###############################################################
#  Generated by:      Cadence Innovus 20.13-s083_1
#  OS:                Linux x86_64(Host ID rice-503-20-north)
#  Generated on:      Fri Jun 17 02:15:51 2022
#  Design:            user_proj_example
#  Command:           write_lef_abstract -specifyTopLayer 5 -PGPinLayers {5 6} -extractBlockObs -stripePin results/user_proj_example.lef
###############################################################

VERSION 5.8 ;

BUSBITCHARS "[]" ;
DIVIDERCHAR "/" ;

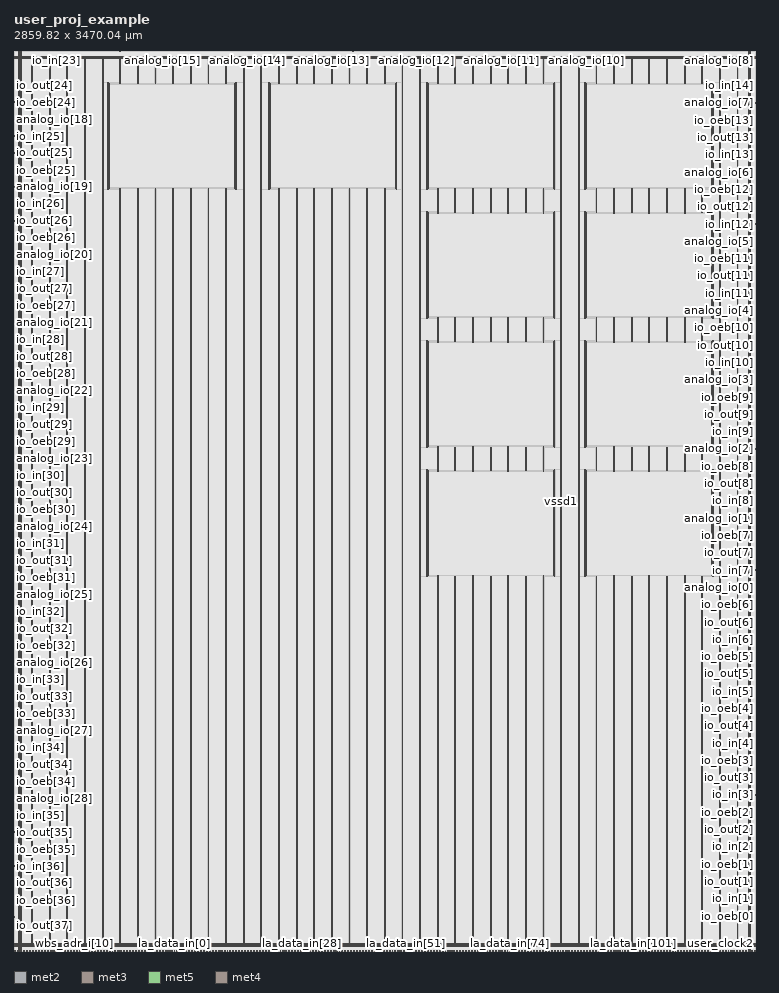
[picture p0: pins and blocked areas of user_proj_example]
MACRO user_proj_example
  CLASS BLOCK ;
  SIZE 2859.820000 BY 3470.040000 ;
  FOREIGN user_proj_example 0.000000 0.000000 ;
  ORIGIN 0 0 ;
  SYMMETRY X Y R90 ;
  PIN wb_clk_i
    DIRECTION INPUT ;
    USE SIGNAL ;
    ANTENNAPARTIALMETALAREA 3.0716 LAYER met2  ;
    ANTENNAPARTIALMETALSIDEAREA 15.197 LAYER met2  ;
    ANTENNAPARTIALCUTAREA 0.04 LAYER via2  ;
    ANTENNAPARTIALMETALAREA 8.6748 LAYER met3  ;
    ANTENNAPARTIALMETALSIDEAREA 46.736 LAYER met3  ;
    ANTENNAMODEL OXIDE1 ;
    ANTENNAGATEAREA 0.576 LAYER met3  ;
    ANTENNAMAXAREACAR 18.0158 LAYER met3  ;
    ANTENNAMAXSIDEAREACAR 93.7205 LAYER met3  ;
    ANTENNAMAXCUTCAR 0.158681 LAYER via3  ;
    PORT
      LAYER met2 ;
        RECT 0.160000 0.000000 0.300000 0.485000 ;
    END
  END wb_clk_i
  PIN wb_rst_i
    DIRECTION INPUT ;
    USE SIGNAL ;
    ANTENNAPARTIALMETALAREA 7.5498 LAYER met2  ;
    ANTENNAPARTIALMETALSIDEAREA 36.792 LAYER met2  ;
    ANTENNAMODEL OXIDE1 ;
    ANTENNAGATEAREA 2.2275 LAYER met2  ;
    ANTENNAMAXAREACAR 25.2597 LAYER met2  ;
    ANTENNAMAXSIDEAREACAR 123.945 LAYER met2  ;
    ANTENNAPARTIALCUTAREA 0.04 LAYER via2  ;
    ANTENNAMAXCUTCAR 0.316543 LAYER via2  ;
    ANTENNAPARTIALMETALAREA 13.7328 LAYER met3  ;
    ANTENNAPARTIALMETALSIDEAREA 73.712 LAYER met3  ;
    ANTENNAGATEAREA 8.055 LAYER met3  ;
    ANTENNAMAXAREACAR 26.9645 LAYER met3  ;
    ANTENNAMAXSIDEAREACAR 133.097 LAYER met3  ;
    ANTENNAMAXCUTCAR 0.316543 LAYER via3  ;
    PORT
      LAYER met2 ;
        RECT 6.140000 0.000000 6.280000 0.485000 ;
    END
  END wb_rst_i
  PIN wbs_stb_i
    DIRECTION INPUT ;
    USE SIGNAL ;
    ANTENNAPARTIALMETALAREA 4.5863 LAYER met2  ;
    ANTENNAPARTIALMETALSIDEAREA 22.8235 LAYER met2  ;
    ANTENNAMODEL OXIDE1 ;
    ANTENNAGATEAREA 0.126 LAYER met2  ;
    ANTENNAMAXAREACAR 55.8579 LAYER met2  ;
    ANTENNAMAXSIDEAREACAR 275.381 LAYER met2  ;
    ANTENNAMAXCUTCAR 0.407937 LAYER via2  ;
    PORT
      LAYER met2 ;
        RECT 23.620000 0.000000 23.760000 0.485000 ;
    END
  END wbs_stb_i
  PIN wbs_cyc_i
    DIRECTION INPUT ;
    USE SIGNAL ;
    ANTENNAPARTIALMETALAREA 4.3959 LAYER met2  ;
    ANTENNAPARTIALMETALSIDEAREA 21.8715 LAYER met2  ;
    ANTENNAMODEL OXIDE1 ;
    ANTENNAGATEAREA 0.126 LAYER met2  ;
    ANTENNAMAXAREACAR 61.8127 LAYER met2  ;
    ANTENNAMAXSIDEAREACAR 293.5 LAYER met2  ;
    ANTENNAMAXCUTCAR 0.407937 LAYER via2  ;
    PORT
      LAYER met2 ;
        RECT 18.100000 0.000000 18.240000 0.485000 ;
    END
  END wbs_cyc_i
  PIN wbs_we_i
    DIRECTION INPUT ;
    USE SIGNAL ;
    ANTENNAPARTIALMETALAREA 5.2035 LAYER met2  ;
    ANTENNAPARTIALMETALSIDEAREA 25.7915 LAYER met2  ;
    ANTENNAMODEL OXIDE1 ;
    ANTENNAGATEAREA 0.2475 LAYER met2  ;
    ANTENNAMAXAREACAR 23.9871 LAYER met2  ;
    ANTENNAMAXSIDEAREACAR 113.422 LAYER met2  ;
    ANTENNAMAXCUTCAR 0.207677 LAYER via2  ;
    PORT
      LAYER met2 ;
        RECT 29.600000 0.000000 29.740000 0.485000 ;
    END
  END wbs_we_i
  PIN wbs_sel_i[3]
    DIRECTION INPUT ;
    USE SIGNAL ;
    PORT
      LAYER met2 ;
        RECT 122.980000 0.000000 123.120000 0.485000 ;
    END
  END wbs_sel_i[3]
  PIN wbs_sel_i[2]
    DIRECTION INPUT ;
    USE SIGNAL ;
    PORT
      LAYER met2 ;
        RECT 99.520000 0.000000 99.660000 0.485000 ;
    END
  END wbs_sel_i[2]
  PIN wbs_sel_i[1]
    DIRECTION INPUT ;
    USE SIGNAL ;
    PORT
      LAYER met2 ;
        RECT 76.060000 0.000000 76.200000 0.485000 ;
    END
  END wbs_sel_i[1]
  PIN wbs_sel_i[0]
    DIRECTION INPUT ;
    USE SIGNAL ;
    PORT
      LAYER met2 ;
        RECT 53.060000 0.000000 53.200000 0.485000 ;
    END
  END wbs_sel_i[0]
  PIN wbs_dat_i[31]
    DIRECTION INPUT ;
    USE SIGNAL ;
    ANTENNAPARTIALMETALAREA 4.0627 LAYER met2  ;
    ANTENNAPARTIALMETALSIDEAREA 20.2055 LAYER met2  ;
    ANTENNAMODEL OXIDE1 ;
    ANTENNAGATEAREA 0.126 LAYER met2  ;
    ANTENNAMAXAREACAR 44.1179 LAYER met2  ;
    ANTENNAMAXSIDEAREACAR 211.175 LAYER met2  ;
    ANTENNAMAXCUTCAR 0.407937 LAYER via2  ;
    PORT
      LAYER met2 ;
        RECT 607.360000 0.000000 607.500000 0.485000 ;
    END
  END wbs_dat_i[31]
  PIN wbs_dat_i[30]
    DIRECTION INPUT ;
    USE SIGNAL ;
    ANTENNAPARTIALMETALAREA 4.0627 LAYER met2  ;
    ANTENNAPARTIALMETALSIDEAREA 20.2055 LAYER met2  ;
    ANTENNAMODEL OXIDE1 ;
    ANTENNAGATEAREA 0.126 LAYER met2  ;
    ANTENNAMAXAREACAR 45.3103 LAYER met2  ;
    ANTENNAMAXSIDEAREACAR 221.032 LAYER met2  ;
    ANTENNAMAXCUTCAR 0.407937 LAYER via2  ;
    PORT
      LAYER met2 ;
        RECT 589.880000 0.000000 590.020000 0.485000 ;
    END
  END wbs_dat_i[30]
  PIN wbs_dat_i[29]
    DIRECTION INPUT ;
    USE SIGNAL ;
    ANTENNAPARTIALMETALAREA 4.3035 LAYER met2  ;
    ANTENNAPARTIALMETALSIDEAREA 21.4095 LAYER met2  ;
    ANTENNAMODEL OXIDE1 ;
    ANTENNAGATEAREA 0.126 LAYER met2  ;
    ANTENNAMAXAREACAR 36.1921 LAYER met2  ;
    ANTENNAMAXSIDEAREACAR 175.976 LAYER met2  ;
    ANTENNAMAXCUTCAR 0.407937 LAYER via2  ;
    PORT
      LAYER met2 ;
        RECT 572.400000 0.000000 572.540000 0.485000 ;
    END
  END wbs_dat_i[29]
  PIN wbs_dat_i[28]
    DIRECTION INPUT ;
    USE SIGNAL ;
    ANTENNAPARTIALMETALAREA 4.8684 LAYER met2  ;
    ANTENNAPARTIALMETALSIDEAREA 24.234 LAYER met2  ;
    ANTENNAMODEL OXIDE1 ;
    ANTENNAGATEAREA 0.126 LAYER met2  ;
    ANTENNAMAXAREACAR 51.8048 LAYER met2  ;
    ANTENNAMAXSIDEAREACAR 253.504 LAYER met2  ;
    ANTENNAMAXCUTCAR 0.407937 LAYER via2  ;
    PORT
      LAYER met2 ;
        RECT 554.920000 0.000000 555.060000 0.485000 ;
    END
  END wbs_dat_i[28]
  PIN wbs_dat_i[27]
    DIRECTION INPUT ;
    USE SIGNAL ;
    ANTENNAPARTIALMETALAREA 4.3511 LAYER met2  ;
    ANTENNAPARTIALMETALSIDEAREA 21.6475 LAYER met2  ;
    ANTENNAMODEL OXIDE1 ;
    ANTENNAGATEAREA 0.126 LAYER met2  ;
    ANTENNAMAXAREACAR 39.0103 LAYER met2  ;
    ANTENNAMAXSIDEAREACAR 189.532 LAYER met2  ;
    ANTENNAMAXCUTCAR 0.407937 LAYER via2  ;
    PORT
      LAYER met2 ;
        RECT 537.440000 0.000000 537.580000 0.485000 ;
    END
  END wbs_dat_i[27]
  PIN wbs_dat_i[26]
    DIRECTION INPUT ;
    USE SIGNAL ;
    ANTENNAPARTIALMETALAREA 4.2531 LAYER met2  ;
    ANTENNAPARTIALMETALSIDEAREA 21.1575 LAYER met2  ;
    ANTENNAMODEL OXIDE1 ;
    ANTENNAGATEAREA 0.126 LAYER met2  ;
    ANTENNAMAXAREACAR 52.0925 LAYER met2  ;
    ANTENNAMAXSIDEAREACAR 252.802 LAYER met2  ;
    ANTENNAMAXCUTCAR 0.407937 LAYER via2  ;
    PORT
      LAYER met2 ;
        RECT 519.960000 0.000000 520.100000 0.485000 ;
    END
  END wbs_dat_i[26]
  PIN wbs_dat_i[25]
    DIRECTION INPUT ;
    USE SIGNAL ;
    ANTENNAPARTIALMETALAREA 4.4895 LAYER met2  ;
    ANTENNAPARTIALMETALSIDEAREA 22.2215 LAYER met2  ;
    ANTENNAMODEL OXIDE1 ;
    ANTENNAGATEAREA 0.126 LAYER met2  ;
    ANTENNAMAXAREACAR 40.6198 LAYER met2  ;
    ANTENNAMAXSIDEAREACAR 196.643 LAYER met2  ;
    ANTENNAMAXCUTCAR 0.407937 LAYER via2  ;
    PORT
      LAYER met2 ;
        RECT 502.020000 0.000000 502.160000 0.485000 ;
    END
  END wbs_dat_i[25]
  PIN wbs_dat_i[24]
    DIRECTION INPUT ;
    USE SIGNAL ;
    ANTENNAPARTIALMETALAREA 4.3607 LAYER met2  ;
    ANTENNAPARTIALMETALSIDEAREA 21.5775 LAYER met2  ;
    ANTENNAMODEL OXIDE1 ;
    ANTENNAGATEAREA 0.126 LAYER met2  ;
    ANTENNAMAXAREACAR 37.5532 LAYER met2  ;
    ANTENNAMAXSIDEAREACAR 181.31 LAYER met2  ;
    ANTENNAMAXCUTCAR 0.407937 LAYER via2  ;
    PORT
      LAYER met2 ;
        RECT 484.540000 0.000000 484.680000 0.485000 ;
    END
  END wbs_dat_i[24]
  PIN wbs_dat_i[23]
    DIRECTION INPUT ;
    USE SIGNAL ;
    ANTENNAPARTIALMETALAREA 4.3817 LAYER met2  ;
    ANTENNAPARTIALMETALSIDEAREA 21.6825 LAYER met2  ;
    ANTENNAMODEL OXIDE1 ;
    ANTENNAGATEAREA 0.126 LAYER met2  ;
    ANTENNAMAXAREACAR 37.2087 LAYER met2  ;
    ANTENNAMAXSIDEAREACAR 179.587 LAYER met2  ;
    ANTENNAMAXCUTCAR 0.407937 LAYER via2  ;
    PORT
      LAYER met2 ;
        RECT 467.060000 0.000000 467.200000 0.485000 ;
    END
  END wbs_dat_i[23]
  PIN wbs_dat_i[22]
    DIRECTION INPUT ;
    USE SIGNAL ;
    ANTENNAPARTIALMETALAREA 4.2319 LAYER met2  ;
    ANTENNAPARTIALMETALSIDEAREA 20.9335 LAYER met2  ;
    ANTENNAMODEL OXIDE1 ;
    ANTENNAGATEAREA 0.126 LAYER met2  ;
    ANTENNAMAXAREACAR 60.5532 LAYER met2  ;
    ANTENNAMAXSIDEAREACAR 296.31 LAYER met2  ;
    ANTENNAMAXCUTCAR 0.407937 LAYER via2  ;
    PORT
      LAYER met2 ;
        RECT 449.580000 0.000000 449.720000 0.485000 ;
    END
  END wbs_dat_i[22]
  PIN wbs_dat_i[21]
    DIRECTION INPUT ;
    USE SIGNAL ;
    ANTENNAPARTIALMETALAREA 4.4911 LAYER met2  ;
    ANTENNAPARTIALMETALSIDEAREA 22.3475 LAYER met2  ;
    ANTENNAMODEL OXIDE1 ;
    ANTENNAGATEAREA 0.126 LAYER met2  ;
    ANTENNAMAXAREACAR 80.9655 LAYER met2  ;
    ANTENNAMAXSIDEAREACAR 393.659 LAYER met2  ;
    ANTENNAMAXCUTCAR 0.407937 LAYER via2  ;
    PORT
      LAYER met2 ;
        RECT 432.100000 0.000000 432.240000 0.485000 ;
    END
  END wbs_dat_i[21]
  PIN wbs_dat_i[20]
    DIRECTION INPUT ;
    USE SIGNAL ;
    ANTENNAPARTIALMETALAREA 4.4083 LAYER met2  ;
    ANTENNAPARTIALMETALSIDEAREA 21.8155 LAYER met2  ;
    ANTENNAMODEL OXIDE1 ;
    ANTENNAGATEAREA 0.126 LAYER met2  ;
    ANTENNAMAXAREACAR 37.0238 LAYER met2  ;
    ANTENNAMAXSIDEAREACAR 179.198 LAYER met2  ;
    ANTENNAMAXCUTCAR 0.407937 LAYER via2  ;
    PORT
      LAYER met2 ;
        RECT 414.620000 0.000000 414.760000 0.485000 ;
    END
  END wbs_dat_i[20]
  PIN wbs_dat_i[19]
    DIRECTION INPUT ;
    USE SIGNAL ;
    ANTENNAPARTIALMETALAREA 4.1843 LAYER met2  ;
    ANTENNAPARTIALMETALSIDEAREA 20.6955 LAYER met2  ;
    ANTENNAMODEL OXIDE1 ;
    ANTENNAGATEAREA 0.126 LAYER met2  ;
    ANTENNAMAXAREACAR 47.8087 LAYER met2  ;
    ANTENNAMAXSIDEAREACAR 232.587 LAYER met2  ;
    ANTENNAMAXCUTCAR 0.407937 LAYER via2  ;
    PORT
      LAYER met2 ;
        RECT 397.140000 0.000000 397.280000 0.485000 ;
    END
  END wbs_dat_i[19]
  PIN wbs_dat_i[18]
    DIRECTION INPUT ;
    USE SIGNAL ;
    ANTENNAPARTIALMETALAREA 5.3834 LAYER met2  ;
    ANTENNAPARTIALMETALSIDEAREA 26.691 LAYER met2  ;
    ANTENNAMODEL OXIDE1 ;
    ANTENNAGATEAREA 0.126 LAYER met2  ;
    ANTENNAMAXAREACAR 51.5365 LAYER met2  ;
    ANTENNAMAXSIDEAREACAR 251.226 LAYER met2  ;
    ANTENNAMAXCUTCAR 0.407937 LAYER via2  ;
    PORT
      LAYER met2 ;
        RECT 379.660000 0.000000 379.800000 0.485000 ;
    END
  END wbs_dat_i[18]
  PIN wbs_dat_i[17]
    DIRECTION INPUT ;
    USE SIGNAL ;
    ANTENNAPARTIALMETALAREA 4.2867 LAYER met2  ;
    ANTENNAPARTIALMETALSIDEAREA 21.3255 LAYER met2  ;
    ANTENNAMODEL OXIDE1 ;
    ANTENNAGATEAREA 0.126 LAYER met2  ;
    ANTENNAMAXAREACAR 42.077 LAYER met2  ;
    ANTENNAMAXSIDEAREACAR 204.865 LAYER met2  ;
    ANTENNAMAXCUTCAR 0.407937 LAYER via2  ;
    PORT
      LAYER met2 ;
        RECT 362.180000 0.000000 362.320000 0.485000 ;
    END
  END wbs_dat_i[17]
  PIN wbs_dat_i[16]
    DIRECTION INPUT ;
    USE SIGNAL ;
    ANTENNAPARTIALMETALAREA 4.4631 LAYER met2  ;
    ANTENNAPARTIALMETALSIDEAREA 22.2075 LAYER met2  ;
    ANTENNAMODEL OXIDE1 ;
    ANTENNAGATEAREA 0.126 LAYER met2  ;
    ANTENNAMAXAREACAR 53.5313 LAYER met2  ;
    ANTENNAMAXSIDEAREACAR 258.159 LAYER met2  ;
    ANTENNAMAXCUTCAR 0.407937 LAYER via2  ;
    PORT
      LAYER met2 ;
        RECT 344.700000 0.000000 344.840000 0.485000 ;
    END
  END wbs_dat_i[16]
  PIN wbs_dat_i[15]
    DIRECTION INPUT ;
    USE SIGNAL ;
    ANTENNAPARTIALMETALAREA 5.4067 LAYER met2  ;
    ANTENNAPARTIALMETALSIDEAREA 26.9255 LAYER met2  ;
    ANTENNAMODEL OXIDE1 ;
    ANTENNAGATEAREA 0.126 LAYER met2  ;
    ANTENNAMAXAREACAR 47.8992 LAYER met2  ;
    ANTENNAMAXSIDEAREACAR 233.976 LAYER met2  ;
    ANTENNAMAXCUTCAR 0.407937 LAYER via2  ;
    PORT
      LAYER met2 ;
        RECT 327.220000 0.000000 327.360000 0.485000 ;
    END
  END wbs_dat_i[15]
  PIN wbs_dat_i[14]
    DIRECTION INPUT ;
    USE SIGNAL ;
    ANTENNAPARTIALMETALAREA 4.2699 LAYER met2  ;
    ANTENNAPARTIALMETALSIDEAREA 21.2415 LAYER met2  ;
    ANTENNAMODEL OXIDE1 ;
    ANTENNAGATEAREA 0.126 LAYER met2  ;
    ANTENNAMAXAREACAR 48.9433 LAYER met2  ;
    ANTENNAMAXSIDEAREACAR 233.548 LAYER met2  ;
    ANTENNAMAXCUTCAR 0.407937 LAYER via2  ;
    PORT
      LAYER met2 ;
        RECT 309.740000 0.000000 309.880000 0.485000 ;
    END
  END wbs_dat_i[14]
  PIN wbs_dat_i[13]
    DIRECTION INPUT ;
    USE SIGNAL ;
    ANTENNAPARTIALMETALAREA 4.3131 LAYER met2  ;
    ANTENNAPARTIALMETALSIDEAREA 21.3395 LAYER met2  ;
    ANTENNAMODEL OXIDE1 ;
    ANTENNAGATEAREA 0.126 LAYER met2  ;
    ANTENNAMAXAREACAR 43.7159 LAYER met2  ;
    ANTENNAMAXSIDEAREACAR 202.548 LAYER met2  ;
    ANTENNAMAXCUTCAR 0.407937 LAYER via2  ;
    PORT
      LAYER met2 ;
        RECT 292.260000 0.000000 292.400000 0.485000 ;
    END
  END wbs_dat_i[13]
  PIN wbs_dat_i[12]
    DIRECTION INPUT ;
    USE SIGNAL ;
    ANTENNAPARTIALMETALAREA 6.0255 LAYER met2  ;
    ANTENNAPARTIALMETALSIDEAREA 30.0195 LAYER met2  ;
    ANTENNAMODEL OXIDE1 ;
    ANTENNAGATEAREA 0.126 LAYER met2  ;
    ANTENNAMAXAREACAR 52.7758 LAYER met2  ;
    ANTENNAMAXSIDEAREACAR 254.381 LAYER met2  ;
    ANTENNAMAXCUTCAR 0.407937 LAYER via2  ;
    PORT
      LAYER met2 ;
        RECT 274.780000 0.000000 274.920000 0.485000 ;
    END
  END wbs_dat_i[12]
  PIN wbs_dat_i[11]
    DIRECTION INPUT ;
    USE SIGNAL ;
    ANTENNAPARTIALMETALAREA 4.5555 LAYER met2  ;
    ANTENNAPARTIALMETALSIDEAREA 22.6695 LAYER met2  ;
    ANTENNAMODEL OXIDE1 ;
    ANTENNAGATEAREA 0.126 LAYER met2  ;
    ANTENNAMAXAREACAR 45.1766 LAYER met2  ;
    ANTENNAMAXSIDEAREACAR 214.714 LAYER met2  ;
    ANTENNAMAXCUTCAR 0.407937 LAYER via2  ;
    PORT
      LAYER met2 ;
        RECT 257.300000 0.000000 257.440000 0.485000 ;
    END
  END wbs_dat_i[11]
  PIN wbs_dat_i[10]
    DIRECTION INPUT ;
    USE SIGNAL ;
    ANTENNAPARTIALMETALAREA 4.032 LAYER met2  ;
    ANTENNAPARTIALMETALSIDEAREA 19.999 LAYER met2  ;
    ANTENNAPARTIALCUTAREA 0.04 LAYER via2  ;
    ANTENNAPARTIALMETALAREA 4.885 LAYER met3  ;
    ANTENNAPARTIALMETALSIDEAREA 26.52 LAYER met3  ;
    ANTENNAPARTIALCUTAREA 0.04 LAYER via3  ;
    ANTENNAPARTIALMETALAREA 0.6516 LAYER met4  ;
    ANTENNAPARTIALMETALSIDEAREA 4.416 LAYER met4  ;
    ANTENNAMODEL OXIDE1 ;
    ANTENNAGATEAREA 0.126 LAYER met4  ;
    ANTENNAMAXAREACAR 29.0183 LAYER met4  ;
    ANTENNAMAXSIDEAREACAR 150.532 LAYER met4  ;
    ANTENNAMAXCUTCAR 1.04286 LAYER via4  ;
    PORT
      LAYER met2 ;
        RECT 239.820000 0.000000 239.960000 0.485000 ;
    END
  END wbs_dat_i[10]
  PIN wbs_dat_i[9]
    DIRECTION INPUT ;
    USE SIGNAL ;
    ANTENNAPARTIALMETALAREA 5.1226 LAYER met2  ;
    ANTENNAPARTIALMETALSIDEAREA 25.452 LAYER met2  ;
    ANTENNAPARTIALCUTAREA 0.04 LAYER via2  ;
    ANTENNAPARTIALMETALAREA 12.427 LAYER met3  ;
    ANTENNAPARTIALMETALSIDEAREA 66.744 LAYER met3  ;
    ANTENNAPARTIALCUTAREA 0.04 LAYER via3  ;
    ANTENNAPARTIALMETALAREA 0.6516 LAYER met4  ;
    ANTENNAPARTIALMETALSIDEAREA 4.416 LAYER met4  ;
    ANTENNAMODEL OXIDE1 ;
    ANTENNAGATEAREA 0.126 LAYER met4  ;
    ANTENNAMAXAREACAR 40.0976 LAYER met4  ;
    ANTENNAMAXSIDEAREACAR 210.492 LAYER met4  ;
    ANTENNAMAXCUTCAR 1.04286 LAYER via4  ;
    PORT
      LAYER met2 ;
        RECT 222.340000 0.000000 222.480000 0.485000 ;
    END
  END wbs_dat_i[9]
  PIN wbs_dat_i[8]
    DIRECTION INPUT ;
    USE SIGNAL ;
    ANTENNAPARTIALMETALAREA 4.5861 LAYER met2  ;
    ANTENNAPARTIALMETALSIDEAREA 22.7045 LAYER met2  ;
    ANTENNAMODEL OXIDE1 ;
    ANTENNAGATEAREA 0.126 LAYER met2  ;
    ANTENNAMAXAREACAR 53.6187 LAYER met2  ;
    ANTENNAMAXSIDEAREACAR 257.659 LAYER met2  ;
    ANTENNAMAXCUTCAR 0.407937 LAYER via2  ;
    PORT
      LAYER met2 ;
        RECT 204.400000 0.000000 204.540000 0.485000 ;
    END
  END wbs_dat_i[8]
  PIN wbs_dat_i[7]
    DIRECTION INPUT ;
    USE SIGNAL ;
    ANTENNAPARTIALMETALAREA 5.9315 LAYER met2  ;
    ANTENNAPARTIALMETALSIDEAREA 29.4315 LAYER met2  ;
    ANTENNAMODEL OXIDE1 ;
    ANTENNAGATEAREA 0.126 LAYER met2  ;
    ANTENNAMAXAREACAR 50.1004 LAYER met2  ;
    ANTENNAMAXSIDEAREACAR 240.603 LAYER met2  ;
    ANTENNAMAXCUTCAR 0.407937 LAYER via2  ;
    PORT
      LAYER met2 ;
        RECT 186.920000 0.000000 187.060000 0.485000 ;
    END
  END wbs_dat_i[7]
  PIN wbs_dat_i[6]
    DIRECTION INPUT ;
    USE SIGNAL ;
    ANTENNAPARTIALMETALAREA 4.6939 LAYER met2  ;
    ANTENNAPARTIALMETALSIDEAREA 23.2435 LAYER met2  ;
    ANTENNAMODEL OXIDE1 ;
    ANTENNAGATEAREA 0.126 LAYER met2  ;
    ANTENNAMAXAREACAR 40.7087 LAYER met2  ;
    ANTENNAMAXSIDEAREACAR 197.087 LAYER met2  ;
    ANTENNAMAXCUTCAR 0.407937 LAYER via2  ;
    PORT
      LAYER met2 ;
        RECT 169.440000 0.000000 169.580000 0.485000 ;
    END
  END wbs_dat_i[6]
  PIN wbs_dat_i[5]
    DIRECTION INPUT ;
    USE SIGNAL ;
    ANTENNAPARTIALMETALAREA 4.1843 LAYER met2  ;
    ANTENNAPARTIALMETALSIDEAREA 20.6955 LAYER met2  ;
    ANTENNAMODEL OXIDE1 ;
    ANTENNAGATEAREA 0.126 LAYER met2  ;
    ANTENNAMAXAREACAR 35.246 LAYER met2  ;
    ANTENNAMAXSIDEAREACAR 170.31 LAYER met2  ;
    ANTENNAMAXCUTCAR 0.407937 LAYER via2  ;
    PORT
      LAYER met2 ;
        RECT 151.960000 0.000000 152.100000 0.485000 ;
    END
  END wbs_dat_i[5]
  PIN wbs_dat_i[4]
    DIRECTION INPUT ;
    USE SIGNAL ;
    ANTENNAPARTIALMETALAREA 4.1915 LAYER met2  ;
    ANTENNAPARTIALMETALSIDEAREA 20.8495 LAYER met2  ;
    ANTENNAMODEL OXIDE1 ;
    ANTENNAGATEAREA 0.126 LAYER met2  ;
    ANTENNAMAXAREACAR 73.2659 LAYER met2  ;
    ANTENNAMAXSIDEAREACAR 360.81 LAYER met2  ;
    ANTENNAMAXCUTCAR 0.407937 LAYER via2  ;
    PORT
      LAYER met2 ;
        RECT 134.480000 0.000000 134.620000 0.485000 ;
    END
  END wbs_dat_i[4]
  PIN wbs_dat_i[3]
    DIRECTION INPUT ;
    USE SIGNAL ;
    ANTENNAPARTIALMETALAREA 4.1915 LAYER met2  ;
    ANTENNAPARTIALMETALSIDEAREA 20.8495 LAYER met2  ;
    ANTENNAMODEL OXIDE1 ;
    ANTENNAGATEAREA 0.126 LAYER met2  ;
    ANTENNAMAXAREACAR 40.1952 LAYER met2  ;
    ANTENNAMAXSIDEAREACAR 185.881 LAYER met2  ;
    ANTENNAMAXCUTCAR 0.407937 LAYER via2  ;
    PORT
      LAYER met2 ;
        RECT 111.480000 0.000000 111.620000 0.485000 ;
    END
  END wbs_dat_i[3]
  PIN wbs_dat_i[2]
    DIRECTION INPUT ;
    USE SIGNAL ;
    ANTENNAPARTIALMETALAREA 4.8243 LAYER met2  ;
    ANTENNAPARTIALMETALSIDEAREA 24.0135 LAYER met2  ;
    ANTENNAMODEL OXIDE1 ;
    ANTENNAGATEAREA 0.126 LAYER met2  ;
    ANTENNAMAXAREACAR 57.4619 LAYER met2  ;
    ANTENNAMAXSIDEAREACAR 272.214 LAYER met2  ;
    ANTENNAMAXCUTCAR 0.407937 LAYER via2  ;
    PORT
      LAYER met2 ;
        RECT 88.020000 0.000000 88.160000 0.485000 ;
    END
  END wbs_dat_i[2]
  PIN wbs_dat_i[1]
    DIRECTION INPUT ;
    USE SIGNAL ;
    ANTENNAPARTIALMETALAREA 4.7149 LAYER met2  ;
    ANTENNAPARTIALMETALSIDEAREA 23.3485 LAYER met2  ;
    ANTENNAMODEL OXIDE1 ;
    ANTENNAGATEAREA 0.126 LAYER met2  ;
    ANTENNAMAXAREACAR 39.8532 LAYER met2  ;
    ANTENNAMAXSIDEAREACAR 192.81 LAYER met2  ;
    ANTENNAMAXCUTCAR 0.407937 LAYER via2  ;
    PORT
      LAYER met2 ;
        RECT 64.560000 0.000000 64.700000 0.485000 ;
    END
  END wbs_dat_i[1]
  PIN wbs_dat_i[0]
    DIRECTION INPUT ;
    USE SIGNAL ;
    ANTENNAPARTIALMETALAREA 12.9037 LAYER met2  ;
    ANTENNAPARTIALMETALSIDEAREA 63.9485 LAYER met2  ;
    ANTENNAMODEL OXIDE1 ;
    ANTENNAGATEAREA 0.567 LAYER met2  ;
    ANTENNAMAXAREACAR 36.3797 LAYER met2  ;
    ANTENNAMAXSIDEAREACAR 170.582 LAYER met2  ;
    ANTENNAMAXCUTCAR 0.407937 LAYER via2  ;
    PORT
      LAYER met2 ;
        RECT 41.100000 0.000000 41.240000 0.485000 ;
    END
  END wbs_dat_i[0]
  PIN wbs_adr_i[31]
    DIRECTION INPUT ;
    USE SIGNAL ;
    ANTENNAPARTIALMETALAREA 5.0319 LAYER met2  ;
    ANTENNAPARTIALMETALSIDEAREA 24.8255 LAYER met2  ;
    ANTENNAMODEL OXIDE1 ;
    ANTENNAGATEAREA 0.252 LAYER met2  ;
    ANTENNAMAXAREACAR 23.4198 LAYER met2  ;
    ANTENNAMAXSIDEAREACAR 107.216 LAYER met2  ;
    ANTENNAMAXCUTCAR 0.407937 LAYER via2  ;
    PORT
      LAYER met2 ;
        RECT 601.380000 0.000000 601.520000 0.485000 ;
    END
  END wbs_adr_i[31]
  PIN wbs_adr_i[30]
    DIRECTION INPUT ;
    USE SIGNAL ;
    ANTENNAPARTIALMETALAREA 4.6559 LAYER met2  ;
    ANTENNAPARTIALMETALSIDEAREA 22.9355 LAYER met2  ;
    ANTENNAMODEL OXIDE1 ;
    ANTENNAGATEAREA 0.252 LAYER met2  ;
    ANTENNAMAXAREACAR 50.4651 LAYER met2  ;
    ANTENNAMAXSIDEAREACAR 234.105 LAYER met2  ;
    ANTENNAMAXCUTCAR 0.586508 LAYER via2  ;
    PORT
      LAYER met2 ;
        RECT 583.900000 0.000000 584.040000 0.485000 ;
    END
  END wbs_adr_i[30]
  PIN wbs_adr_i[29]
    DIRECTION INPUT ;
    USE SIGNAL ;
    ANTENNAPARTIALMETALAREA 4.3467 LAYER met2  ;
    ANTENNAPARTIALMETALSIDEAREA 21.5075 LAYER met2  ;
    ANTENNAMODEL OXIDE1 ;
    ANTENNAGATEAREA 0.3735 LAYER met2  ;
    ANTENNAMAXAREACAR 21.5913 LAYER met2  ;
    ANTENNAMAXSIDEAREACAR 102.721 LAYER met2  ;
    ANTENNAMAXCUTCAR 0.289606 LAYER via2  ;
    PORT
      LAYER met2 ;
        RECT 566.420000 0.000000 566.560000 0.485000 ;
    END
  END wbs_adr_i[29]
  PIN wbs_adr_i[28]
    DIRECTION INPUT ;
    USE SIGNAL ;
    ANTENNAPARTIALMETALAREA 4.8939 LAYER met2  ;
    ANTENNAPARTIALMETALSIDEAREA 24.1255 LAYER met2  ;
    ANTENNAMODEL OXIDE1 ;
    ANTENNAGATEAREA 0.3735 LAYER met2  ;
    ANTENNAMAXAREACAR 19.6891 LAYER met2  ;
    ANTENNAMAXSIDEAREACAR 91.6981 LAYER met2  ;
    ANTENNAMAXCUTCAR 0.407937 LAYER via2  ;
    PORT
      LAYER met2 ;
        RECT 548.940000 0.000000 549.080000 0.485000 ;
    END
  END wbs_adr_i[28]
  PIN wbs_adr_i[27]
    DIRECTION INPUT ;
    USE SIGNAL ;
    ANTENNAPARTIALMETALAREA 4.43 LAYER met2  ;
    ANTENNAPARTIALMETALSIDEAREA 21.924 LAYER met2  ;
    ANTENNAMODEL OXIDE1 ;
    ANTENNAGATEAREA 0.3735 LAYER met2  ;
    ANTENNAMAXAREACAR 20.239 LAYER met2  ;
    ANTENNAMAXSIDEAREACAR 90.5054 LAYER met2  ;
    ANTENNAMAXCUTCAR 0.289606 LAYER via2  ;
    PORT
      LAYER met2 ;
        RECT 531.460000 0.000000 531.600000 0.485000 ;
    END
  END wbs_adr_i[27]
  PIN wbs_adr_i[26]
    DIRECTION INPUT ;
    USE SIGNAL ;
    ANTENNAPARTIALMETALAREA 4.6407 LAYER met2  ;
    ANTENNAPARTIALMETALSIDEAREA 22.9775 LAYER met2  ;
    ANTENNAMODEL OXIDE1 ;
    ANTENNAGATEAREA 0.252 LAYER met2  ;
    ANTENNAMAXAREACAR 33.5841 LAYER met2  ;
    ANTENNAMAXSIDEAREACAR 150.49 LAYER met2  ;
    ANTENNAMAXCUTCAR 0.318651 LAYER via2  ;
    PORT
      LAYER met2 ;
        RECT 513.980000 0.000000 514.120000 0.485000 ;
    END
  END wbs_adr_i[26]
  PIN wbs_adr_i[25]
    DIRECTION INPUT ;
    USE SIGNAL ;
    ANTENNAPARTIALMETALAREA 5.3413 LAYER met2  ;
    ANTENNAPARTIALMETALSIDEAREA 26.3725 LAYER met2  ;
    ANTENNAMODEL OXIDE1 ;
    ANTENNAGATEAREA 0.621 LAYER met2  ;
    ANTENNAMAXAREACAR 13.0789 LAYER met2  ;
    ANTENNAMAXSIDEAREACAR 60.194 LAYER met2  ;
    ANTENNAMAXCUTCAR 0.407937 LAYER via2  ;
    PORT
      LAYER met2 ;
        RECT 496.500000 0.000000 496.640000 0.485000 ;
    END
  END wbs_adr_i[25]
  PIN wbs_adr_i[24]
    DIRECTION INPUT ;
    USE SIGNAL ;
    ANTENNAPARTIALMETALAREA 5.1011 LAYER met2  ;
    ANTENNAPARTIALMETALSIDEAREA 25.1615 LAYER met2  ;
    ANTENNAMODEL OXIDE1 ;
    ANTENNAGATEAREA 0.621 LAYER met2  ;
    ANTENNAMAXAREACAR 17.2362 LAYER met2  ;
    ANTENNAMAXSIDEAREACAR 75.3153 LAYER met2  ;
    ANTENNAMAXCUTCAR 0.407937 LAYER via2  ;
    PORT
      LAYER met2 ;
        RECT 479.020000 0.000000 479.160000 0.485000 ;
    END
  END wbs_adr_i[24]
  PIN wbs_adr_i[23]
    DIRECTION INPUT ;
    USE SIGNAL ;
    ANTENNAPARTIALMETALAREA 5.3909 LAYER met2  ;
    ANTENNAPARTIALMETALSIDEAREA 26.6105 LAYER met2  ;
    ANTENNAMODEL OXIDE1 ;
    ANTENNAGATEAREA 0.621 LAYER met2  ;
    ANTENNAMAXAREACAR 10.7183 LAYER met2  ;
    ANTENNAMAXSIDEAREACAR 48.9106 LAYER met2  ;
    ANTENNAMAXCUTCAR 0.407937 LAYER via2  ;
    PORT
      LAYER met2 ;
        RECT 461.540000 0.000000 461.680000 0.485000 ;
    END
  END wbs_adr_i[23]
  PIN wbs_adr_i[22]
    DIRECTION INPUT ;
    USE SIGNAL ;
    ANTENNAPARTIALMETALAREA 4.8439 LAYER met2  ;
    ANTENNAPARTIALMETALSIDEAREA 24.1115 LAYER met2  ;
    ANTENNAMODEL OXIDE1 ;
    ANTENNAGATEAREA 0.621 LAYER met2  ;
    ANTENNAMAXAREACAR 9.64211 LAYER met2  ;
    ANTENNAMAXSIDEAREACAR 41.8905 LAYER met2  ;
    ANTENNAMAXCUTCAR 0.0827697 LAYER via2  ;
    PORT
      LAYER met2 ;
        RECT 444.060000 0.000000 444.200000 0.485000 ;
    END
  END wbs_adr_i[22]
  PIN wbs_adr_i[21]
    DIRECTION INPUT ;
    USE SIGNAL ;
    ANTENNAPARTIALMETALAREA 4.0627 LAYER met2  ;
    ANTENNAPARTIALMETALSIDEAREA 20.2055 LAYER met2  ;
    ANTENNAMODEL OXIDE1 ;
    ANTENNAGATEAREA 0.252 LAYER met2  ;
    ANTENNAMAXAREACAR 24.95 LAYER met2  ;
    ANTENNAMAXSIDEAREACAR 119.698 LAYER met2  ;
    ANTENNAMAXCUTCAR 0.318651 LAYER via2  ;
    PORT
      LAYER met2 ;
        RECT 426.580000 0.000000 426.720000 0.485000 ;
    END
  END wbs_adr_i[21]
  PIN wbs_adr_i[20]
    DIRECTION INPUT ;
    USE SIGNAL ;
    ANTENNAPARTIALMETALAREA 4.9935 LAYER met2  ;
    ANTENNAPARTIALMETALSIDEAREA 24.7415 LAYER met2  ;
    ANTENNAMODEL OXIDE1 ;
    ANTENNAGATEAREA 0.3735 LAYER met2  ;
    ANTENNAMAXAREACAR 29.4695 LAYER met2  ;
    ANTENNAMAXSIDEAREACAR 142.08 LAYER met2  ;
    ANTENNAMAXCUTCAR 0.407937 LAYER via2  ;
    PORT
      LAYER met2 ;
        RECT 408.640000 0.000000 408.780000 0.485000 ;
    END
  END wbs_adr_i[20]
  PIN wbs_adr_i[19]
    DIRECTION INPUT ;
    USE SIGNAL ;
    ANTENNAPARTIALMETALAREA 5.5381 LAYER met2  ;
    ANTENNAPARTIALMETALSIDEAREA 27.4645 LAYER met2  ;
    ANTENNAMODEL OXIDE1 ;
    ANTENNAGATEAREA 0.3735 LAYER met2  ;
    ANTENNAMAXAREACAR 20.1605 LAYER met2  ;
    ANTENNAMAXSIDEAREACAR 94.9732 LAYER met2  ;
    ANTENNAMAXCUTCAR 0.407937 LAYER via2  ;
    PORT
      LAYER met2 ;
        RECT 391.160000 0.000000 391.300000 0.485000 ;
    END
  END wbs_adr_i[19]
  PIN wbs_adr_i[18]
    DIRECTION INPUT ;
    USE SIGNAL ;
    ANTENNAPARTIALMETALAREA 4.3035 LAYER met2  ;
    ANTENNAPARTIALMETALSIDEAREA 21.4095 LAYER met2  ;
    ANTENNAMODEL OXIDE1 ;
    ANTENNAGATEAREA 0.3735 LAYER met2  ;
    ANTENNAMAXAREACAR 24.4165 LAYER met2  ;
    ANTENNAMAXSIDEAREACAR 111.171 LAYER met2  ;
    ANTENNAMAXCUTCAR 0.518971 LAYER via2  ;
    PORT
      LAYER met2 ;
        RECT 373.680000 0.000000 373.820000 0.485000 ;
    END
  END wbs_adr_i[18]
  PIN wbs_adr_i[17]
    DIRECTION INPUT ;
    USE SIGNAL ;
    ANTENNAPARTIALMETALAREA 4.7323 LAYER met2  ;
    ANTENNAPARTIALMETALSIDEAREA 23.3275 LAYER met2  ;
    ANTENNAMODEL OXIDE1 ;
    ANTENNAGATEAREA 0.3735 LAYER met2  ;
    ANTENNAMAXAREACAR 21.6396 LAYER met2  ;
    ANTENNAMAXSIDEAREACAR 95.2382 LAYER met2  ;
    ANTENNAMAXCUTCAR 0.407937 LAYER via2  ;
    PORT
      LAYER met2 ;
        RECT 356.200000 0.000000 356.340000 0.485000 ;
    END
  END wbs_adr_i[17]
  PIN wbs_adr_i[16]
    DIRECTION INPUT ;
    USE SIGNAL ;
    ANTENNAPARTIALMETALAREA 5.1461 LAYER met2  ;
    ANTENNAPARTIALMETALSIDEAREA 25.4065 LAYER met2  ;
    ANTENNAMODEL OXIDE1 ;
    ANTENNAGATEAREA 0.6885 LAYER met2  ;
    ANTENNAMAXAREACAR 22.6008 LAYER met2  ;
    ANTENNAMAXSIDEAREACAR 109.962 LAYER met2  ;
    ANTENNAMAXCUTCAR 0.407937 LAYER via2  ;
    PORT
      LAYER met2 ;
        RECT 338.720000 0.000000 338.860000 0.485000 ;
    END
  END wbs_adr_i[16]
  PIN wbs_adr_i[15]
    DIRECTION INPUT ;
    USE SIGNAL ;
    ANTENNAPARTIALMETALAREA 4.7673 LAYER met2  ;
    ANTENNAPARTIALMETALSIDEAREA 23.5025 LAYER met2  ;
    ANTENNAMODEL OXIDE1 ;
    ANTENNAGATEAREA 0.3735 LAYER met2  ;
    ANTENNAMAXAREACAR 20.8682 LAYER met2  ;
    ANTENNAMAXSIDEAREACAR 96.6433 LAYER met2  ;
    ANTENNAMAXCUTCAR 0.407937 LAYER via2  ;
    PORT
      LAYER met2 ;
        RECT 321.240000 0.000000 321.380000 0.485000 ;
    END
  END wbs_adr_i[15]
  PIN wbs_adr_i[14]
    DIRECTION INPUT ;
    USE SIGNAL ;
    ANTENNAPARTIALMETALAREA 4.9247 LAYER met2  ;
    ANTENNAPARTIALMETALSIDEAREA 24.2795 LAYER met2  ;
    ANTENNAMODEL OXIDE1 ;
    ANTENNAGATEAREA 0.3735 LAYER met2  ;
    ANTENNAMAXAREACAR 25.5261 LAYER met2  ;
    ANTENNAMAXSIDEAREACAR 113.787 LAYER met2  ;
    ANTENNAMAXCUTCAR 0.586508 LAYER via2  ;
    PORT
      LAYER met2 ;
        RECT 303.760000 0.000000 303.900000 0.485000 ;
    END
  END wbs_adr_i[14]
  PIN wbs_adr_i[13]
    DIRECTION INPUT ;
    USE SIGNAL ;
    ANTENNAPARTIALMETALAREA 4.8009 LAYER met2  ;
    ANTENNAPARTIALMETALSIDEAREA 23.6705 LAYER met2  ;
    ANTENNAMODEL OXIDE1 ;
    ANTENNAGATEAREA 0.3735 LAYER met2  ;
    ANTENNAMAXAREACAR 16.2748 LAYER met2  ;
    ANTENNAMAXSIDEAREACAR 73.2637 LAYER met2  ;
    ANTENNAMAXCUTCAR 0.407937 LAYER via2  ;
    PORT
      LAYER met2 ;
        RECT 286.280000 0.000000 286.420000 0.485000 ;
    END
  END wbs_adr_i[13]
  PIN wbs_adr_i[12]
    DIRECTION INPUT ;
    USE SIGNAL ;
    ANTENNAPARTIALMETALAREA 5.2775 LAYER met2  ;
    ANTENNAPARTIALMETALSIDEAREA 26.0435 LAYER met2  ;
    ANTENNAMODEL OXIDE1 ;
    ANTENNAGATEAREA 0.3735 LAYER met2  ;
    ANTENNAMAXAREACAR 23.5854 LAYER met2  ;
    ANTENNAMAXSIDEAREACAR 112.343 LAYER met2  ;
    ANTENNAMAXCUTCAR 0.407937 LAYER via2  ;
    PORT
      LAYER met2 ;
        RECT 268.800000 0.000000 268.940000 0.485000 ;
    END
  END wbs_adr_i[12]
  PIN wbs_adr_i[11]
    DIRECTION INPUT ;
    USE SIGNAL ;
    ANTENNAPARTIALMETALAREA 4.5651 LAYER met2  ;
    ANTENNAPARTIALMETALSIDEAREA 22.5995 LAYER met2  ;
    ANTENNAMODEL OXIDE1 ;
    ANTENNAGATEAREA 0.3735 LAYER met2  ;
    ANTENNAMAXAREACAR 19.0315 LAYER met2  ;
    ANTENNAMAXSIDEAREACAR 86.1386 LAYER met2  ;
    ANTENNAMAXCUTCAR 0.289606 LAYER via2  ;
    PORT
      LAYER met2 ;
        RECT 251.320000 0.000000 251.460000 0.485000 ;
    END
  END wbs_adr_i[11]
  PIN wbs_adr_i[10]
    DIRECTION INPUT ;
    USE SIGNAL ;
    ANTENNAPARTIALMETALAREA 4.6603 LAYER met2  ;
    ANTENNAPARTIALMETALSIDEAREA 23.0755 LAYER met2  ;
    ANTENNAMODEL OXIDE1 ;
    ANTENNAGATEAREA 0.3735 LAYER met2  ;
    ANTENNAMAXAREACAR 19.3314 LAYER met2  ;
    ANTENNAMAXSIDEAREACAR 87.638 LAYER met2  ;
    ANTENNAMAXCUTCAR 0.289606 LAYER via2  ;
    PORT
      LAYER met2 ;
        RECT 233.840000 0.000000 233.980000 0.485000 ;
    END
  END wbs_adr_i[10]
  PIN wbs_adr_i[9]
    DIRECTION INPUT ;
    USE SIGNAL ;
    ANTENNAPARTIALMETALAREA 5.0843 LAYER met2  ;
    ANTENNAPARTIALMETALSIDEAREA 25.0775 LAYER met2  ;
    ANTENNAMODEL OXIDE1 ;
    ANTENNAGATEAREA 0.3735 LAYER met2  ;
    ANTENNAMAXAREACAR 28.2086 LAYER met2  ;
    ANTENNAMAXSIDEAREACAR 125.884 LAYER met2  ;
    ANTENNAMAXCUTCAR 0.407937 LAYER via2  ;
    PORT
      LAYER met2 ;
        RECT 216.360000 0.000000 216.500000 0.485000 ;
    END
  END wbs_adr_i[9]
  PIN wbs_adr_i[8]
    DIRECTION INPUT ;
    USE SIGNAL ;
    ANTENNAPARTIALMETALAREA 4.6504 LAYER met2  ;
    ANTENNAPARTIALMETALSIDEAREA 22.855 LAYER met2  ;
    ANTENNAMODEL OXIDE1 ;
    ANTENNAGATEAREA 0.2475 LAYER met2  ;
    ANTENNAMAXAREACAR 21.6715 LAYER met2  ;
    ANTENNAMAXSIDEAREACAR 101.883 LAYER met2  ;
    ANTENNAPARTIALCUTAREA 0.04 LAYER via2  ;
    ANTENNAMAXCUTCAR 0.57697 LAYER via2  ;
    ANTENNAPARTIALMETALAREA 2.7408 LAYER met3  ;
    ANTENNAPARTIALMETALSIDEAREA 15.088 LAYER met3  ;
    ANTENNAGATEAREA 0.3735 LAYER met3  ;
    ANTENNAMAXAREACAR 29.0097 LAYER met3  ;
    ANTENNAMAXSIDEAREACAR 142.279 LAYER met3  ;
    ANTENNAMAXCUTCAR 0.725397 LAYER via3  ;
    PORT
      LAYER met2 ;
        RECT 198.880000 0.000000 199.020000 0.485000 ;
    END
  END wbs_adr_i[8]
  PIN wbs_adr_i[7]
    DIRECTION INPUT ;
    USE SIGNAL ;
    ANTENNAPARTIALMETALAREA 5.0852 LAYER met2  ;
    ANTENNAPARTIALMETALSIDEAREA 25.039 LAYER met2  ;
    ANTENNAMODEL OXIDE1 ;
    ANTENNAGATEAREA 0.2475 LAYER met2  ;
    ANTENNAMAXAREACAR 22.6441 LAYER met2  ;
    ANTENNAMAXSIDEAREACAR 105.117 LAYER met2  ;
    ANTENNAPARTIALCUTAREA 0.04 LAYER via2  ;
    ANTENNAMAXCUTCAR 0.369293 LAYER via2  ;
    ANTENNAPARTIALMETALAREA 2.8788 LAYER met3  ;
    ANTENNAPARTIALMETALSIDEAREA 15.824 LAYER met3  ;
    ANTENNAGATEAREA 0.3735 LAYER met3  ;
    ANTENNAMAXAREACAR 30.3518 LAYER met3  ;
    ANTENNAMAXSIDEAREACAR 147.484 LAYER met3  ;
    ANTENNAMAXCUTCAR 0.725397 LAYER via3  ;
    PORT
      LAYER met2 ;
        RECT 181.400000 0.000000 181.540000 0.485000 ;
    END
  END wbs_adr_i[7]
  PIN wbs_adr_i[6]
    DIRECTION INPUT ;
    USE SIGNAL ;
    ANTENNAPARTIALMETALAREA 6.0363 LAYER met2  ;
    ANTENNAPARTIALMETALSIDEAREA 29.8375 LAYER met2  ;
    ANTENNAMODEL OXIDE1 ;
    ANTENNAGATEAREA 0.3735 LAYER met2  ;
    ANTENNAMAXAREACAR 19.5825 LAYER met2  ;
    ANTENNAMAXSIDEAREACAR 88.4175 LAYER met2  ;
    ANTENNAMAXCUTCAR 0.407937 LAYER via2  ;
    PORT
      LAYER met2 ;
        RECT 163.920000 0.000000 164.060000 0.485000 ;
    END
  END wbs_adr_i[6]
  PIN wbs_adr_i[5]
    DIRECTION INPUT ;
    USE SIGNAL ;
    ANTENNAPARTIALMETALAREA 5.2727 LAYER met2  ;
    ANTENNAPARTIALMETALSIDEAREA 26.0295 LAYER met2  ;
    ANTENNAMODEL OXIDE1 ;
    ANTENNAGATEAREA 0.3735 LAYER met2  ;
    ANTENNAMAXAREACAR 17.142 LAYER met2  ;
    ANTENNAMAXSIDEAREACAR 76.7106 LAYER met2  ;
    ANTENNAMAXCUTCAR 0.407937 LAYER via2  ;
    PORT
      LAYER met2 ;
        RECT 146.440000 0.000000 146.580000 0.485000 ;
    END
  END wbs_adr_i[5]
  PIN wbs_adr_i[4]
    DIRECTION INPUT ;
    USE SIGNAL ;
    ANTENNAPARTIALMETALAREA 4.7967 LAYER met2  ;
    ANTENNAPARTIALMETALSIDEAREA 23.6495 LAYER met2  ;
    ANTENNAMODEL OXIDE1 ;
    ANTENNAGATEAREA 0.3735 LAYER met2  ;
    ANTENNAMAXAREACAR 18.2342 LAYER met2  ;
    ANTENNAMAXSIDEAREACAR 78.2115 LAYER met2  ;
    ANTENNAMAXCUTCAR 0.407937 LAYER via2  ;
    PORT
      LAYER met2 ;
        RECT 128.960000 0.000000 129.100000 0.485000 ;
    END
  END wbs_adr_i[4]
  PIN wbs_adr_i[3]
    DIRECTION INPUT ;
    USE SIGNAL ;
    ANTENNAPARTIALMETALAREA 5.1131 LAYER met2  ;
    ANTENNAPARTIALMETALSIDEAREA 25.2315 LAYER met2  ;
    ANTENNAMODEL OXIDE1 ;
    ANTENNAGATEAREA 0.3735 LAYER met2  ;
    ANTENNAMAXAREACAR 26.2937 LAYER met2  ;
    ANTENNAMAXSIDEAREACAR 118.09 LAYER met2  ;
    ANTENNAMAXCUTCAR 0.407937 LAYER via2  ;
    PORT
      LAYER met2 ;
        RECT 105.500000 0.000000 105.640000 0.485000 ;
    END
  END wbs_adr_i[3]
  PIN wbs_adr_i[2]
    DIRECTION INPUT ;
    USE SIGNAL ;
    ANTENNAPARTIALMETALAREA 6.4507 LAYER met2  ;
    ANTENNAPARTIALMETALSIDEAREA 31.9095 LAYER met2  ;
    ANTENNAMODEL OXIDE1 ;
    ANTENNAGATEAREA 0.378 LAYER met2  ;
    ANTENNAMAXAREACAR 30.936 LAYER met2  ;
    ANTENNAMAXSIDEAREACAR 143.018 LAYER met2  ;
    ANTENNAMAXCUTCAR 0.407937 LAYER via2  ;
    PORT
      LAYER met2 ;
        RECT 82.040000 0.000000 82.180000 0.485000 ;
    END
  END wbs_adr_i[2]
  PIN wbs_adr_i[1]
    DIRECTION INPUT ;
    USE SIGNAL ;
    ANTENNAPARTIALMETALAREA 5.0319 LAYER met2  ;
    ANTENNAPARTIALMETALSIDEAREA 24.8255 LAYER met2  ;
    ANTENNAMODEL OXIDE1 ;
    ANTENNAGATEAREA 0.3735 LAYER met2  ;
    ANTENNAMAXAREACAR 16.4167 LAYER met2  ;
    ANTENNAMAXSIDEAREACAR 76.5267 LAYER met2  ;
    ANTENNAMAXCUTCAR 0.407937 LAYER via2  ;
    PORT
      LAYER met2 ;
        RECT 58.580000 0.000000 58.720000 0.485000 ;
    END
  END wbs_adr_i[1]
  PIN wbs_adr_i[0]
    DIRECTION INPUT ;
    USE SIGNAL ;
    ANTENNAPARTIALMETALAREA 5.5751 LAYER met2  ;
    ANTENNAPARTIALMETALSIDEAREA 27.5415 LAYER met2  ;
    ANTENNAMODEL OXIDE1 ;
    ANTENNAGATEAREA 0.3735 LAYER met2  ;
    ANTENNAMAXAREACAR 20.8294 LAYER met2  ;
    ANTENNAMAXSIDEAREACAR 91.1874 LAYER met2  ;
    ANTENNAMAXCUTCAR 0.407937 LAYER via2  ;
    PORT
      LAYER met2 ;
        RECT 35.580000 0.000000 35.720000 0.485000 ;
    END
  END wbs_adr_i[0]
  PIN wbs_ack_o
    DIRECTION OUTPUT ;
    USE SIGNAL ;
    ANTENNADIFFAREA 0.429 LAYER met2  ;
    ANTENNAPARTIALMETALAREA 6.3857 LAYER met2  ;
    ANTENNAPARTIALMETALSIDEAREA 31.5945 LAYER met2  ;
    ANTENNAMODEL OXIDE1 ;
    ANTENNAGATEAREA 0.1965 LAYER met2  ;
    ANTENNAMAXAREACAR 39.8056 LAYER met2  ;
    ANTENNAMAXSIDEAREACAR 194.539 LAYER met2  ;
    ANTENNAMAXCUTCAR 0.261578 LAYER via2  ;
    PORT
      LAYER met2 ;
        RECT 12.120000 0.000000 12.260000 0.485000 ;
    END
  END wbs_ack_o
  PIN wbs_dat_o[31]
    DIRECTION OUTPUT ;
    USE SIGNAL ;
    ANTENNADIFFAREA 0.47025 LAYER met2  ;
    ANTENNAPARTIALMETALAREA 4.6367 LAYER met2  ;
    ANTENNAPARTIALMETALSIDEAREA 23.0755 LAYER met2  ;
    PORT
      LAYER met2 ;
        RECT 612.880000 0.000000 613.020000 0.485000 ;
    END
  END wbs_dat_o[31]
  PIN wbs_dat_o[30]
    DIRECTION OUTPUT ;
    USE SIGNAL ;
    ANTENNADIFFAREA 0.47025 LAYER met2  ;
    ANTENNAPARTIALMETALAREA 4.4953 LAYER met2  ;
    ANTENNAPARTIALMETALSIDEAREA 22.3685 LAYER met2  ;
    PORT
      LAYER met2 ;
        RECT 595.400000 0.000000 595.540000 0.485000 ;
    END
  END wbs_dat_o[30]
  PIN wbs_dat_o[29]
    DIRECTION OUTPUT ;
    USE SIGNAL ;
    ANTENNADIFFAREA 0.47025 LAYER met2  ;
    ANTENNAPARTIALMETALAREA 4.9839 LAYER met2  ;
    ANTENNAPARTIALMETALSIDEAREA 24.8115 LAYER met2  ;
    PORT
      LAYER met2 ;
        RECT 577.920000 0.000000 578.060000 0.485000 ;
    END
  END wbs_dat_o[29]
  PIN wbs_dat_o[28]
    DIRECTION OUTPUT ;
    USE SIGNAL ;
    ANTENNADIFFAREA 0.47025 LAYER met2  ;
    ANTENNAPARTIALMETALAREA 5.1295 LAYER met2  ;
    ANTENNAPARTIALMETALSIDEAREA 25.5395 LAYER met2  ;
    PORT
      LAYER met2 ;
        RECT 560.440000 0.000000 560.580000 0.485000 ;
    END
  END wbs_dat_o[28]
  PIN wbs_dat_o[27]
    DIRECTION OUTPUT ;
    USE SIGNAL ;
    ANTENNADIFFAREA 0.47025 LAYER met2  ;
    ANTENNAPARTIALMETALAREA 4.7149 LAYER met2  ;
    ANTENNAPARTIALMETALSIDEAREA 23.3485 LAYER met2  ;
    PORT
      LAYER met2 ;
        RECT 542.960000 0.000000 543.100000 0.485000 ;
    END
  END wbs_dat_o[27]
  PIN wbs_dat_o[26]
    DIRECTION OUTPUT ;
    USE SIGNAL ;
    ANTENNADIFFAREA 0.47025 LAYER met2  ;
    ANTENNAPARTIALMETALAREA 4.0627 LAYER met2  ;
    ANTENNAPARTIALMETALSIDEAREA 20.2055 LAYER met2  ;
    PORT
      LAYER met2 ;
        RECT 525.480000 0.000000 525.620000 0.485000 ;
    END
  END wbs_dat_o[26]
  PIN wbs_dat_o[25]
    DIRECTION OUTPUT ;
    USE SIGNAL ;
    ANTENNADIFFAREA 0.47025 LAYER met2  ;
    ANTENNAPARTIALMETALAREA 5.3743 LAYER met2  ;
    ANTENNAPARTIALMETALSIDEAREA 26.6455 LAYER met2  ;
    PORT
      LAYER met2 ;
        RECT 508.000000 0.000000 508.140000 0.485000 ;
    END
  END wbs_dat_o[25]
  PIN wbs_dat_o[24]
    DIRECTION OUTPUT ;
    USE SIGNAL ;
    ANTENNADIFFAREA 0.47025 LAYER met2  ;
    ANTENNAPARTIALMETALAREA 4.1367 LAYER met2  ;
    ANTENNAPARTIALMETALSIDEAREA 20.4575 LAYER met2  ;
    PORT
      LAYER met2 ;
        RECT 490.520000 0.000000 490.660000 0.485000 ;
    END
  END wbs_dat_o[24]
  PIN wbs_dat_o[23]
    DIRECTION OUTPUT ;
    USE SIGNAL ;
    ANTENNADIFFAREA 0.47025 LAYER met2  ;
    ANTENNAPARTIALMETALAREA 4.2655 LAYER met2  ;
    ANTENNAPARTIALMETALSIDEAREA 21.1015 LAYER met2  ;
    PORT
      LAYER met2 ;
        RECT 473.040000 0.000000 473.180000 0.485000 ;
    END
  END wbs_dat_o[23]
  PIN wbs_dat_o[22]
    DIRECTION OUTPUT ;
    USE SIGNAL ;
    ANTENNADIFFAREA 0.47025 LAYER met2  ;
    ANTENNAPARTIALMETALAREA 5.5719 LAYER met2  ;
    ANTENNAPARTIALMETALSIDEAREA 27.7515 LAYER met2  ;
    PORT
      LAYER met2 ;
        RECT 455.560000 0.000000 455.700000 0.485000 ;
    END
  END wbs_dat_o[22]
  PIN wbs_dat_o[21]
    DIRECTION OUTPUT ;
    USE SIGNAL ;
    ANTENNADIFFAREA 0.47025 LAYER met2  ;
    ANTENNAPARTIALMETALAREA 6.3475 LAYER met2  ;
    ANTENNAPARTIALMETALSIDEAREA 31.6295 LAYER met2  ;
    PORT
      LAYER met2 ;
        RECT 438.080000 0.000000 438.220000 0.485000 ;
    END
  END wbs_dat_o[21]
  PIN wbs_dat_o[20]
    DIRECTION OUTPUT ;
    USE SIGNAL ;
    ANTENNADIFFAREA 0.47025 LAYER met2  ;
    ANTENNAPARTIALMETALAREA 5.2035 LAYER met2  ;
    ANTENNAPARTIALMETALSIDEAREA 25.7915 LAYER met2  ;
    PORT
      LAYER met2 ;
        RECT 420.600000 0.000000 420.740000 0.485000 ;
    END
  END wbs_dat_o[20]
  PIN wbs_dat_o[19]
    DIRECTION OUTPUT ;
    USE SIGNAL ;
    ANTENNADIFFAREA 0.47025 LAYER met2  ;
    ANTENNAPARTIALMETALAREA 6.3676 LAYER met2  ;
    ANTENNAPARTIALMETALSIDEAREA 31.612 LAYER met2  ;
    PORT
      LAYER met2 ;
        RECT 403.120000 0.000000 403.260000 0.485000 ;
    END
  END wbs_dat_o[19]
  PIN wbs_dat_o[18]
    DIRECTION OUTPUT ;
    USE SIGNAL ;
    ANTENNADIFFAREA 0.47025 LAYER met2  ;
    ANTENNAPARTIALMETALAREA 6.4957 LAYER met2  ;
    ANTENNAPARTIALMETALSIDEAREA 32.2525 LAYER met2  ;
    PORT
      LAYER met2 ;
        RECT 385.640000 0.000000 385.780000 0.485000 ;
    END
  END wbs_dat_o[18]
  PIN wbs_dat_o[17]
    DIRECTION OUTPUT ;
    USE SIGNAL ;
    ANTENNADIFFAREA 0.47025 LAYER met2  ;
    ANTENNAPARTIALMETALAREA 6.2171 LAYER met2  ;
    ANTENNAPARTIALMETALSIDEAREA 30.8595 LAYER met2  ;
    PORT
      LAYER met2 ;
        RECT 368.160000 0.000000 368.300000 0.485000 ;
    END
  END wbs_dat_o[17]
  PIN wbs_dat_o[16]
    DIRECTION OUTPUT ;
    USE SIGNAL ;
    ANTENNADIFFAREA 0.47025 LAYER met2  ;
    ANTENNAPARTIALMETALAREA 4.8789 LAYER met2  ;
    ANTENNAPARTIALMETALSIDEAREA 24.2865 LAYER met2  ;
    PORT
      LAYER met2 ;
        RECT 350.680000 0.000000 350.820000 0.485000 ;
    END
  END wbs_dat_o[16]
  PIN wbs_dat_o[15]
    DIRECTION OUTPUT ;
    USE SIGNAL ;
    ANTENNADIFFAREA 0.47025 LAYER met2  ;
    ANTENNAPARTIALMETALAREA 4.6367 LAYER met2  ;
    ANTENNAPARTIALMETALSIDEAREA 23.0755 LAYER met2  ;
    PORT
      LAYER met2 ;
        RECT 333.200000 0.000000 333.340000 0.485000 ;
    END
  END wbs_dat_o[15]
  PIN wbs_dat_o[14]
    DIRECTION OUTPUT ;
    USE SIGNAL ;
    ANTENNADIFFAREA 0.47025 LAYER met2  ;
    ANTENNAPARTIALMETALAREA 5.5675 LAYER met2  ;
    ANTENNAPARTIALMETALSIDEAREA 27.6115 LAYER met2  ;
    PORT
      LAYER met2 ;
        RECT 315.720000 0.000000 315.860000 0.485000 ;
    END
  END wbs_dat_o[14]
  PIN wbs_dat_o[13]
    DIRECTION OUTPUT ;
    USE SIGNAL ;
    ANTENNADIFFAREA 0.47025 LAYER met2  ;
    ANTENNAPARTIALMETALAREA 5.0579 LAYER met2  ;
    ANTENNAPARTIALMETALSIDEAREA 25.0635 LAYER met2  ;
    PORT
      LAYER met2 ;
        RECT 297.780000 0.000000 297.920000 0.485000 ;
    END
  END wbs_dat_o[13]
  PIN wbs_dat_o[12]
    DIRECTION OUTPUT ;
    USE SIGNAL ;
    ANTENNADIFFAREA 0.47025 LAYER met2  ;
    ANTENNAPARTIALMETALAREA 7.1815 LAYER met2  ;
    ANTENNAPARTIALMETALSIDEAREA 35.5635 LAYER met2  ;
    PORT
      LAYER met2 ;
        RECT 280.300000 0.000000 280.440000 0.485000 ;
    END
  END wbs_dat_o[12]
  PIN wbs_dat_o[11]
    DIRECTION OUTPUT ;
    USE SIGNAL ;
    ANTENNAPARTIALMETALAREA 0.189 LAYER met2  ;
    ANTENNAPARTIALMETALSIDEAREA 0.784 LAYER met2  ;
    ANTENNAPARTIALCUTAREA 0.04 LAYER via2  ;
    ANTENNADIFFAREA 0.47025 LAYER met3  ;
    ANTENNAPARTIALMETALAREA 22.1988 LAYER met3  ;
    ANTENNAPARTIALMETALSIDEAREA 118.864 LAYER met3  ;
    PORT
      LAYER met2 ;
        RECT 262.820000 0.000000 262.960000 0.485000 ;
    END
  END wbs_dat_o[11]
  PIN wbs_dat_o[10]
    DIRECTION OUTPUT ;
    USE SIGNAL ;
    ANTENNADIFFAREA 0.47025 LAYER met2  ;
    ANTENNAPARTIALMETALAREA 7.0935 LAYER met2  ;
    ANTENNAPARTIALMETALSIDEAREA 35.2415 LAYER met2  ;
    PORT
      LAYER met2 ;
        RECT 245.340000 0.000000 245.480000 0.485000 ;
    END
  END wbs_dat_o[10]
  PIN wbs_dat_o[9]
    DIRECTION OUTPUT ;
    USE SIGNAL ;
    ANTENNADIFFAREA 0.47025 LAYER met2  ;
    ANTENNAPARTIALMETALAREA 7.8691 LAYER met2  ;
    ANTENNAPARTIALMETALSIDEAREA 39.1195 LAYER met2  ;
    PORT
      LAYER met2 ;
        RECT 227.860000 0.000000 228.000000 0.485000 ;
    END
  END wbs_dat_o[9]
  PIN wbs_dat_o[8]
    DIRECTION OUTPUT ;
    USE SIGNAL ;
    ANTENNADIFFAREA 0.47025 LAYER met2  ;
    ANTENNAPARTIALMETALAREA 6.8023 LAYER met2  ;
    ANTENNAPARTIALMETALSIDEAREA 33.7855 LAYER met2  ;
    PORT
      LAYER met2 ;
        RECT 210.380000 0.000000 210.520000 0.485000 ;
    END
  END wbs_dat_o[8]
  PIN wbs_dat_o[7]
    DIRECTION OUTPUT ;
    USE SIGNAL ;
    ANTENNADIFFAREA 0.47025 LAYER met2  ;
    ANTENNAPARTIALMETALAREA 6.5671 LAYER met2  ;
    ANTENNAPARTIALMETALSIDEAREA 32.6095 LAYER met2  ;
    PORT
      LAYER met2 ;
        RECT 192.900000 0.000000 193.040000 0.485000 ;
    END
  END wbs_dat_o[7]
  PIN wbs_dat_o[6]
    DIRECTION OUTPUT ;
    USE SIGNAL ;
    ANTENNADIFFAREA 0.47025 LAYER met2  ;
    ANTENNAPARTIALMETALAREA 6.3333 LAYER met2  ;
    ANTENNAPARTIALMETALSIDEAREA 31.4405 LAYER met2  ;
    PORT
      LAYER met2 ;
        RECT 175.420000 0.000000 175.560000 0.485000 ;
    END
  END wbs_dat_o[6]
  PIN wbs_dat_o[5]
    DIRECTION OUTPUT ;
    USE SIGNAL ;
    ANTENNADIFFAREA 0.47025 LAYER met2  ;
    ANTENNAPARTIALMETALAREA 7.3329 LAYER met2  ;
    ANTENNAPARTIALMETALSIDEAREA 36.4385 LAYER met2  ;
    PORT
      LAYER met2 ;
        RECT 157.940000 0.000000 158.080000 0.485000 ;
    END
  END wbs_dat_o[5]
  PIN wbs_dat_o[4]
    DIRECTION OUTPUT ;
    USE SIGNAL ;
    ANTENNADIFFAREA 0.47025 LAYER met2  ;
    ANTENNAPARTIALMETALAREA 6.8709 LAYER met2  ;
    ANTENNAPARTIALMETALSIDEAREA 34.1285 LAYER met2  ;
    PORT
      LAYER met2 ;
        RECT 140.460000 0.000000 140.600000 0.485000 ;
    END
  END wbs_dat_o[4]
  PIN wbs_dat_o[3]
    DIRECTION OUTPUT ;
    USE SIGNAL ;
    ANTENNADIFFAREA 0.47025 LAYER met2  ;
    ANTENNAPARTIALMETALAREA 8.5887 LAYER met2  ;
    ANTENNAPARTIALMETALSIDEAREA 42.7175 LAYER met2  ;
    PORT
      LAYER met2 ;
        RECT 117.000000 0.000000 117.140000 0.485000 ;
    END
  END wbs_dat_o[3]
  PIN wbs_dat_o[2]
    DIRECTION OUTPUT ;
    USE SIGNAL ;
    ANTENNADIFFAREA 0.47025 LAYER met2  ;
    ANTENNAPARTIALMETALAREA 9.1571 LAYER met2  ;
    ANTENNAPARTIALMETALSIDEAREA 45.5595 LAYER met2  ;
    PORT
      LAYER met2 ;
        RECT 93.540000 0.000000 93.680000 0.485000 ;
    END
  END wbs_dat_o[2]
  PIN wbs_dat_o[1]
    DIRECTION OUTPUT ;
    USE SIGNAL ;
    ANTENNADIFFAREA 0.47025 LAYER met2  ;
    ANTENNAPARTIALMETALAREA 6.9675 LAYER met2  ;
    ANTENNAPARTIALMETALSIDEAREA 34.6115 LAYER met2  ;
    PORT
      LAYER met2 ;
        RECT 70.540000 0.000000 70.680000 0.485000 ;
    END
  END wbs_dat_o[1]
  PIN wbs_dat_o[0]
    DIRECTION OUTPUT ;
    USE SIGNAL ;
    ANTENNADIFFAREA 0.47025 LAYER met2  ;
    ANTENNAPARTIALMETALAREA 7.3763 LAYER met2  ;
    ANTENNAPARTIALMETALSIDEAREA 36.6555 LAYER met2  ;
    PORT
      LAYER met2 ;
        RECT 47.080000 0.000000 47.220000 0.485000 ;
    END
  END wbs_dat_o[0]
  PIN la_data_in[127]
    DIRECTION INPUT ;
    USE SIGNAL ;
    PORT
      LAYER met2 ;
        RECT 2842.040000 0.000000 2842.180000 0.485000 ;
    END
  END la_data_in[127]
  PIN la_data_in[126]
    DIRECTION INPUT ;
    USE SIGNAL ;
    PORT
      LAYER met2 ;
        RECT 2824.560000 0.000000 2824.700000 0.485000 ;
    END
  END la_data_in[126]
  PIN la_data_in[125]
    DIRECTION INPUT ;
    USE SIGNAL ;
    PORT
      LAYER met2 ;
        RECT 2807.080000 0.000000 2807.220000 0.485000 ;
    END
  END la_data_in[125]
  PIN la_data_in[124]
    DIRECTION INPUT ;
    USE SIGNAL ;
    PORT
      LAYER met2 ;
        RECT 2789.600000 0.000000 2789.740000 0.485000 ;
    END
  END la_data_in[124]
  PIN la_data_in[123]
    DIRECTION INPUT ;
    USE SIGNAL ;
    PORT
      LAYER met2 ;
        RECT 2772.120000 0.000000 2772.260000 0.485000 ;
    END
  END la_data_in[123]
  PIN la_data_in[122]
    DIRECTION INPUT ;
    USE SIGNAL ;
    PORT
      LAYER met2 ;
        RECT 2754.640000 0.000000 2754.780000 0.485000 ;
    END
  END la_data_in[122]
  PIN la_data_in[121]
    DIRECTION INPUT ;
    USE SIGNAL ;
    PORT
      LAYER met2 ;
        RECT 2737.160000 0.000000 2737.300000 0.485000 ;
    END
  END la_data_in[121]
  PIN la_data_in[120]
    DIRECTION INPUT ;
    USE SIGNAL ;
    PORT
      LAYER met2 ;
        RECT 2719.680000 0.000000 2719.820000 0.485000 ;
    END
  END la_data_in[120]
  PIN la_data_in[119]
    DIRECTION INPUT ;
    USE SIGNAL ;
    PORT
      LAYER met2 ;
        RECT 2702.200000 0.000000 2702.340000 0.485000 ;
    END
  END la_data_in[119]
  PIN la_data_in[118]
    DIRECTION INPUT ;
    USE SIGNAL ;
    PORT
      LAYER met2 ;
        RECT 2684.720000 0.000000 2684.860000 0.485000 ;
    END
  END la_data_in[118]
  PIN la_data_in[117]
    DIRECTION INPUT ;
    USE SIGNAL ;
    PORT
      LAYER met2 ;
        RECT 2667.240000 0.000000 2667.380000 0.485000 ;
    END
  END la_data_in[117]
  PIN la_data_in[116]
    DIRECTION INPUT ;
    USE SIGNAL ;
    PORT
      LAYER met2 ;
        RECT 2649.760000 0.000000 2649.900000 0.485000 ;
    END
  END la_data_in[116]
  PIN la_data_in[115]
    DIRECTION INPUT ;
    USE SIGNAL ;
    PORT
      LAYER met2 ;
        RECT 2632.280000 0.000000 2632.420000 0.485000 ;
    END
  END la_data_in[115]
  PIN la_data_in[114]
    DIRECTION INPUT ;
    USE SIGNAL ;
    PORT
      LAYER met2 ;
        RECT 2614.800000 0.000000 2614.940000 0.485000 ;
    END
  END la_data_in[114]
  PIN la_data_in[113]
    DIRECTION INPUT ;
    USE SIGNAL ;
    PORT
      LAYER met2 ;
        RECT 2597.320000 0.000000 2597.460000 0.485000 ;
    END
  END la_data_in[113]
  PIN la_data_in[112]
    DIRECTION INPUT ;
    USE SIGNAL ;
    PORT
      LAYER met2 ;
        RECT 2579.840000 0.000000 2579.980000 0.485000 ;
    END
  END la_data_in[112]
  PIN la_data_in[111]
    DIRECTION INPUT ;
    USE SIGNAL ;
    PORT
      LAYER met2 ;
        RECT 2562.360000 0.000000 2562.500000 0.485000 ;
    END
  END la_data_in[111]
  PIN la_data_in[110]
    DIRECTION INPUT ;
    USE SIGNAL ;
    PORT
      LAYER met2 ;
        RECT 2544.420000 0.000000 2544.560000 0.485000 ;
    END
  END la_data_in[110]
  PIN la_data_in[109]
    DIRECTION INPUT ;
    USE SIGNAL ;
    PORT
      LAYER met2 ;
        RECT 2526.940000 0.000000 2527.080000 0.485000 ;
    END
  END la_data_in[109]
  PIN la_data_in[108]
    DIRECTION INPUT ;
    USE SIGNAL ;
    PORT
      LAYER met2 ;
        RECT 2509.460000 0.000000 2509.600000 0.485000 ;
    END
  END la_data_in[108]
  PIN la_data_in[107]
    DIRECTION INPUT ;
    USE SIGNAL ;
    PORT
      LAYER met2 ;
        RECT 2491.980000 0.000000 2492.120000 0.485000 ;
    END
  END la_data_in[107]
  PIN la_data_in[106]
    DIRECTION INPUT ;
    USE SIGNAL ;
    PORT
      LAYER met2 ;
        RECT 2474.500000 0.000000 2474.640000 0.485000 ;
    END
  END la_data_in[106]
  PIN la_data_in[105]
    DIRECTION INPUT ;
    USE SIGNAL ;
    PORT
      LAYER met2 ;
        RECT 2457.020000 0.000000 2457.160000 0.485000 ;
    END
  END la_data_in[105]
  PIN la_data_in[104]
    DIRECTION INPUT ;
    USE SIGNAL ;
    PORT
      LAYER met2 ;
        RECT 2439.540000 0.000000 2439.680000 0.485000 ;
    END
  END la_data_in[104]
  PIN la_data_in[103]
    DIRECTION INPUT ;
    USE SIGNAL ;
    PORT
      LAYER met2 ;
        RECT 2422.060000 0.000000 2422.200000 0.485000 ;
    END
  END la_data_in[103]
  PIN la_data_in[102]
    DIRECTION INPUT ;
    USE SIGNAL ;
    PORT
      LAYER met2 ;
        RECT 2404.580000 0.000000 2404.720000 0.485000 ;
    END
  END la_data_in[102]
  PIN la_data_in[101]
    DIRECTION INPUT ;
    USE SIGNAL ;
    PORT
      LAYER met2 ;
        RECT 2387.100000 0.000000 2387.240000 0.485000 ;
    END
  END la_data_in[101]
  PIN la_data_in[100]
    DIRECTION INPUT ;
    USE SIGNAL ;
    PORT
      LAYER met2 ;
        RECT 2369.620000 0.000000 2369.760000 0.485000 ;
    END
  END la_data_in[100]
  PIN la_data_in[99]
    DIRECTION INPUT ;
    USE SIGNAL ;
    PORT
      LAYER met2 ;
        RECT 2352.140000 0.000000 2352.280000 0.485000 ;
    END
  END la_data_in[99]
  PIN la_data_in[98]
    DIRECTION INPUT ;
    USE SIGNAL ;
    PORT
      LAYER met2 ;
        RECT 2334.660000 0.000000 2334.800000 0.485000 ;
    END
  END la_data_in[98]
  PIN la_data_in[97]
    DIRECTION INPUT ;
    USE SIGNAL ;
    PORT
      LAYER met2 ;
        RECT 2317.180000 0.000000 2317.320000 0.485000 ;
    END
  END la_data_in[97]
  PIN la_data_in[96]
    DIRECTION INPUT ;
    USE SIGNAL ;
    PORT
      LAYER met2 ;
        RECT 2299.700000 0.000000 2299.840000 0.485000 ;
    END
  END la_data_in[96]
  PIN la_data_in[95]
    DIRECTION INPUT ;
    USE SIGNAL ;
    PORT
      LAYER met2 ;
        RECT 2282.220000 0.000000 2282.360000 0.485000 ;
    END
  END la_data_in[95]
  PIN la_data_in[94]
    DIRECTION INPUT ;
    USE SIGNAL ;
    PORT
      LAYER met2 ;
        RECT 2264.740000 0.000000 2264.880000 0.485000 ;
    END
  END la_data_in[94]
  PIN la_data_in[93]
    DIRECTION INPUT ;
    USE SIGNAL ;
    PORT
      LAYER met2 ;
        RECT 2246.800000 0.000000 2246.940000 0.485000 ;
    END
  END la_data_in[93]
  PIN la_data_in[92]
    DIRECTION INPUT ;
    USE SIGNAL ;
    PORT
      LAYER met2 ;
        RECT 2229.320000 0.000000 2229.460000 0.485000 ;
    END
  END la_data_in[92]
  PIN la_data_in[91]
    DIRECTION INPUT ;
    USE SIGNAL ;
    PORT
      LAYER met2 ;
        RECT 2211.840000 0.000000 2211.980000 0.485000 ;
    END
  END la_data_in[91]
  PIN la_data_in[90]
    DIRECTION INPUT ;
    USE SIGNAL ;
    PORT
      LAYER met2 ;
        RECT 2194.360000 0.000000 2194.500000 0.485000 ;
    END
  END la_data_in[90]
  PIN la_data_in[89]
    DIRECTION INPUT ;
    USE SIGNAL ;
    PORT
      LAYER met2 ;
        RECT 2176.880000 0.000000 2177.020000 0.485000 ;
    END
  END la_data_in[89]
  PIN la_data_in[88]
    DIRECTION INPUT ;
    USE SIGNAL ;
    PORT
      LAYER met2 ;
        RECT 2159.400000 0.000000 2159.540000 0.485000 ;
    END
  END la_data_in[88]
  PIN la_data_in[87]
    DIRECTION INPUT ;
    USE SIGNAL ;
    PORT
      LAYER met2 ;
        RECT 2141.920000 0.000000 2142.060000 0.485000 ;
    END
  END la_data_in[87]
  PIN la_data_in[86]
    DIRECTION INPUT ;
    USE SIGNAL ;
    PORT
      LAYER met2 ;
        RECT 2124.440000 0.000000 2124.580000 0.485000 ;
    END
  END la_data_in[86]
  PIN la_data_in[85]
    DIRECTION INPUT ;
    USE SIGNAL ;
    PORT
      LAYER met2 ;
        RECT 2106.960000 0.000000 2107.100000 0.485000 ;
    END
  END la_data_in[85]
  PIN la_data_in[84]
    DIRECTION INPUT ;
    USE SIGNAL ;
    PORT
      LAYER met2 ;
        RECT 2089.480000 0.000000 2089.620000 0.485000 ;
    END
  END la_data_in[84]
  PIN la_data_in[83]
    DIRECTION INPUT ;
    USE SIGNAL ;
    PORT
      LAYER met2 ;
        RECT 2072.000000 0.000000 2072.140000 0.485000 ;
    END
  END la_data_in[83]
  PIN la_data_in[82]
    DIRECTION INPUT ;
    USE SIGNAL ;
    PORT
      LAYER met2 ;
        RECT 2054.520000 0.000000 2054.660000 0.485000 ;
    END
  END la_data_in[82]
  PIN la_data_in[81]
    DIRECTION INPUT ;
    USE SIGNAL ;
    PORT
      LAYER met2 ;
        RECT 2037.040000 0.000000 2037.180000 0.485000 ;
    END
  END la_data_in[81]
  PIN la_data_in[80]
    DIRECTION INPUT ;
    USE SIGNAL ;
    PORT
      LAYER met2 ;
        RECT 2019.560000 0.000000 2019.700000 0.485000 ;
    END
  END la_data_in[80]
  PIN la_data_in[79]
    DIRECTION INPUT ;
    USE SIGNAL ;
    PORT
      LAYER met2 ;
        RECT 2002.080000 0.000000 2002.220000 0.485000 ;
    END
  END la_data_in[79]
  PIN la_data_in[78]
    DIRECTION INPUT ;
    USE SIGNAL ;
    PORT
      LAYER met2 ;
        RECT 1984.600000 0.000000 1984.740000 0.485000 ;
    END
  END la_data_in[78]
  PIN la_data_in[77]
    DIRECTION INPUT ;
    USE SIGNAL ;
    PORT
      LAYER met2 ;
        RECT 1967.120000 0.000000 1967.260000 0.485000 ;
    END
  END la_data_in[77]
  PIN la_data_in[76]
    DIRECTION INPUT ;
    USE SIGNAL ;
    PORT
      LAYER met2 ;
        RECT 1949.640000 0.000000 1949.780000 0.485000 ;
    END
  END la_data_in[76]
  PIN la_data_in[75]
    DIRECTION INPUT ;
    USE SIGNAL ;
    PORT
      LAYER met2 ;
        RECT 1931.700000 0.000000 1931.840000 0.485000 ;
    END
  END la_data_in[75]
  PIN la_data_in[74]
    DIRECTION INPUT ;
    USE SIGNAL ;
    PORT
      LAYER met2 ;
        RECT 1914.220000 0.000000 1914.360000 0.485000 ;
    END
  END la_data_in[74]
  PIN la_data_in[73]
    DIRECTION INPUT ;
    USE SIGNAL ;
    PORT
      LAYER met2 ;
        RECT 1896.740000 0.000000 1896.880000 0.485000 ;
    END
  END la_data_in[73]
  PIN la_data_in[72]
    DIRECTION INPUT ;
    USE SIGNAL ;
    PORT
      LAYER met2 ;
        RECT 1879.260000 0.000000 1879.400000 0.485000 ;
    END
  END la_data_in[72]
  PIN la_data_in[71]
    DIRECTION INPUT ;
    USE SIGNAL ;
    PORT
      LAYER met2 ;
        RECT 1861.780000 0.000000 1861.920000 0.485000 ;
    END
  END la_data_in[71]
  PIN la_data_in[70]
    DIRECTION INPUT ;
    USE SIGNAL ;
    PORT
      LAYER met2 ;
        RECT 1844.300000 0.000000 1844.440000 0.485000 ;
    END
  END la_data_in[70]
  PIN la_data_in[69]
    DIRECTION INPUT ;
    USE SIGNAL ;
    PORT
      LAYER met2 ;
        RECT 1826.820000 0.000000 1826.960000 0.485000 ;
    END
  END la_data_in[69]
  PIN la_data_in[68]
    DIRECTION INPUT ;
    USE SIGNAL ;
    PORT
      LAYER met2 ;
        RECT 1809.340000 0.000000 1809.480000 0.485000 ;
    END
  END la_data_in[68]
  PIN la_data_in[67]
    DIRECTION INPUT ;
    USE SIGNAL ;
    PORT
      LAYER met2 ;
        RECT 1791.860000 0.000000 1792.000000 0.485000 ;
    END
  END la_data_in[67]
  PIN la_data_in[66]
    DIRECTION INPUT ;
    USE SIGNAL ;
    PORT
      LAYER met2 ;
        RECT 1774.380000 0.000000 1774.520000 0.485000 ;
    END
  END la_data_in[66]
  PIN la_data_in[65]
    DIRECTION INPUT ;
    USE SIGNAL ;
    PORT
      LAYER met2 ;
        RECT 1756.900000 0.000000 1757.040000 0.485000 ;
    END
  END la_data_in[65]
  PIN la_data_in[64]
    DIRECTION INPUT ;
    USE SIGNAL ;
    PORT
      LAYER met2 ;
        RECT 1739.420000 0.000000 1739.560000 0.485000 ;
    END
  END la_data_in[64]
  PIN la_data_in[63]
    DIRECTION INPUT ;
    USE SIGNAL ;
    PORT
      LAYER met2 ;
        RECT 1721.940000 0.000000 1722.080000 0.485000 ;
    END
  END la_data_in[63]
  PIN la_data_in[62]
    DIRECTION INPUT ;
    USE SIGNAL ;
    PORT
      LAYER met2 ;
        RECT 1704.460000 0.000000 1704.600000 0.485000 ;
    END
  END la_data_in[62]
  PIN la_data_in[61]
    DIRECTION INPUT ;
    USE SIGNAL ;
    PORT
      LAYER met2 ;
        RECT 1686.980000 0.000000 1687.120000 0.485000 ;
    END
  END la_data_in[61]
  PIN la_data_in[60]
    DIRECTION INPUT ;
    USE SIGNAL ;
    PORT
      LAYER met2 ;
        RECT 1669.500000 0.000000 1669.640000 0.485000 ;
    END
  END la_data_in[60]
  PIN la_data_in[59]
    DIRECTION INPUT ;
    USE SIGNAL ;
    PORT
      LAYER met2 ;
        RECT 1652.020000 0.000000 1652.160000 0.485000 ;
    END
  END la_data_in[59]
  PIN la_data_in[58]
    DIRECTION INPUT ;
    USE SIGNAL ;
    PORT
      LAYER met2 ;
        RECT 1634.080000 0.000000 1634.220000 0.485000 ;
    END
  END la_data_in[58]
  PIN la_data_in[57]
    DIRECTION INPUT ;
    USE SIGNAL ;
    PORT
      LAYER met2 ;
        RECT 1616.600000 0.000000 1616.740000 0.485000 ;
    END
  END la_data_in[57]
  PIN la_data_in[56]
    DIRECTION INPUT ;
    USE SIGNAL ;
    PORT
      LAYER met2 ;
        RECT 1599.120000 0.000000 1599.260000 0.485000 ;
    END
  END la_data_in[56]
  PIN la_data_in[55]
    DIRECTION INPUT ;
    USE SIGNAL ;
    PORT
      LAYER met2 ;
        RECT 1581.640000 0.000000 1581.780000 0.485000 ;
    END
  END la_data_in[55]
  PIN la_data_in[54]
    DIRECTION INPUT ;
    USE SIGNAL ;
    PORT
      LAYER met2 ;
        RECT 1564.160000 0.000000 1564.300000 0.485000 ;
    END
  END la_data_in[54]
  PIN la_data_in[53]
    DIRECTION INPUT ;
    USE SIGNAL ;
    PORT
      LAYER met2 ;
        RECT 1546.680000 0.000000 1546.820000 0.485000 ;
    END
  END la_data_in[53]
  PIN la_data_in[52]
    DIRECTION INPUT ;
    USE SIGNAL ;
    PORT
      LAYER met2 ;
        RECT 1529.200000 0.000000 1529.340000 0.485000 ;
    END
  END la_data_in[52]
  PIN la_data_in[51]
    DIRECTION INPUT ;
    USE SIGNAL ;
    PORT
      LAYER met2 ;
        RECT 1511.720000 0.000000 1511.860000 0.485000 ;
    END
  END la_data_in[51]
  PIN la_data_in[50]
    DIRECTION INPUT ;
    USE SIGNAL ;
    PORT
      LAYER met2 ;
        RECT 1494.240000 0.000000 1494.380000 0.485000 ;
    END
  END la_data_in[50]
  PIN la_data_in[49]
    DIRECTION INPUT ;
    USE SIGNAL ;
    PORT
      LAYER met2 ;
        RECT 1476.760000 0.000000 1476.900000 0.485000 ;
    END
  END la_data_in[49]
  PIN la_data_in[48]
    DIRECTION INPUT ;
    USE SIGNAL ;
    PORT
      LAYER met2 ;
        RECT 1459.280000 0.000000 1459.420000 0.485000 ;
    END
  END la_data_in[48]
  PIN la_data_in[47]
    DIRECTION INPUT ;
    USE SIGNAL ;
    PORT
      LAYER met2 ;
        RECT 1441.800000 0.000000 1441.940000 0.485000 ;
    END
  END la_data_in[47]
  PIN la_data_in[46]
    DIRECTION INPUT ;
    USE SIGNAL ;
    PORT
      LAYER met2 ;
        RECT 1424.320000 0.000000 1424.460000 0.485000 ;
    END
  END la_data_in[46]
  PIN la_data_in[45]
    DIRECTION INPUT ;
    USE SIGNAL ;
    PORT
      LAYER met2 ;
        RECT 1406.840000 0.000000 1406.980000 0.485000 ;
    END
  END la_data_in[45]
  PIN la_data_in[44]
    DIRECTION INPUT ;
    USE SIGNAL ;
    PORT
      LAYER met2 ;
        RECT 1389.360000 0.000000 1389.500000 0.485000 ;
    END
  END la_data_in[44]
  PIN la_data_in[43]
    DIRECTION INPUT ;
    USE SIGNAL ;
    PORT
      LAYER met2 ;
        RECT 1371.880000 0.000000 1372.020000 0.485000 ;
    END
  END la_data_in[43]
  PIN la_data_in[42]
    DIRECTION INPUT ;
    USE SIGNAL ;
    PORT
      LAYER met2 ;
        RECT 1354.400000 0.000000 1354.540000 0.485000 ;
    END
  END la_data_in[42]
  PIN la_data_in[41]
    DIRECTION INPUT ;
    USE SIGNAL ;
    PORT
      LAYER met2 ;
        RECT 1336.920000 0.000000 1337.060000 0.485000 ;
    END
  END la_data_in[41]
  PIN la_data_in[40]
    DIRECTION INPUT ;
    USE SIGNAL ;
    PORT
      LAYER met2 ;
        RECT 1318.980000 0.000000 1319.120000 0.485000 ;
    END
  END la_data_in[40]
  PIN la_data_in[39]
    DIRECTION INPUT ;
    USE SIGNAL ;
    PORT
      LAYER met2 ;
        RECT 1301.500000 0.000000 1301.640000 0.485000 ;
    END
  END la_data_in[39]
  PIN la_data_in[38]
    DIRECTION INPUT ;
    USE SIGNAL ;
    PORT
      LAYER met2 ;
        RECT 1284.020000 0.000000 1284.160000 0.485000 ;
    END
  END la_data_in[38]
  PIN la_data_in[37]
    DIRECTION INPUT ;
    USE SIGNAL ;
    PORT
      LAYER met2 ;
        RECT 1266.540000 0.000000 1266.680000 0.485000 ;
    END
  END la_data_in[37]
  PIN la_data_in[36]
    DIRECTION INPUT ;
    USE SIGNAL ;
    PORT
      LAYER met2 ;
        RECT 1249.060000 0.000000 1249.200000 0.485000 ;
    END
  END la_data_in[36]
  PIN la_data_in[35]
    DIRECTION INPUT ;
    USE SIGNAL ;
    PORT
      LAYER met2 ;
        RECT 1231.580000 0.000000 1231.720000 0.485000 ;
    END
  END la_data_in[35]
  PIN la_data_in[34]
    DIRECTION INPUT ;
    USE SIGNAL ;
    PORT
      LAYER met2 ;
        RECT 1214.100000 0.000000 1214.240000 0.485000 ;
    END
  END la_data_in[34]
  PIN la_data_in[33]
    DIRECTION INPUT ;
    USE SIGNAL ;
    PORT
      LAYER met2 ;
        RECT 1196.620000 0.000000 1196.760000 0.485000 ;
    END
  END la_data_in[33]
  PIN la_data_in[32]
    DIRECTION INPUT ;
    USE SIGNAL ;
    PORT
      LAYER met2 ;
        RECT 1179.140000 0.000000 1179.280000 0.485000 ;
    END
  END la_data_in[32]
  PIN la_data_in[31]
    DIRECTION INPUT ;
    USE SIGNAL ;
    PORT
      LAYER met2 ;
        RECT 1161.660000 0.000000 1161.800000 0.485000 ;
    END
  END la_data_in[31]
  PIN la_data_in[30]
    DIRECTION INPUT ;
    USE SIGNAL ;
    PORT
      LAYER met2 ;
        RECT 1144.180000 0.000000 1144.320000 0.485000 ;
    END
  END la_data_in[30]
  PIN la_data_in[29]
    DIRECTION INPUT ;
    USE SIGNAL ;
    PORT
      LAYER met2 ;
        RECT 1126.700000 0.000000 1126.840000 0.485000 ;
    END
  END la_data_in[29]
  PIN la_data_in[28]
    DIRECTION INPUT ;
    USE SIGNAL ;
    PORT
      LAYER met2 ;
        RECT 1109.220000 0.000000 1109.360000 0.485000 ;
    END
  END la_data_in[28]
  PIN la_data_in[27]
    DIRECTION INPUT ;
    USE SIGNAL ;
    PORT
      LAYER met2 ;
        RECT 1091.740000 0.000000 1091.880000 0.485000 ;
    END
  END la_data_in[27]
  PIN la_data_in[26]
    DIRECTION INPUT ;
    USE SIGNAL ;
    PORT
      LAYER met2 ;
        RECT 1074.260000 0.000000 1074.400000 0.485000 ;
    END
  END la_data_in[26]
  PIN la_data_in[25]
    DIRECTION INPUT ;
    USE SIGNAL ;
    PORT
      LAYER met2 ;
        RECT 1056.780000 0.000000 1056.920000 0.485000 ;
    END
  END la_data_in[25]
  PIN la_data_in[24]
    DIRECTION INPUT ;
    USE SIGNAL ;
    PORT
      LAYER met2 ;
        RECT 1039.300000 0.000000 1039.440000 0.485000 ;
    END
  END la_data_in[24]
  PIN la_data_in[23]
    DIRECTION INPUT ;
    USE SIGNAL ;
    PORT
      LAYER met2 ;
        RECT 1021.360000 0.000000 1021.500000 0.485000 ;
    END
  END la_data_in[23]
  PIN la_data_in[22]
    DIRECTION INPUT ;
    USE SIGNAL ;
    PORT
      LAYER met2 ;
        RECT 1003.880000 0.000000 1004.020000 0.485000 ;
    END
  END la_data_in[22]
  PIN la_data_in[21]
    DIRECTION INPUT ;
    USE SIGNAL ;
    PORT
      LAYER met2 ;
        RECT 986.400000 0.000000 986.540000 0.485000 ;
    END
  END la_data_in[21]
  PIN la_data_in[20]
    DIRECTION INPUT ;
    USE SIGNAL ;
    PORT
      LAYER met2 ;
        RECT 968.920000 0.000000 969.060000 0.485000 ;
    END
  END la_data_in[20]
  PIN la_data_in[19]
    DIRECTION INPUT ;
    USE SIGNAL ;
    PORT
      LAYER met2 ;
        RECT 951.440000 0.000000 951.580000 0.485000 ;
    END
  END la_data_in[19]
  PIN la_data_in[18]
    DIRECTION INPUT ;
    USE SIGNAL ;
    PORT
      LAYER met2 ;
        RECT 933.960000 0.000000 934.100000 0.485000 ;
    END
  END la_data_in[18]
  PIN la_data_in[17]
    DIRECTION INPUT ;
    USE SIGNAL ;
    PORT
      LAYER met2 ;
        RECT 916.480000 0.000000 916.620000 0.485000 ;
    END
  END la_data_in[17]
  PIN la_data_in[16]
    DIRECTION INPUT ;
    USE SIGNAL ;
    PORT
      LAYER met2 ;
        RECT 899.000000 0.000000 899.140000 0.485000 ;
    END
  END la_data_in[16]
  PIN la_data_in[15]
    DIRECTION INPUT ;
    USE SIGNAL ;
    PORT
      LAYER met2 ;
        RECT 881.520000 0.000000 881.660000 0.485000 ;
    END
  END la_data_in[15]
  PIN la_data_in[14]
    DIRECTION INPUT ;
    USE SIGNAL ;
    PORT
      LAYER met2 ;
        RECT 864.040000 0.000000 864.180000 0.485000 ;
    END
  END la_data_in[14]
  PIN la_data_in[13]
    DIRECTION INPUT ;
    USE SIGNAL ;
    PORT
      LAYER met2 ;
        RECT 846.560000 0.000000 846.700000 0.485000 ;
    END
  END la_data_in[13]
  PIN la_data_in[12]
    DIRECTION INPUT ;
    USE SIGNAL ;
    PORT
      LAYER met2 ;
        RECT 829.080000 0.000000 829.220000 0.485000 ;
    END
  END la_data_in[12]
  PIN la_data_in[11]
    DIRECTION INPUT ;
    USE SIGNAL ;
    PORT
      LAYER met2 ;
        RECT 811.600000 0.000000 811.740000 0.485000 ;
    END
  END la_data_in[11]
  PIN la_data_in[10]
    DIRECTION INPUT ;
    USE SIGNAL ;
    PORT
      LAYER met2 ;
        RECT 794.120000 0.000000 794.260000 0.485000 ;
    END
  END la_data_in[10]
  PIN la_data_in[9]
    DIRECTION INPUT ;
    USE SIGNAL ;
    PORT
      LAYER met2 ;
        RECT 776.640000 0.000000 776.780000 0.485000 ;
    END
  END la_data_in[9]
  PIN la_data_in[8]
    DIRECTION INPUT ;
    USE SIGNAL ;
    PORT
      LAYER met2 ;
        RECT 759.160000 0.000000 759.300000 0.485000 ;
    END
  END la_data_in[8]
  PIN la_data_in[7]
    DIRECTION INPUT ;
    USE SIGNAL ;
    PORT
      LAYER met2 ;
        RECT 741.680000 0.000000 741.820000 0.485000 ;
    END
  END la_data_in[7]
  PIN la_data_in[6]
    DIRECTION INPUT ;
    USE SIGNAL ;
    PORT
      LAYER met2 ;
        RECT 724.200000 0.000000 724.340000 0.485000 ;
    END
  END la_data_in[6]
  PIN la_data_in[5]
    DIRECTION INPUT ;
    USE SIGNAL ;
    PORT
      LAYER met2 ;
        RECT 706.260000 0.000000 706.400000 0.485000 ;
    END
  END la_data_in[5]
  PIN la_data_in[4]
    DIRECTION INPUT ;
    USE SIGNAL ;
    PORT
      LAYER met2 ;
        RECT 688.780000 0.000000 688.920000 0.485000 ;
    END
  END la_data_in[4]
  PIN la_data_in[3]
    DIRECTION INPUT ;
    USE SIGNAL ;
    PORT
      LAYER met2 ;
        RECT 671.300000 0.000000 671.440000 0.485000 ;
    END
  END la_data_in[3]
  PIN la_data_in[2]
    DIRECTION INPUT ;
    USE SIGNAL ;
    PORT
      LAYER met2 ;
        RECT 653.820000 0.000000 653.960000 0.485000 ;
    END
  END la_data_in[2]
  PIN la_data_in[1]
    DIRECTION INPUT ;
    USE SIGNAL ;
    PORT
      LAYER met2 ;
        RECT 636.340000 0.000000 636.480000 0.485000 ;
    END
  END la_data_in[1]
  PIN la_data_in[0]
    DIRECTION INPUT ;
    USE SIGNAL ;
    PORT
      LAYER met2 ;
        RECT 618.860000 0.000000 619.000000 0.485000 ;
    END
  END la_data_in[0]
  PIN la_data_out[127]
    DIRECTION OUTPUT ;
    USE SIGNAL ;
    ANTENNADIFFAREA 0.336 LAYER met2  ;
    ANTENNAPARTIALMETALAREA 4.0627 LAYER met2  ;
    ANTENNAPARTIALMETALSIDEAREA 20.2055 LAYER met2  ;
    PORT
      LAYER met2 ;
        RECT 2848.020000 0.000000 2848.160000 0.485000 ;
    END
  END la_data_out[127]
  PIN la_data_out[126]
    DIRECTION OUTPUT ;
    USE SIGNAL ;
    ANTENNADIFFAREA 0.336 LAYER met2  ;
    ANTENNAPARTIALMETALAREA 4.4435 LAYER met2  ;
    ANTENNAPARTIALMETALSIDEAREA 22.1095 LAYER met2  ;
    PORT
      LAYER met2 ;
        RECT 2830.540000 0.000000 2830.680000 0.485000 ;
    END
  END la_data_out[126]
  PIN la_data_out[125]
    DIRECTION OUTPUT ;
    USE SIGNAL ;
    ANTENNADIFFAREA 0.336 LAYER met2  ;
    ANTENNAPARTIALMETALAREA 4.5079 LAYER met2  ;
    ANTENNAPARTIALMETALSIDEAREA 22.4315 LAYER met2  ;
    PORT
      LAYER met2 ;
        RECT 2813.060000 0.000000 2813.200000 0.485000 ;
    END
  END la_data_out[125]
  PIN la_data_out[124]
    DIRECTION OUTPUT ;
    USE SIGNAL ;
    ANTENNADIFFAREA 0.336 LAYER met2  ;
    ANTENNAPARTIALMETALAREA 4.4435 LAYER met2  ;
    ANTENNAPARTIALMETALSIDEAREA 22.1095 LAYER met2  ;
    PORT
      LAYER met2 ;
        RECT 2795.580000 0.000000 2795.720000 0.485000 ;
    END
  END la_data_out[124]
  PIN la_data_out[123]
    DIRECTION OUTPUT ;
    USE SIGNAL ;
    ANTENNADIFFAREA 0.336 LAYER met2  ;
    ANTENNAPARTIALMETALAREA 4.0627 LAYER met2  ;
    ANTENNAPARTIALMETALSIDEAREA 20.2055 LAYER met2  ;
    PORT
      LAYER met2 ;
        RECT 2778.100000 0.000000 2778.240000 0.485000 ;
    END
  END la_data_out[123]
  PIN la_data_out[122]
    DIRECTION OUTPUT ;
    USE SIGNAL ;
    ANTENNADIFFAREA 0.336 LAYER met2  ;
    ANTENNAPARTIALMETALAREA 4.4435 LAYER met2  ;
    ANTENNAPARTIALMETALSIDEAREA 22.1095 LAYER met2  ;
    PORT
      LAYER met2 ;
        RECT 2760.620000 0.000000 2760.760000 0.485000 ;
    END
  END la_data_out[122]
  PIN la_data_out[121]
    DIRECTION OUTPUT ;
    USE SIGNAL ;
    ANTENNADIFFAREA 0.336 LAYER met2  ;
    ANTENNAPARTIALMETALAREA 4.4435 LAYER met2  ;
    ANTENNAPARTIALMETALSIDEAREA 22.1095 LAYER met2  ;
    PORT
      LAYER met2 ;
        RECT 2743.140000 0.000000 2743.280000 0.485000 ;
    END
  END la_data_out[121]
  PIN la_data_out[120]
    DIRECTION OUTPUT ;
    USE SIGNAL ;
    ANTENNADIFFAREA 0.336 LAYER met2  ;
    ANTENNAPARTIALMETALAREA 4.4435 LAYER met2  ;
    ANTENNAPARTIALMETALSIDEAREA 22.1095 LAYER met2  ;
    PORT
      LAYER met2 ;
        RECT 2725.660000 0.000000 2725.800000 0.485000 ;
    END
  END la_data_out[120]
  PIN la_data_out[119]
    DIRECTION OUTPUT ;
    USE SIGNAL ;
    ANTENNADIFFAREA 0.336 LAYER met2  ;
    ANTENNAPARTIALMETALAREA 4.0627 LAYER met2  ;
    ANTENNAPARTIALMETALSIDEAREA 20.2055 LAYER met2  ;
    PORT
      LAYER met2 ;
        RECT 2708.180000 0.000000 2708.320000 0.485000 ;
    END
  END la_data_out[119]
  PIN la_data_out[118]
    DIRECTION OUTPUT ;
    USE SIGNAL ;
    ANTENNADIFFAREA 0.336 LAYER met2  ;
    ANTENNAPARTIALMETALAREA 4.4435 LAYER met2  ;
    ANTENNAPARTIALMETALSIDEAREA 22.1095 LAYER met2  ;
    PORT
      LAYER met2 ;
        RECT 2690.700000 0.000000 2690.840000 0.485000 ;
    END
  END la_data_out[118]
  PIN la_data_out[117]
    DIRECTION OUTPUT ;
    USE SIGNAL ;
    ANTENNADIFFAREA 0.336 LAYER met2  ;
    ANTENNAPARTIALMETALAREA 4.4435 LAYER met2  ;
    ANTENNAPARTIALMETALSIDEAREA 22.1095 LAYER met2  ;
    PORT
      LAYER met2 ;
        RECT 2673.220000 0.000000 2673.360000 0.485000 ;
    END
  END la_data_out[117]
  PIN la_data_out[116]
    DIRECTION OUTPUT ;
    USE SIGNAL ;
    ANTENNADIFFAREA 0.336 LAYER met2  ;
    ANTENNAPARTIALMETALAREA 4.5079 LAYER met2  ;
    ANTENNAPARTIALMETALSIDEAREA 22.4315 LAYER met2  ;
    PORT
      LAYER met2 ;
        RECT 2655.280000 0.000000 2655.420000 0.485000 ;
    END
  END la_data_out[116]
  PIN la_data_out[115]
    DIRECTION OUTPUT ;
    USE SIGNAL ;
    ANTENNADIFFAREA 0.336 LAYER met2  ;
    ANTENNAPARTIALMETALAREA 4.6367 LAYER met2  ;
    ANTENNAPARTIALMETALSIDEAREA 23.0755 LAYER met2  ;
    PORT
      LAYER met2 ;
        RECT 2637.800000 0.000000 2637.940000 0.485000 ;
    END
  END la_data_out[115]
  PIN la_data_out[114]
    DIRECTION OUTPUT ;
    USE SIGNAL ;
    ANTENNADIFFAREA 0.336 LAYER met2  ;
    ANTENNAPARTIALMETALAREA 4.0627 LAYER met2  ;
    ANTENNAPARTIALMETALSIDEAREA 20.2055 LAYER met2  ;
    PORT
      LAYER met2 ;
        RECT 2620.320000 0.000000 2620.460000 0.485000 ;
    END
  END la_data_out[114]
  PIN la_data_out[113]
    DIRECTION OUTPUT ;
    USE SIGNAL ;
    ANTENNADIFFAREA 0.336 LAYER met2  ;
    ANTENNAPARTIALMETALAREA 4.0627 LAYER met2  ;
    ANTENNAPARTIALMETALSIDEAREA 20.2055 LAYER met2  ;
    PORT
      LAYER met2 ;
        RECT 2602.840000 0.000000 2602.980000 0.485000 ;
    END
  END la_data_out[113]
  PIN la_data_out[112]
    DIRECTION OUTPUT ;
    USE SIGNAL ;
    ANTENNADIFFAREA 0.336 LAYER met2  ;
    ANTENNAPARTIALMETALAREA 4.0627 LAYER met2  ;
    ANTENNAPARTIALMETALSIDEAREA 20.2055 LAYER met2  ;
    PORT
      LAYER met2 ;
        RECT 2585.360000 0.000000 2585.500000 0.485000 ;
    END
  END la_data_out[112]
  PIN la_data_out[111]
    DIRECTION OUTPUT ;
    USE SIGNAL ;
    ANTENNADIFFAREA 0.336 LAYER met2  ;
    ANTENNAPARTIALMETALAREA 4.0627 LAYER met2  ;
    ANTENNAPARTIALMETALSIDEAREA 20.2055 LAYER met2  ;
    PORT
      LAYER met2 ;
        RECT 2567.880000 0.000000 2568.020000 0.485000 ;
    END
  END la_data_out[111]
  PIN la_data_out[110]
    DIRECTION OUTPUT ;
    USE SIGNAL ;
    ANTENNADIFFAREA 0.336 LAYER met2  ;
    ANTENNAPARTIALMETALAREA 4.0627 LAYER met2  ;
    ANTENNAPARTIALMETALSIDEAREA 20.2055 LAYER met2  ;
    PORT
      LAYER met2 ;
        RECT 2550.400000 0.000000 2550.540000 0.485000 ;
    END
  END la_data_out[110]
  PIN la_data_out[109]
    DIRECTION OUTPUT ;
    USE SIGNAL ;
    ANTENNADIFFAREA 0.336 LAYER met2  ;
    ANTENNAPARTIALMETALAREA 4.1915 LAYER met2  ;
    ANTENNAPARTIALMETALSIDEAREA 20.8495 LAYER met2  ;
    PORT
      LAYER met2 ;
        RECT 2532.920000 0.000000 2533.060000 0.485000 ;
    END
  END la_data_out[109]
  PIN la_data_out[108]
    DIRECTION OUTPUT ;
    USE SIGNAL ;
    ANTENNADIFFAREA 0.336 LAYER met2  ;
    ANTENNAPARTIALMETALAREA 4.0627 LAYER met2  ;
    ANTENNAPARTIALMETALSIDEAREA 20.2055 LAYER met2  ;
    PORT
      LAYER met2 ;
        RECT 2515.440000 0.000000 2515.580000 0.485000 ;
    END
  END la_data_out[108]
  PIN la_data_out[107]
    DIRECTION OUTPUT ;
    USE SIGNAL ;
    ANTENNADIFFAREA 0.336 LAYER met2  ;
    ANTENNAPARTIALMETALAREA 4.0627 LAYER met2  ;
    ANTENNAPARTIALMETALSIDEAREA 20.2055 LAYER met2  ;
    PORT
      LAYER met2 ;
        RECT 2497.960000 0.000000 2498.100000 0.485000 ;
    END
  END la_data_out[107]
  PIN la_data_out[106]
    DIRECTION OUTPUT ;
    USE SIGNAL ;
    ANTENNADIFFAREA 0.336 LAYER met2  ;
    ANTENNAPARTIALMETALAREA 4.1915 LAYER met2  ;
    ANTENNAPARTIALMETALSIDEAREA 20.8495 LAYER met2  ;
    PORT
      LAYER met2 ;
        RECT 2480.480000 0.000000 2480.620000 0.485000 ;
    END
  END la_data_out[106]
  PIN la_data_out[105]
    DIRECTION OUTPUT ;
    USE SIGNAL ;
    ANTENNADIFFAREA 0.336 LAYER met2  ;
    ANTENNAPARTIALMETALAREA 4.0627 LAYER met2  ;
    ANTENNAPARTIALMETALSIDEAREA 20.2055 LAYER met2  ;
    PORT
      LAYER met2 ;
        RECT 2463.000000 0.000000 2463.140000 0.485000 ;
    END
  END la_data_out[105]
  PIN la_data_out[104]
    DIRECTION OUTPUT ;
    USE SIGNAL ;
    ANTENNADIFFAREA 0.336 LAYER met2  ;
    ANTENNAPARTIALMETALAREA 4.0627 LAYER met2  ;
    ANTENNAPARTIALMETALSIDEAREA 20.2055 LAYER met2  ;
    PORT
      LAYER met2 ;
        RECT 2445.520000 0.000000 2445.660000 0.485000 ;
    END
  END la_data_out[104]
  PIN la_data_out[103]
    DIRECTION OUTPUT ;
    USE SIGNAL ;
    ANTENNADIFFAREA 0.336 LAYER met2  ;
    ANTENNAPARTIALMETALAREA 4.0627 LAYER met2  ;
    ANTENNAPARTIALMETALSIDEAREA 20.2055 LAYER met2  ;
    PORT
      LAYER met2 ;
        RECT 2428.040000 0.000000 2428.180000 0.485000 ;
    END
  END la_data_out[103]
  PIN la_data_out[102]
    DIRECTION OUTPUT ;
    USE SIGNAL ;
    ANTENNADIFFAREA 0.336 LAYER met2  ;
    ANTENNAPARTIALMETALAREA 4.0627 LAYER met2  ;
    ANTENNAPARTIALMETALSIDEAREA 20.2055 LAYER met2  ;
    PORT
      LAYER met2 ;
        RECT 2410.560000 0.000000 2410.700000 0.485000 ;
    END
  END la_data_out[102]
  PIN la_data_out[101]
    DIRECTION OUTPUT ;
    USE SIGNAL ;
    ANTENNADIFFAREA 0.336 LAYER met2  ;
    ANTENNAPARTIALMETALAREA 4.1915 LAYER met2  ;
    ANTENNAPARTIALMETALSIDEAREA 20.8495 LAYER met2  ;
    PORT
      LAYER met2 ;
        RECT 2393.080000 0.000000 2393.220000 0.485000 ;
    END
  END la_data_out[101]
  PIN la_data_out[100]
    DIRECTION OUTPUT ;
    USE SIGNAL ;
    ANTENNADIFFAREA 0.336 LAYER met2  ;
    ANTENNAPARTIALMETALAREA 4.1915 LAYER met2  ;
    ANTENNAPARTIALMETALSIDEAREA 20.8495 LAYER met2  ;
    PORT
      LAYER met2 ;
        RECT 2375.600000 0.000000 2375.740000 0.485000 ;
    END
  END la_data_out[100]
  PIN la_data_out[99]
    DIRECTION OUTPUT ;
    USE SIGNAL ;
    ANTENNADIFFAREA 0.336 LAYER met2  ;
    ANTENNAPARTIALMETALAREA 4.0627 LAYER met2  ;
    ANTENNAPARTIALMETALSIDEAREA 20.2055 LAYER met2  ;
    PORT
      LAYER met2 ;
        RECT 2358.120000 0.000000 2358.260000 0.485000 ;
    END
  END la_data_out[99]
  PIN la_data_out[98]
    DIRECTION OUTPUT ;
    USE SIGNAL ;
    ANTENNADIFFAREA 0.336 LAYER met2  ;
    ANTENNAPARTIALMETALAREA 4.0627 LAYER met2  ;
    ANTENNAPARTIALMETALSIDEAREA 20.2055 LAYER met2  ;
    PORT
      LAYER met2 ;
        RECT 2340.180000 0.000000 2340.320000 0.485000 ;
    END
  END la_data_out[98]
  PIN la_data_out[97]
    DIRECTION OUTPUT ;
    USE SIGNAL ;
    ANTENNADIFFAREA 0.336 LAYER met2  ;
    ANTENNAPARTIALMETALAREA 4.0627 LAYER met2  ;
    ANTENNAPARTIALMETALSIDEAREA 20.2055 LAYER met2  ;
    PORT
      LAYER met2 ;
        RECT 2322.700000 0.000000 2322.840000 0.485000 ;
    END
  END la_data_out[97]
  PIN la_data_out[96]
    DIRECTION OUTPUT ;
    USE SIGNAL ;
    ANTENNADIFFAREA 0.336 LAYER met2  ;
    ANTENNAPARTIALMETALAREA 4.0627 LAYER met2  ;
    ANTENNAPARTIALMETALSIDEAREA 20.2055 LAYER met2  ;
    PORT
      LAYER met2 ;
        RECT 2305.220000 0.000000 2305.360000 0.485000 ;
    END
  END la_data_out[96]
  PIN la_data_out[95]
    DIRECTION OUTPUT ;
    USE SIGNAL ;
    ANTENNADIFFAREA 0.336 LAYER met2  ;
    ANTENNAPARTIALMETALAREA 4.3035 LAYER met2  ;
    ANTENNAPARTIALMETALSIDEAREA 21.4095 LAYER met2  ;
    PORT
      LAYER met2 ;
        RECT 2287.740000 0.000000 2287.880000 0.485000 ;
    END
  END la_data_out[95]
  PIN la_data_out[94]
    DIRECTION OUTPUT ;
    USE SIGNAL ;
    ANTENNADIFFAREA 0.336 LAYER met2  ;
    ANTENNAPARTIALMETALAREA 4.1103 LAYER met2  ;
    ANTENNAPARTIALMETALSIDEAREA 20.4435 LAYER met2  ;
    PORT
      LAYER met2 ;
        RECT 2270.260000 0.000000 2270.400000 0.485000 ;
    END
  END la_data_out[94]
  PIN la_data_out[93]
    DIRECTION OUTPUT ;
    USE SIGNAL ;
    ANTENNADIFFAREA 0.336 LAYER met2  ;
    ANTENNAPARTIALMETALAREA 4.0627 LAYER met2  ;
    ANTENNAPARTIALMETALSIDEAREA 20.2055 LAYER met2  ;
    PORT
      LAYER met2 ;
        RECT 2252.780000 0.000000 2252.920000 0.485000 ;
    END
  END la_data_out[93]
  PIN la_data_out[92]
    DIRECTION OUTPUT ;
    USE SIGNAL ;
    ANTENNADIFFAREA 0.336 LAYER met2  ;
    ANTENNAPARTIALMETALAREA 4.0627 LAYER met2  ;
    ANTENNAPARTIALMETALSIDEAREA 20.2055 LAYER met2  ;
    PORT
      LAYER met2 ;
        RECT 2235.300000 0.000000 2235.440000 0.485000 ;
    END
  END la_data_out[92]
  PIN la_data_out[91]
    DIRECTION OUTPUT ;
    USE SIGNAL ;
    ANTENNADIFFAREA 0.336 LAYER met2  ;
    ANTENNAPARTIALMETALAREA 4.1271 LAYER met2  ;
    ANTENNAPARTIALMETALSIDEAREA 20.5275 LAYER met2  ;
    PORT
      LAYER met2 ;
        RECT 2217.820000 0.000000 2217.960000 0.485000 ;
    END
  END la_data_out[91]
  PIN la_data_out[90]
    DIRECTION OUTPUT ;
    USE SIGNAL ;
    ANTENNADIFFAREA 0.336 LAYER met2  ;
    ANTENNAPARTIALMETALAREA 4.1271 LAYER met2  ;
    ANTENNAPARTIALMETALSIDEAREA 20.5275 LAYER met2  ;
    PORT
      LAYER met2 ;
        RECT 2200.340000 0.000000 2200.480000 0.485000 ;
    END
  END la_data_out[90]
  PIN la_data_out[89]
    DIRECTION OUTPUT ;
    USE SIGNAL ;
    ANTENNADIFFAREA 0.336 LAYER met2  ;
    ANTENNAPARTIALMETALAREA 4.0627 LAYER met2  ;
    ANTENNAPARTIALMETALSIDEAREA 20.2055 LAYER met2  ;
    PORT
      LAYER met2 ;
        RECT 2182.860000 0.000000 2183.000000 0.485000 ;
    END
  END la_data_out[89]
  PIN la_data_out[88]
    DIRECTION OUTPUT ;
    USE SIGNAL ;
    ANTENNADIFFAREA 0.336 LAYER met2  ;
    ANTENNAPARTIALMETALAREA 4.0627 LAYER met2  ;
    ANTENNAPARTIALMETALSIDEAREA 20.2055 LAYER met2  ;
    PORT
      LAYER met2 ;
        RECT 2165.380000 0.000000 2165.520000 0.485000 ;
    END
  END la_data_out[88]
  PIN la_data_out[87]
    DIRECTION OUTPUT ;
    USE SIGNAL ;
    ANTENNADIFFAREA 0.336 LAYER met2  ;
    ANTENNAPARTIALMETALAREA 4.4435 LAYER met2  ;
    ANTENNAPARTIALMETALSIDEAREA 22.1095 LAYER met2  ;
    PORT
      LAYER met2 ;
        RECT 2147.900000 0.000000 2148.040000 0.485000 ;
    END
  END la_data_out[87]
  PIN la_data_out[86]
    DIRECTION OUTPUT ;
    USE SIGNAL ;
    ANTENNADIFFAREA 0.336 LAYER met2  ;
    ANTENNAPARTIALMETALAREA 4.0627 LAYER met2  ;
    ANTENNAPARTIALMETALSIDEAREA 20.2055 LAYER met2  ;
    PORT
      LAYER met2 ;
        RECT 2130.420000 0.000000 2130.560000 0.485000 ;
    END
  END la_data_out[86]
  PIN la_data_out[85]
    DIRECTION OUTPUT ;
    USE SIGNAL ;
    ANTENNADIFFAREA 0.336 LAYER met2  ;
    ANTENNAPARTIALMETALAREA 4.4435 LAYER met2  ;
    ANTENNAPARTIALMETALSIDEAREA 22.1095 LAYER met2  ;
    PORT
      LAYER met2 ;
        RECT 2112.940000 0.000000 2113.080000 0.485000 ;
    END
  END la_data_out[85]
  PIN la_data_out[84]
    DIRECTION OUTPUT ;
    USE SIGNAL ;
    ANTENNADIFFAREA 0.336 LAYER met2  ;
    ANTENNAPARTIALMETALAREA 4.1103 LAYER met2  ;
    ANTENNAPARTIALMETALSIDEAREA 20.4435 LAYER met2  ;
    PORT
      LAYER met2 ;
        RECT 2095.460000 0.000000 2095.600000 0.485000 ;
    END
  END la_data_out[84]
  PIN la_data_out[83]
    DIRECTION OUTPUT ;
    USE SIGNAL ;
    ANTENNADIFFAREA 0.336 LAYER met2  ;
    ANTENNAPARTIALMETALAREA 4.0627 LAYER met2  ;
    ANTENNAPARTIALMETALSIDEAREA 20.2055 LAYER met2  ;
    PORT
      LAYER met2 ;
        RECT 2077.980000 0.000000 2078.120000 0.485000 ;
    END
  END la_data_out[83]
  PIN la_data_out[82]
    DIRECTION OUTPUT ;
    USE SIGNAL ;
    ANTENNADIFFAREA 0.336 LAYER met2  ;
    ANTENNAPARTIALMETALAREA 4.1103 LAYER met2  ;
    ANTENNAPARTIALMETALSIDEAREA 20.4435 LAYER met2  ;
    PORT
      LAYER met2 ;
        RECT 2060.500000 0.000000 2060.640000 0.485000 ;
    END
  END la_data_out[82]
  PIN la_data_out[81]
    DIRECTION OUTPUT ;
    USE SIGNAL ;
    ANTENNADIFFAREA 0.336 LAYER met2  ;
    ANTENNAPARTIALMETALAREA 4.1103 LAYER met2  ;
    ANTENNAPARTIALMETALSIDEAREA 20.4435 LAYER met2  ;
    PORT
      LAYER met2 ;
        RECT 2042.560000 0.000000 2042.700000 0.485000 ;
    END
  END la_data_out[81]
  PIN la_data_out[80]
    DIRECTION OUTPUT ;
    USE SIGNAL ;
    ANTENNADIFFAREA 0.336 LAYER met2  ;
    ANTENNAPARTIALMETALAREA 4.0627 LAYER met2  ;
    ANTENNAPARTIALMETALSIDEAREA 20.2055 LAYER met2  ;
    PORT
      LAYER met2 ;
        RECT 2025.080000 0.000000 2025.220000 0.485000 ;
    END
  END la_data_out[80]
  PIN la_data_out[79]
    DIRECTION OUTPUT ;
    USE SIGNAL ;
    ANTENNADIFFAREA 0.336 LAYER met2  ;
    ANTENNAPARTIALMETALAREA 4.0627 LAYER met2  ;
    ANTENNAPARTIALMETALSIDEAREA 20.2055 LAYER met2  ;
    PORT
      LAYER met2 ;
        RECT 2007.600000 0.000000 2007.740000 0.485000 ;
    END
  END la_data_out[79]
  PIN la_data_out[78]
    DIRECTION OUTPUT ;
    USE SIGNAL ;
    ANTENNADIFFAREA 0.336 LAYER met2  ;
    ANTENNAPARTIALMETALAREA 4.6199 LAYER met2  ;
    ANTENNAPARTIALMETALSIDEAREA 22.9915 LAYER met2  ;
    PORT
      LAYER met2 ;
        RECT 1990.120000 0.000000 1990.260000 0.485000 ;
    END
  END la_data_out[78]
  PIN la_data_out[77]
    DIRECTION OUTPUT ;
    USE SIGNAL ;
    ANTENNADIFFAREA 0.336 LAYER met2  ;
    ANTENNAPARTIALMETALAREA 4.9573 LAYER met2  ;
    ANTENNAPARTIALMETALSIDEAREA 24.6785 LAYER met2  ;
    PORT
      LAYER met2 ;
        RECT 1972.640000 0.000000 1972.780000 0.485000 ;
    END
  END la_data_out[77]
  PIN la_data_out[76]
    DIRECTION OUTPUT ;
    USE SIGNAL ;
    ANTENNADIFFAREA 0.336 LAYER met2  ;
    ANTENNAPARTIALMETALAREA 4.2559 LAYER met2  ;
    ANTENNAPARTIALMETALSIDEAREA 21.1715 LAYER met2  ;
    PORT
      LAYER met2 ;
        RECT 1955.160000 0.000000 1955.300000 0.485000 ;
    END
  END la_data_out[76]
  PIN la_data_out[75]
    DIRECTION OUTPUT ;
    USE SIGNAL ;
    ANTENNADIFFAREA 0.336 LAYER met2  ;
    ANTENNAPARTIALMETALAREA 4.216 LAYER met2  ;
    ANTENNAPARTIALMETALSIDEAREA 20.972 LAYER met2  ;
    PORT
      LAYER met2 ;
        RECT 1937.680000 0.000000 1937.820000 0.485000 ;
    END
  END la_data_out[75]
  PIN la_data_out[74]
    DIRECTION OUTPUT ;
    USE SIGNAL ;
    ANTENNADIFFAREA 0.336 LAYER met2  ;
    ANTENNAPARTIALMETALAREA 4.1271 LAYER met2  ;
    ANTENNAPARTIALMETALSIDEAREA 20.5275 LAYER met2  ;
    PORT
      LAYER met2 ;
        RECT 1920.200000 0.000000 1920.340000 0.485000 ;
    END
  END la_data_out[74]
  PIN la_data_out[73]
    DIRECTION OUTPUT ;
    USE SIGNAL ;
    ANTENNADIFFAREA 0.336 LAYER met2  ;
    ANTENNAPARTIALMETALAREA 4.0627 LAYER met2  ;
    ANTENNAPARTIALMETALSIDEAREA 20.2055 LAYER met2  ;
    PORT
      LAYER met2 ;
        RECT 1902.720000 0.000000 1902.860000 0.485000 ;
    END
  END la_data_out[73]
  PIN la_data_out[72]
    DIRECTION OUTPUT ;
    USE SIGNAL ;
    ANTENNADIFFAREA 0.336 LAYER met2  ;
    ANTENNAPARTIALMETALAREA 4.0627 LAYER met2  ;
    ANTENNAPARTIALMETALSIDEAREA 20.2055 LAYER met2  ;
    PORT
      LAYER met2 ;
        RECT 1885.240000 0.000000 1885.380000 0.485000 ;
    END
  END la_data_out[72]
  PIN la_data_out[71]
    DIRECTION OUTPUT ;
    USE SIGNAL ;
    ANTENNADIFFAREA 0.336 LAYER met2  ;
    ANTENNAPARTIALMETALAREA 4.0627 LAYER met2  ;
    ANTENNAPARTIALMETALSIDEAREA 20.2055 LAYER met2  ;
    PORT
      LAYER met2 ;
        RECT 1867.760000 0.000000 1867.900000 0.485000 ;
    END
  END la_data_out[71]
  PIN la_data_out[70]
    DIRECTION OUTPUT ;
    USE SIGNAL ;
    ANTENNADIFFAREA 0.336 LAYER met2  ;
    ANTENNAPARTIALMETALAREA 4.4435 LAYER met2  ;
    ANTENNAPARTIALMETALSIDEAREA 22.1095 LAYER met2  ;
    PORT
      LAYER met2 ;
        RECT 1850.280000 0.000000 1850.420000 0.485000 ;
    END
  END la_data_out[70]
  PIN la_data_out[69]
    DIRECTION OUTPUT ;
    USE SIGNAL ;
    ANTENNADIFFAREA 0.336 LAYER met2  ;
    ANTENNAPARTIALMETALAREA 4.0627 LAYER met2  ;
    ANTENNAPARTIALMETALSIDEAREA 20.2055 LAYER met2  ;
    PORT
      LAYER met2 ;
        RECT 1832.800000 0.000000 1832.940000 0.485000 ;
    END
  END la_data_out[69]
  PIN la_data_out[68]
    DIRECTION OUTPUT ;
    USE SIGNAL ;
    ANTENNADIFFAREA 0.336 LAYER met2  ;
    ANTENNAPARTIALMETALAREA 4.0627 LAYER met2  ;
    ANTENNAPARTIALMETALSIDEAREA 20.2055 LAYER met2  ;
    PORT
      LAYER met2 ;
        RECT 1815.320000 0.000000 1815.460000 0.485000 ;
    END
  END la_data_out[68]
  PIN la_data_out[67]
    DIRECTION OUTPUT ;
    USE SIGNAL ;
    ANTENNADIFFAREA 0.336 LAYER met2  ;
    ANTENNAPARTIALMETALAREA 4.3203 LAYER met2  ;
    ANTENNAPARTIALMETALSIDEAREA 21.4935 LAYER met2  ;
    PORT
      LAYER met2 ;
        RECT 1797.840000 0.000000 1797.980000 0.485000 ;
    END
  END la_data_out[67]
  PIN la_data_out[66]
    DIRECTION OUTPUT ;
    USE SIGNAL ;
    ANTENNADIFFAREA 0.336 LAYER met2  ;
    ANTENNAPARTIALMETALAREA 4.2391 LAYER met2  ;
    ANTENNAPARTIALMETALSIDEAREA 21.0875 LAYER met2  ;
    PORT
      LAYER met2 ;
        RECT 1780.360000 0.000000 1780.500000 0.485000 ;
    END
  END la_data_out[66]
  PIN la_data_out[65]
    DIRECTION OUTPUT ;
    USE SIGNAL ;
    ANTENNADIFFAREA 0.336 LAYER met2  ;
    ANTENNAPARTIALMETALAREA 4.1915 LAYER met2  ;
    ANTENNAPARTIALMETALSIDEAREA 20.8495 LAYER met2  ;
    PORT
      LAYER met2 ;
        RECT 1762.880000 0.000000 1763.020000 0.485000 ;
    END
  END la_data_out[65]
  PIN la_data_out[64]
    DIRECTION OUTPUT ;
    USE SIGNAL ;
    ANTENNADIFFAREA 0.336 LAYER met2  ;
    ANTENNAPARTIALMETALAREA 4.0627 LAYER met2  ;
    ANTENNAPARTIALMETALSIDEAREA 20.2055 LAYER met2  ;
    PORT
      LAYER met2 ;
        RECT 1745.400000 0.000000 1745.540000 0.485000 ;
    END
  END la_data_out[64]
  PIN la_data_out[63]
    DIRECTION OUTPUT ;
    USE SIGNAL ;
    ANTENNADIFFAREA 0.336 LAYER met2  ;
    ANTENNAPARTIALMETALAREA 4.1271 LAYER met2  ;
    ANTENNAPARTIALMETALSIDEAREA 20.5275 LAYER met2  ;
    PORT
      LAYER met2 ;
        RECT 1727.460000 0.000000 1727.600000 0.485000 ;
    END
  END la_data_out[63]
  PIN la_data_out[62]
    DIRECTION OUTPUT ;
    USE SIGNAL ;
    ANTENNADIFFAREA 0.336 LAYER met2  ;
    ANTENNAPARTIALMETALAREA 4.0627 LAYER met2  ;
    ANTENNAPARTIALMETALSIDEAREA 20.2055 LAYER met2  ;
    PORT
      LAYER met2 ;
        RECT 1709.980000 0.000000 1710.120000 0.485000 ;
    END
  END la_data_out[62]
  PIN la_data_out[61]
    DIRECTION OUTPUT ;
    USE SIGNAL ;
    ANTENNADIFFAREA 0.336 LAYER met2  ;
    ANTENNAPARTIALMETALAREA 4.3448 LAYER met2  ;
    ANTENNAPARTIALMETALSIDEAREA 21.616 LAYER met2  ;
    PORT
      LAYER met2 ;
        RECT 1692.500000 0.000000 1692.640000 0.485000 ;
    END
  END la_data_out[61]
  PIN la_data_out[60]
    DIRECTION OUTPUT ;
    USE SIGNAL ;
    ANTENNADIFFAREA 0.336 LAYER met2  ;
    ANTENNAPARTIALMETALAREA 4.1915 LAYER met2  ;
    ANTENNAPARTIALMETALSIDEAREA 20.8495 LAYER met2  ;
    PORT
      LAYER met2 ;
        RECT 1675.020000 0.000000 1675.160000 0.485000 ;
    END
  END la_data_out[60]
  PIN la_data_out[59]
    DIRECTION OUTPUT ;
    USE SIGNAL ;
    ANTENNADIFFAREA 0.336 LAYER met2  ;
    ANTENNAPARTIALMETALAREA 4.0627 LAYER met2  ;
    ANTENNAPARTIALMETALSIDEAREA 20.2055 LAYER met2  ;
    PORT
      LAYER met2 ;
        RECT 1657.540000 0.000000 1657.680000 0.485000 ;
    END
  END la_data_out[59]
  PIN la_data_out[58]
    DIRECTION OUTPUT ;
    USE SIGNAL ;
    ANTENNADIFFAREA 0.336 LAYER met2  ;
    ANTENNAPARTIALMETALAREA 4.5723 LAYER met2  ;
    ANTENNAPARTIALMETALSIDEAREA 22.7535 LAYER met2  ;
    PORT
      LAYER met2 ;
        RECT 1640.060000 0.000000 1640.200000 0.485000 ;
    END
  END la_data_out[58]
  PIN la_data_out[57]
    DIRECTION OUTPUT ;
    USE SIGNAL ;
    ANTENNADIFFAREA 0.336 LAYER met2  ;
    ANTENNAPARTIALMETALAREA 4.2559 LAYER met2  ;
    ANTENNAPARTIALMETALSIDEAREA 21.1715 LAYER met2  ;
    PORT
      LAYER met2 ;
        RECT 1622.580000 0.000000 1622.720000 0.485000 ;
    END
  END la_data_out[57]
  PIN la_data_out[56]
    DIRECTION OUTPUT ;
    USE SIGNAL ;
    ANTENNADIFFAREA 0.336 LAYER met2  ;
    ANTENNAPARTIALMETALAREA 4.1915 LAYER met2  ;
    ANTENNAPARTIALMETALSIDEAREA 20.8495 LAYER met2  ;
    PORT
      LAYER met2 ;
        RECT 1605.100000 0.000000 1605.240000 0.485000 ;
    END
  END la_data_out[56]
  PIN la_data_out[55]
    DIRECTION OUTPUT ;
    USE SIGNAL ;
    ANTENNADIFFAREA 0.336 LAYER met2  ;
    ANTENNAPARTIALMETALAREA 4.0627 LAYER met2  ;
    ANTENNAPARTIALMETALSIDEAREA 20.2055 LAYER met2  ;
    PORT
      LAYER met2 ;
        RECT 1587.620000 0.000000 1587.760000 0.485000 ;
    END
  END la_data_out[55]
  PIN la_data_out[54]
    DIRECTION OUTPUT ;
    USE SIGNAL ;
    ANTENNADIFFAREA 0.336 LAYER met2  ;
    ANTENNAPARTIALMETALAREA 4.0627 LAYER met2  ;
    ANTENNAPARTIALMETALSIDEAREA 20.2055 LAYER met2  ;
    PORT
      LAYER met2 ;
        RECT 1570.140000 0.000000 1570.280000 0.485000 ;
    END
  END la_data_out[54]
  PIN la_data_out[53]
    DIRECTION OUTPUT ;
    USE SIGNAL ;
    ANTENNADIFFAREA 0.336 LAYER met2  ;
    ANTENNAPARTIALMETALAREA 4.3847 LAYER met2  ;
    ANTENNAPARTIALMETALSIDEAREA 21.8155 LAYER met2  ;
    PORT
      LAYER met2 ;
        RECT 1552.660000 0.000000 1552.800000 0.485000 ;
    END
  END la_data_out[53]
  PIN la_data_out[52]
    DIRECTION OUTPUT ;
    USE SIGNAL ;
    ANTENNADIFFAREA 0.336 LAYER met2  ;
    ANTENNAPARTIALMETALAREA 4.1271 LAYER met2  ;
    ANTENNAPARTIALMETALSIDEAREA 20.5275 LAYER met2  ;
    PORT
      LAYER met2 ;
        RECT 1535.180000 0.000000 1535.320000 0.485000 ;
    END
  END la_data_out[52]
  PIN la_data_out[51]
    DIRECTION OUTPUT ;
    USE SIGNAL ;
    ANTENNADIFFAREA 0.336 LAYER met2  ;
    ANTENNAPARTIALMETALAREA 4.0627 LAYER met2  ;
    ANTENNAPARTIALMETALSIDEAREA 20.2055 LAYER met2  ;
    PORT
      LAYER met2 ;
        RECT 1517.700000 0.000000 1517.840000 0.485000 ;
    END
  END la_data_out[51]
  PIN la_data_out[50]
    DIRECTION OUTPUT ;
    USE SIGNAL ;
    ANTENNADIFFAREA 0.336 LAYER met2  ;
    ANTENNAPARTIALMETALAREA 4.0627 LAYER met2  ;
    ANTENNAPARTIALMETALSIDEAREA 20.2055 LAYER met2  ;
    PORT
      LAYER met2 ;
        RECT 1500.220000 0.000000 1500.360000 0.485000 ;
    END
  END la_data_out[50]
  PIN la_data_out[49]
    DIRECTION OUTPUT ;
    USE SIGNAL ;
    ANTENNADIFFAREA 0.336 LAYER met2  ;
    ANTENNAPARTIALMETALAREA 4.3203 LAYER met2  ;
    ANTENNAPARTIALMETALSIDEAREA 21.4935 LAYER met2  ;
    PORT
      LAYER met2 ;
        RECT 1482.740000 0.000000 1482.880000 0.485000 ;
    END
  END la_data_out[49]
  PIN la_data_out[48]
    DIRECTION OUTPUT ;
    USE SIGNAL ;
    ANTENNADIFFAREA 0.336 LAYER met2  ;
    ANTENNAPARTIALMETALAREA 4.1915 LAYER met2  ;
    ANTENNAPARTIALMETALSIDEAREA 20.8495 LAYER met2  ;
    PORT
      LAYER met2 ;
        RECT 1465.260000 0.000000 1465.400000 0.485000 ;
    END
  END la_data_out[48]
  PIN la_data_out[47]
    DIRECTION OUTPUT ;
    USE SIGNAL ;
    ANTENNADIFFAREA 0.336 LAYER met2  ;
    ANTENNAPARTIALMETALAREA 4.8145 LAYER met2  ;
    ANTENNAPARTIALMETALSIDEAREA 23.9645 LAYER met2  ;
    PORT
      LAYER met2 ;
        RECT 1447.780000 0.000000 1447.920000 0.485000 ;
    END
  END la_data_out[47]
  PIN la_data_out[46]
    DIRECTION OUTPUT ;
    USE SIGNAL ;
    ANTENNADIFFAREA 0.336 LAYER met2  ;
    ANTENNAPARTIALMETALAREA 4.3847 LAYER met2  ;
    ANTENNAPARTIALMETALSIDEAREA 21.8155 LAYER met2  ;
    PORT
      LAYER met2 ;
        RECT 1429.840000 0.000000 1429.980000 0.485000 ;
    END
  END la_data_out[46]
  PIN la_data_out[45]
    DIRECTION OUTPUT ;
    USE SIGNAL ;
    ANTENNADIFFAREA 0.336 LAYER met2  ;
    ANTENNAPARTIALMETALAREA 4.0627 LAYER met2  ;
    ANTENNAPARTIALMETALSIDEAREA 20.2055 LAYER met2  ;
    PORT
      LAYER met2 ;
        RECT 1412.360000 0.000000 1412.500000 0.485000 ;
    END
  END la_data_out[45]
  PIN la_data_out[44]
    DIRECTION OUTPUT ;
    USE SIGNAL ;
    ANTENNADIFFAREA 0.336 LAYER met2  ;
    ANTENNAPARTIALMETALAREA 5.3339 LAYER met2  ;
    ANTENNAPARTIALMETALSIDEAREA 26.5615 LAYER met2  ;
    PORT
      LAYER met2 ;
        RECT 1394.880000 0.000000 1395.020000 0.485000 ;
    END
  END la_data_out[44]
  PIN la_data_out[43]
    DIRECTION OUTPUT ;
    USE SIGNAL ;
    ANTENNADIFFAREA 0.336 LAYER met2  ;
    ANTENNAPARTIALMETALAREA 4.0627 LAYER met2  ;
    ANTENNAPARTIALMETALSIDEAREA 20.2055 LAYER met2  ;
    PORT
      LAYER met2 ;
        RECT 1377.400000 0.000000 1377.540000 0.485000 ;
    END
  END la_data_out[43]
  PIN la_data_out[42]
    DIRECTION OUTPUT ;
    USE SIGNAL ;
    ANTENNADIFFAREA 0.336 LAYER met2  ;
    ANTENNAPARTIALMETALAREA 4.0627 LAYER met2  ;
    ANTENNAPARTIALMETALSIDEAREA 20.2055 LAYER met2  ;
    PORT
      LAYER met2 ;
        RECT 1359.920000 0.000000 1360.060000 0.485000 ;
    END
  END la_data_out[42]
  PIN la_data_out[41]
    DIRECTION OUTPUT ;
    USE SIGNAL ;
    ANTENNADIFFAREA 0.336 LAYER met2  ;
    ANTENNAPARTIALMETALAREA 4.0627 LAYER met2  ;
    ANTENNAPARTIALMETALSIDEAREA 20.2055 LAYER met2  ;
    PORT
      LAYER met2 ;
        RECT 1342.440000 0.000000 1342.580000 0.485000 ;
    END
  END la_data_out[41]
  PIN la_data_out[40]
    DIRECTION OUTPUT ;
    USE SIGNAL ;
    ANTENNADIFFAREA 0.336 LAYER met2  ;
    ANTENNAPARTIALMETALAREA 4.0627 LAYER met2  ;
    ANTENNAPARTIALMETALSIDEAREA 20.2055 LAYER met2  ;
    PORT
      LAYER met2 ;
        RECT 1324.960000 0.000000 1325.100000 0.485000 ;
    END
  END la_data_out[40]
  PIN la_data_out[39]
    DIRECTION OUTPUT ;
    USE SIGNAL ;
    ANTENNADIFFAREA 0.336 LAYER met2  ;
    ANTENNAPARTIALMETALAREA 4.0627 LAYER met2  ;
    ANTENNAPARTIALMETALSIDEAREA 20.2055 LAYER met2  ;
    PORT
      LAYER met2 ;
        RECT 1307.480000 0.000000 1307.620000 0.485000 ;
    END
  END la_data_out[39]
  PIN la_data_out[38]
    DIRECTION OUTPUT ;
    USE SIGNAL ;
    ANTENNADIFFAREA 0.336 LAYER met2  ;
    ANTENNAPARTIALMETALAREA 4.5387 LAYER met2  ;
    ANTENNAPARTIALMETALSIDEAREA 22.5855 LAYER met2  ;
    PORT
      LAYER met2 ;
        RECT 1290.000000 0.000000 1290.140000 0.485000 ;
    END
  END la_data_out[38]
  PIN la_data_out[37]
    DIRECTION OUTPUT ;
    USE SIGNAL ;
    ANTENNADIFFAREA 0.336 LAYER met2  ;
    ANTENNAPARTIALMETALAREA 4.1271 LAYER met2  ;
    ANTENNAPARTIALMETALSIDEAREA 20.5275 LAYER met2  ;
    PORT
      LAYER met2 ;
        RECT 1272.520000 0.000000 1272.660000 0.485000 ;
    END
  END la_data_out[37]
  PIN la_data_out[36]
    DIRECTION OUTPUT ;
    USE SIGNAL ;
    ANTENNADIFFAREA 0.336 LAYER met2  ;
    ANTENNAPARTIALMETALAREA 4.0627 LAYER met2  ;
    ANTENNAPARTIALMETALSIDEAREA 20.2055 LAYER met2  ;
    PORT
      LAYER met2 ;
        RECT 1255.040000 0.000000 1255.180000 0.485000 ;
    END
  END la_data_out[36]
  PIN la_data_out[35]
    DIRECTION OUTPUT ;
    USE SIGNAL ;
    ANTENNADIFFAREA 0.336 LAYER met2  ;
    ANTENNAPARTIALMETALAREA 4.0627 LAYER met2  ;
    ANTENNAPARTIALMETALSIDEAREA 20.2055 LAYER met2  ;
    PORT
      LAYER met2 ;
        RECT 1237.560000 0.000000 1237.700000 0.485000 ;
    END
  END la_data_out[35]
  PIN la_data_out[34]
    DIRECTION OUTPUT ;
    USE SIGNAL ;
    ANTENNADIFFAREA 0.336 LAYER met2  ;
    ANTENNAPARTIALMETALAREA 4.0627 LAYER met2  ;
    ANTENNAPARTIALMETALSIDEAREA 20.2055 LAYER met2  ;
    PORT
      LAYER met2 ;
        RECT 1220.080000 0.000000 1220.220000 0.485000 ;
    END
  END la_data_out[34]
  PIN la_data_out[33]
    DIRECTION OUTPUT ;
    USE SIGNAL ;
    ANTENNADIFFAREA 0.336 LAYER met2  ;
    ANTENNAPARTIALMETALAREA 4.4911 LAYER met2  ;
    ANTENNAPARTIALMETALSIDEAREA 22.3475 LAYER met2  ;
    PORT
      LAYER met2 ;
        RECT 1202.600000 0.000000 1202.740000 0.485000 ;
    END
  END la_data_out[33]
  PIN la_data_out[32]
    DIRECTION OUTPUT ;
    USE SIGNAL ;
    ANTENNADIFFAREA 0.336 LAYER met2  ;
    ANTENNAPARTIALMETALAREA 4.0627 LAYER met2  ;
    ANTENNAPARTIALMETALSIDEAREA 20.2055 LAYER met2  ;
    PORT
      LAYER met2 ;
        RECT 1185.120000 0.000000 1185.260000 0.485000 ;
    END
  END la_data_out[32]
  PIN la_data_out[31]
    DIRECTION OUTPUT ;
    USE SIGNAL ;
    ANTENNADIFFAREA 0.336 LAYER met2  ;
    ANTENNAPARTIALMETALAREA 4.0627 LAYER met2  ;
    ANTENNAPARTIALMETALSIDEAREA 20.2055 LAYER met2  ;
    PORT
      LAYER met2 ;
        RECT 1167.640000 0.000000 1167.780000 0.485000 ;
    END
  END la_data_out[31]
  PIN la_data_out[30]
    DIRECTION OUTPUT ;
    USE SIGNAL ;
    ANTENNADIFFAREA 0.336 LAYER met2  ;
    ANTENNAPARTIALMETALAREA 4.1915 LAYER met2  ;
    ANTENNAPARTIALMETALSIDEAREA 20.8495 LAYER met2  ;
    PORT
      LAYER met2 ;
        RECT 1150.160000 0.000000 1150.300000 0.485000 ;
    END
  END la_data_out[30]
  PIN la_data_out[29]
    DIRECTION OUTPUT ;
    USE SIGNAL ;
    ANTENNADIFFAREA 0.336 LAYER met2  ;
    ANTENNAPARTIALMETALAREA 4.2055 LAYER met2  ;
    ANTENNAPARTIALMETALSIDEAREA 20.9195 LAYER met2  ;
    PORT
      LAYER met2 ;
        RECT 1132.680000 0.000000 1132.820000 0.485000 ;
    END
  END la_data_out[29]
  PIN la_data_out[28]
    DIRECTION OUTPUT ;
    USE SIGNAL ;
    ANTENNADIFFAREA 0.336 LAYER met2  ;
    ANTENNAPARTIALMETALAREA 4.0627 LAYER met2  ;
    ANTENNAPARTIALMETALSIDEAREA 20.2055 LAYER met2  ;
    PORT
      LAYER met2 ;
        RECT 1114.740000 0.000000 1114.880000 0.485000 ;
    END
  END la_data_out[28]
  PIN la_data_out[27]
    DIRECTION OUTPUT ;
    USE SIGNAL ;
    ANTENNADIFFAREA 0.336 LAYER met2  ;
    ANTENNAPARTIALMETALAREA 4.0627 LAYER met2  ;
    ANTENNAPARTIALMETALSIDEAREA 20.2055 LAYER met2  ;
    PORT
      LAYER met2 ;
        RECT 1097.260000 0.000000 1097.400000 0.485000 ;
    END
  END la_data_out[27]
  PIN la_data_out[26]
    DIRECTION OUTPUT ;
    USE SIGNAL ;
    ANTENNADIFFAREA 0.336 LAYER met2  ;
    ANTENNAPARTIALMETALAREA 4.0627 LAYER met2  ;
    ANTENNAPARTIALMETALSIDEAREA 20.2055 LAYER met2  ;
    PORT
      LAYER met2 ;
        RECT 1079.780000 0.000000 1079.920000 0.485000 ;
    END
  END la_data_out[26]
  PIN la_data_out[25]
    DIRECTION OUTPUT ;
    USE SIGNAL ;
    ANTENNADIFFAREA 0.336 LAYER met2  ;
    ANTENNAPARTIALMETALAREA 4.1103 LAYER met2  ;
    ANTENNAPARTIALMETALSIDEAREA 20.4435 LAYER met2  ;
    PORT
      LAYER met2 ;
        RECT 1062.300000 0.000000 1062.440000 0.485000 ;
    END
  END la_data_out[25]
  PIN la_data_out[24]
    DIRECTION OUTPUT ;
    USE SIGNAL ;
    ANTENNADIFFAREA 0.336 LAYER met2  ;
    ANTENNAPARTIALMETALAREA 4.0627 LAYER met2  ;
    ANTENNAPARTIALMETALSIDEAREA 20.2055 LAYER met2  ;
    PORT
      LAYER met2 ;
        RECT 1044.820000 0.000000 1044.960000 0.485000 ;
    END
  END la_data_out[24]
  PIN la_data_out[23]
    DIRECTION OUTPUT ;
    USE SIGNAL ;
    ANTENNADIFFAREA 0.336 LAYER met2  ;
    ANTENNAPARTIALMETALAREA 4.8943 LAYER met2  ;
    ANTENNAPARTIALMETALSIDEAREA 24.3635 LAYER met2  ;
    PORT
      LAYER met2 ;
        RECT 1027.340000 0.000000 1027.480000 0.485000 ;
    END
  END la_data_out[23]
  PIN la_data_out[22]
    DIRECTION OUTPUT ;
    USE SIGNAL ;
    ANTENNADIFFAREA 0.336 LAYER met2  ;
    ANTENNAPARTIALMETALAREA 4.4092 LAYER met2  ;
    ANTENNAPARTIALMETALSIDEAREA 21.938 LAYER met2  ;
    PORT
      LAYER met2 ;
        RECT 1009.860000 0.000000 1010.000000 0.485000 ;
    END
  END la_data_out[22]
  PIN la_data_out[21]
    DIRECTION OUTPUT ;
    USE SIGNAL ;
    ANTENNADIFFAREA 0.336 LAYER met2  ;
    ANTENNAPARTIALMETALAREA 4.2559 LAYER met2  ;
    ANTENNAPARTIALMETALSIDEAREA 21.1715 LAYER met2  ;
    PORT
      LAYER met2 ;
        RECT 992.380000 0.000000 992.520000 0.485000 ;
    END
  END la_data_out[21]
  PIN la_data_out[20]
    DIRECTION OUTPUT ;
    USE SIGNAL ;
    ANTENNADIFFAREA 0.336 LAYER met2  ;
    ANTENNAPARTIALMETALAREA 4.2867 LAYER met2  ;
    ANTENNAPARTIALMETALSIDEAREA 21.3255 LAYER met2  ;
    PORT
      LAYER met2 ;
        RECT 974.900000 0.000000 975.040000 0.485000 ;
    END
  END la_data_out[20]
  PIN la_data_out[19]
    DIRECTION OUTPUT ;
    USE SIGNAL ;
    ANTENNADIFFAREA 0.336 LAYER met2  ;
    ANTENNAPARTIALMETALAREA 4.0627 LAYER met2  ;
    ANTENNAPARTIALMETALSIDEAREA 20.2055 LAYER met2  ;
    PORT
      LAYER met2 ;
        RECT 957.420000 0.000000 957.560000 0.485000 ;
    END
  END la_data_out[19]
  PIN la_data_out[18]
    DIRECTION OUTPUT ;
    USE SIGNAL ;
    ANTENNADIFFAREA 0.336 LAYER met2  ;
    ANTENNAPARTIALMETALAREA 4.1915 LAYER met2  ;
    ANTENNAPARTIALMETALSIDEAREA 20.8495 LAYER met2  ;
    PORT
      LAYER met2 ;
        RECT 939.940000 0.000000 940.080000 0.485000 ;
    END
  END la_data_out[18]
  PIN la_data_out[17]
    DIRECTION OUTPUT ;
    USE SIGNAL ;
    ANTENNADIFFAREA 0.336 LAYER met2  ;
    ANTENNAPARTIALMETALAREA 4.1747 LAYER met2  ;
    ANTENNAPARTIALMETALSIDEAREA 20.7655 LAYER met2  ;
    PORT
      LAYER met2 ;
        RECT 922.460000 0.000000 922.600000 0.485000 ;
    END
  END la_data_out[17]
  PIN la_data_out[16]
    DIRECTION OUTPUT ;
    USE SIGNAL ;
    ANTENNADIFFAREA 0.336 LAYER met2  ;
    ANTENNAPARTIALMETALAREA 4.1915 LAYER met2  ;
    ANTENNAPARTIALMETALSIDEAREA 20.8495 LAYER met2  ;
    PORT
      LAYER met2 ;
        RECT 904.980000 0.000000 905.120000 0.485000 ;
    END
  END la_data_out[16]
  PIN la_data_out[15]
    DIRECTION OUTPUT ;
    USE SIGNAL ;
    ANTENNADIFFAREA 0.336 LAYER met2  ;
    ANTENNAPARTIALMETALAREA 4.0669 LAYER met2  ;
    ANTENNAPARTIALMETALSIDEAREA 20.2265 LAYER met2  ;
    PORT
      LAYER met2 ;
        RECT 887.500000 0.000000 887.640000 0.485000 ;
    END
  END la_data_out[15]
  PIN la_data_out[14]
    DIRECTION OUTPUT ;
    USE SIGNAL ;
    ANTENNADIFFAREA 0.336 LAYER met2  ;
    ANTENNAPARTIALMETALAREA 4.1103 LAYER met2  ;
    ANTENNAPARTIALMETALSIDEAREA 20.4435 LAYER met2  ;
    PORT
      LAYER met2 ;
        RECT 870.020000 0.000000 870.160000 0.485000 ;
    END
  END la_data_out[14]
  PIN la_data_out[13]
    DIRECTION OUTPUT ;
    USE SIGNAL ;
    ANTENNADIFFAREA 0.336 LAYER met2  ;
    ANTENNAPARTIALMETALAREA 4.0627 LAYER met2  ;
    ANTENNAPARTIALMETALSIDEAREA 20.2055 LAYER met2  ;
    PORT
      LAYER met2 ;
        RECT 852.540000 0.000000 852.680000 0.485000 ;
    END
  END la_data_out[13]
  PIN la_data_out[12]
    DIRECTION OUTPUT ;
    USE SIGNAL ;
    ANTENNADIFFAREA 0.336 LAYER met2  ;
    ANTENNAPARTIALMETALAREA 4.1915 LAYER met2  ;
    ANTENNAPARTIALMETALSIDEAREA 20.8495 LAYER met2  ;
    PORT
      LAYER met2 ;
        RECT 835.060000 0.000000 835.200000 0.485000 ;
    END
  END la_data_out[12]
  PIN la_data_out[11]
    DIRECTION OUTPUT ;
    USE SIGNAL ;
    ANTENNADIFFAREA 0.336 LAYER met2  ;
    ANTENNAPARTIALMETALAREA 4.0627 LAYER met2  ;
    ANTENNAPARTIALMETALSIDEAREA 20.2055 LAYER met2  ;
    PORT
      LAYER met2 ;
        RECT 817.120000 0.000000 817.260000 0.485000 ;
    END
  END la_data_out[11]
  PIN la_data_out[10]
    DIRECTION OUTPUT ;
    USE SIGNAL ;
    ANTENNADIFFAREA 0.336 LAYER met2  ;
    ANTENNAPARTIALMETALAREA 4.1103 LAYER met2  ;
    ANTENNAPARTIALMETALSIDEAREA 20.4435 LAYER met2  ;
    PORT
      LAYER met2 ;
        RECT 799.640000 0.000000 799.780000 0.485000 ;
    END
  END la_data_out[10]
  PIN la_data_out[9]
    DIRECTION OUTPUT ;
    USE SIGNAL ;
    ANTENNADIFFAREA 0.336 LAYER met2  ;
    ANTENNAPARTIALMETALAREA 4.0627 LAYER met2  ;
    ANTENNAPARTIALMETALSIDEAREA 20.2055 LAYER met2  ;
    PORT
      LAYER met2 ;
        RECT 782.160000 0.000000 782.300000 0.485000 ;
    END
  END la_data_out[9]
  PIN la_data_out[8]
    DIRECTION OUTPUT ;
    USE SIGNAL ;
    ANTENNADIFFAREA 0.336 LAYER met2  ;
    ANTENNAPARTIALMETALAREA 4.0627 LAYER met2  ;
    ANTENNAPARTIALMETALSIDEAREA 20.2055 LAYER met2  ;
    PORT
      LAYER met2 ;
        RECT 764.680000 0.000000 764.820000 0.485000 ;
    END
  END la_data_out[8]
  PIN la_data_out[7]
    DIRECTION OUTPUT ;
    USE SIGNAL ;
    ANTENNADIFFAREA 0.336 LAYER met2  ;
    ANTENNAPARTIALMETALAREA 4.0627 LAYER met2  ;
    ANTENNAPARTIALMETALSIDEAREA 20.2055 LAYER met2  ;
    PORT
      LAYER met2 ;
        RECT 747.200000 0.000000 747.340000 0.485000 ;
    END
  END la_data_out[7]
  PIN la_data_out[6]
    DIRECTION OUTPUT ;
    USE SIGNAL ;
    ANTENNADIFFAREA 0.336 LAYER met2  ;
    ANTENNAPARTIALMETALAREA 4.3203 LAYER met2  ;
    ANTENNAPARTIALMETALSIDEAREA 21.4935 LAYER met2  ;
    PORT
      LAYER met2 ;
        RECT 729.720000 0.000000 729.860000 0.485000 ;
    END
  END la_data_out[6]
  PIN la_data_out[5]
    DIRECTION OUTPUT ;
    USE SIGNAL ;
    ANTENNADIFFAREA 0.336 LAYER met2  ;
    ANTENNAPARTIALMETALAREA 4.1915 LAYER met2  ;
    ANTENNAPARTIALMETALSIDEAREA 20.8495 LAYER met2  ;
    PORT
      LAYER met2 ;
        RECT 712.240000 0.000000 712.380000 0.485000 ;
    END
  END la_data_out[5]
  PIN la_data_out[4]
    DIRECTION OUTPUT ;
    USE SIGNAL ;
    ANTENNADIFFAREA 0.336 LAYER met2  ;
    ANTENNAPARTIALMETALAREA 4.0627 LAYER met2  ;
    ANTENNAPARTIALMETALSIDEAREA 20.2055 LAYER met2  ;
    PORT
      LAYER met2 ;
        RECT 694.760000 0.000000 694.900000 0.485000 ;
    END
  END la_data_out[4]
  PIN la_data_out[3]
    DIRECTION OUTPUT ;
    USE SIGNAL ;
    ANTENNADIFFAREA 0.336 LAYER met2  ;
    ANTENNAPARTIALMETALAREA 4.0627 LAYER met2  ;
    ANTENNAPARTIALMETALSIDEAREA 20.2055 LAYER met2  ;
    PORT
      LAYER met2 ;
        RECT 677.280000 0.000000 677.420000 0.485000 ;
    END
  END la_data_out[3]
  PIN la_data_out[2]
    DIRECTION OUTPUT ;
    USE SIGNAL ;
    ANTENNADIFFAREA 0.336 LAYER met2  ;
    ANTENNAPARTIALMETALAREA 4.1915 LAYER met2  ;
    ANTENNAPARTIALMETALSIDEAREA 20.8495 LAYER met2  ;
    PORT
      LAYER met2 ;
        RECT 659.800000 0.000000 659.940000 0.485000 ;
    END
  END la_data_out[2]
  PIN la_data_out[1]
    DIRECTION OUTPUT ;
    USE SIGNAL ;
    ANTENNADIFFAREA 0.336 LAYER met2  ;
    ANTENNAPARTIALMETALAREA 4.0627 LAYER met2  ;
    ANTENNAPARTIALMETALSIDEAREA 20.2055 LAYER met2  ;
    PORT
      LAYER met2 ;
        RECT 642.320000 0.000000 642.460000 0.485000 ;
    END
  END la_data_out[1]
  PIN la_data_out[0]
    DIRECTION OUTPUT ;
    USE SIGNAL ;
    ANTENNADIFFAREA 0.336 LAYER met2  ;
    ANTENNAPARTIALMETALAREA 4.0627 LAYER met2  ;
    ANTENNAPARTIALMETALSIDEAREA 20.2055 LAYER met2  ;
    PORT
      LAYER met2 ;
        RECT 624.840000 0.000000 624.980000 0.485000 ;
    END
  END la_data_out[0]
  PIN la_oenb[127]
    DIRECTION INPUT ;
    USE SIGNAL ;
    PORT
      LAYER met2 ;
        RECT 2854.000000 0.000000 2854.140000 0.485000 ;
    END
  END la_oenb[127]
  PIN la_oenb[126]
    DIRECTION INPUT ;
    USE SIGNAL ;
    PORT
      LAYER met2 ;
        RECT 2836.520000 0.000000 2836.660000 0.485000 ;
    END
  END la_oenb[126]
  PIN la_oenb[125]
    DIRECTION INPUT ;
    USE SIGNAL ;
    PORT
      LAYER met2 ;
        RECT 2819.040000 0.000000 2819.180000 0.485000 ;
    END
  END la_oenb[125]
  PIN la_oenb[124]
    DIRECTION INPUT ;
    USE SIGNAL ;
    PORT
      LAYER met2 ;
        RECT 2801.560000 0.000000 2801.700000 0.485000 ;
    END
  END la_oenb[124]
  PIN la_oenb[123]
    DIRECTION INPUT ;
    USE SIGNAL ;
    PORT
      LAYER met2 ;
        RECT 2784.080000 0.000000 2784.220000 0.485000 ;
    END
  END la_oenb[123]
  PIN la_oenb[122]
    DIRECTION INPUT ;
    USE SIGNAL ;
    PORT
      LAYER met2 ;
        RECT 2766.600000 0.000000 2766.740000 0.485000 ;
    END
  END la_oenb[122]
  PIN la_oenb[121]
    DIRECTION INPUT ;
    USE SIGNAL ;
    PORT
      LAYER met2 ;
        RECT 2748.660000 0.000000 2748.800000 0.485000 ;
    END
  END la_oenb[121]
  PIN la_oenb[120]
    DIRECTION INPUT ;
    USE SIGNAL ;
    PORT
      LAYER met2 ;
        RECT 2731.180000 0.000000 2731.320000 0.485000 ;
    END
  END la_oenb[120]
  PIN la_oenb[119]
    DIRECTION INPUT ;
    USE SIGNAL ;
    PORT
      LAYER met2 ;
        RECT 2713.700000 0.000000 2713.840000 0.485000 ;
    END
  END la_oenb[119]
  PIN la_oenb[118]
    DIRECTION INPUT ;
    USE SIGNAL ;
    PORT
      LAYER met2 ;
        RECT 2696.220000 0.000000 2696.360000 0.485000 ;
    END
  END la_oenb[118]
  PIN la_oenb[117]
    DIRECTION INPUT ;
    USE SIGNAL ;
    PORT
      LAYER met2 ;
        RECT 2678.740000 0.000000 2678.880000 0.485000 ;
    END
  END la_oenb[117]
  PIN la_oenb[116]
    DIRECTION INPUT ;
    USE SIGNAL ;
    PORT
      LAYER met2 ;
        RECT 2661.260000 0.000000 2661.400000 0.485000 ;
    END
  END la_oenb[116]
  PIN la_oenb[115]
    DIRECTION INPUT ;
    USE SIGNAL ;
    PORT
      LAYER met2 ;
        RECT 2643.780000 0.000000 2643.920000 0.485000 ;
    END
  END la_oenb[115]
  PIN la_oenb[114]
    DIRECTION INPUT ;
    USE SIGNAL ;
    PORT
      LAYER met2 ;
        RECT 2626.300000 0.000000 2626.440000 0.485000 ;
    END
  END la_oenb[114]
  PIN la_oenb[113]
    DIRECTION INPUT ;
    USE SIGNAL ;
    PORT
      LAYER met2 ;
        RECT 2608.820000 0.000000 2608.960000 0.485000 ;
    END
  END la_oenb[113]
  PIN la_oenb[112]
    DIRECTION INPUT ;
    USE SIGNAL ;
    PORT
      LAYER met2 ;
        RECT 2591.340000 0.000000 2591.480000 0.485000 ;
    END
  END la_oenb[112]
  PIN la_oenb[111]
    DIRECTION INPUT ;
    USE SIGNAL ;
    PORT
      LAYER met2 ;
        RECT 2573.860000 0.000000 2574.000000 0.485000 ;
    END
  END la_oenb[111]
  PIN la_oenb[110]
    DIRECTION INPUT ;
    USE SIGNAL ;
    PORT
      LAYER met2 ;
        RECT 2556.380000 0.000000 2556.520000 0.485000 ;
    END
  END la_oenb[110]
  PIN la_oenb[109]
    DIRECTION INPUT ;
    USE SIGNAL ;
    PORT
      LAYER met2 ;
        RECT 2538.900000 0.000000 2539.040000 0.485000 ;
    END
  END la_oenb[109]
  PIN la_oenb[108]
    DIRECTION INPUT ;
    USE SIGNAL ;
    PORT
      LAYER met2 ;
        RECT 2521.420000 0.000000 2521.560000 0.485000 ;
    END
  END la_oenb[108]
  PIN la_oenb[107]
    DIRECTION INPUT ;
    USE SIGNAL ;
    PORT
      LAYER met2 ;
        RECT 2503.940000 0.000000 2504.080000 0.485000 ;
    END
  END la_oenb[107]
  PIN la_oenb[106]
    DIRECTION INPUT ;
    USE SIGNAL ;
    PORT
      LAYER met2 ;
        RECT 2486.460000 0.000000 2486.600000 0.485000 ;
    END
  END la_oenb[106]
  PIN la_oenb[105]
    DIRECTION INPUT ;
    USE SIGNAL ;
    PORT
      LAYER met2 ;
        RECT 2468.980000 0.000000 2469.120000 0.485000 ;
    END
  END la_oenb[105]
  PIN la_oenb[104]
    DIRECTION INPUT ;
    USE SIGNAL ;
    PORT
      LAYER met2 ;
        RECT 2451.040000 0.000000 2451.180000 0.485000 ;
    END
  END la_oenb[104]
  PIN la_oenb[103]
    DIRECTION INPUT ;
    USE SIGNAL ;
    PORT
      LAYER met2 ;
        RECT 2433.560000 0.000000 2433.700000 0.485000 ;
    END
  END la_oenb[103]
  PIN la_oenb[102]
    DIRECTION INPUT ;
    USE SIGNAL ;
    PORT
      LAYER met2 ;
        RECT 2416.080000 0.000000 2416.220000 0.485000 ;
    END
  END la_oenb[102]
  PIN la_oenb[101]
    DIRECTION INPUT ;
    USE SIGNAL ;
    PORT
      LAYER met2 ;
        RECT 2398.600000 0.000000 2398.740000 0.485000 ;
    END
  END la_oenb[101]
  PIN la_oenb[100]
    DIRECTION INPUT ;
    USE SIGNAL ;
    PORT
      LAYER met2 ;
        RECT 2381.120000 0.000000 2381.260000 0.485000 ;
    END
  END la_oenb[100]
  PIN la_oenb[99]
    DIRECTION INPUT ;
    USE SIGNAL ;
    PORT
      LAYER met2 ;
        RECT 2363.640000 0.000000 2363.780000 0.485000 ;
    END
  END la_oenb[99]
  PIN la_oenb[98]
    DIRECTION INPUT ;
    USE SIGNAL ;
    PORT
      LAYER met2 ;
        RECT 2346.160000 0.000000 2346.300000 0.485000 ;
    END
  END la_oenb[98]
  PIN la_oenb[97]
    DIRECTION INPUT ;
    USE SIGNAL ;
    PORT
      LAYER met2 ;
        RECT 2328.680000 0.000000 2328.820000 0.485000 ;
    END
  END la_oenb[97]
  PIN la_oenb[96]
    DIRECTION INPUT ;
    USE SIGNAL ;
    PORT
      LAYER met2 ;
        RECT 2311.200000 0.000000 2311.340000 0.485000 ;
    END
  END la_oenb[96]
  PIN la_oenb[95]
    DIRECTION INPUT ;
    USE SIGNAL ;
    PORT
      LAYER met2 ;
        RECT 2293.720000 0.000000 2293.860000 0.485000 ;
    END
  END la_oenb[95]
  PIN la_oenb[94]
    DIRECTION INPUT ;
    USE SIGNAL ;
    PORT
      LAYER met2 ;
        RECT 2276.240000 0.000000 2276.380000 0.485000 ;
    END
  END la_oenb[94]
  PIN la_oenb[93]
    DIRECTION INPUT ;
    USE SIGNAL ;
    PORT
      LAYER met2 ;
        RECT 2258.760000 0.000000 2258.900000 0.485000 ;
    END
  END la_oenb[93]
  PIN la_oenb[92]
    DIRECTION INPUT ;
    USE SIGNAL ;
    PORT
      LAYER met2 ;
        RECT 2241.280000 0.000000 2241.420000 0.485000 ;
    END
  END la_oenb[92]
  PIN la_oenb[91]
    DIRECTION INPUT ;
    USE SIGNAL ;
    PORT
      LAYER met2 ;
        RECT 2223.800000 0.000000 2223.940000 0.485000 ;
    END
  END la_oenb[91]
  PIN la_oenb[90]
    DIRECTION INPUT ;
    USE SIGNAL ;
    PORT
      LAYER met2 ;
        RECT 2206.320000 0.000000 2206.460000 0.485000 ;
    END
  END la_oenb[90]
  PIN la_oenb[89]
    DIRECTION INPUT ;
    USE SIGNAL ;
    PORT
      LAYER met2 ;
        RECT 2188.840000 0.000000 2188.980000 0.485000 ;
    END
  END la_oenb[89]
  PIN la_oenb[88]
    DIRECTION INPUT ;
    USE SIGNAL ;
    PORT
      LAYER met2 ;
        RECT 2171.360000 0.000000 2171.500000 0.485000 ;
    END
  END la_oenb[88]
  PIN la_oenb[87]
    DIRECTION INPUT ;
    USE SIGNAL ;
    PORT
      LAYER met2 ;
        RECT 2153.880000 0.000000 2154.020000 0.485000 ;
    END
  END la_oenb[87]
  PIN la_oenb[86]
    DIRECTION INPUT ;
    USE SIGNAL ;
    PORT
      LAYER met2 ;
        RECT 2135.940000 0.000000 2136.080000 0.485000 ;
    END
  END la_oenb[86]
  PIN la_oenb[85]
    DIRECTION INPUT ;
    USE SIGNAL ;
    PORT
      LAYER met2 ;
        RECT 2118.460000 0.000000 2118.600000 0.485000 ;
    END
  END la_oenb[85]
  PIN la_oenb[84]
    DIRECTION INPUT ;
    USE SIGNAL ;
    PORT
      LAYER met2 ;
        RECT 2100.980000 0.000000 2101.120000 0.485000 ;
    END
  END la_oenb[84]
  PIN la_oenb[83]
    DIRECTION INPUT ;
    USE SIGNAL ;
    PORT
      LAYER met2 ;
        RECT 2083.500000 0.000000 2083.640000 0.485000 ;
    END
  END la_oenb[83]
  PIN la_oenb[82]
    DIRECTION INPUT ;
    USE SIGNAL ;
    PORT
      LAYER met2 ;
        RECT 2066.020000 0.000000 2066.160000 0.485000 ;
    END
  END la_oenb[82]
  PIN la_oenb[81]
    DIRECTION INPUT ;
    USE SIGNAL ;
    PORT
      LAYER met2 ;
        RECT 2048.540000 0.000000 2048.680000 0.485000 ;
    END
  END la_oenb[81]
  PIN la_oenb[80]
    DIRECTION INPUT ;
    USE SIGNAL ;
    PORT
      LAYER met2 ;
        RECT 2031.060000 0.000000 2031.200000 0.485000 ;
    END
  END la_oenb[80]
  PIN la_oenb[79]
    DIRECTION INPUT ;
    USE SIGNAL ;
    PORT
      LAYER met2 ;
        RECT 2013.580000 0.000000 2013.720000 0.485000 ;
    END
  END la_oenb[79]
  PIN la_oenb[78]
    DIRECTION INPUT ;
    USE SIGNAL ;
    PORT
      LAYER met2 ;
        RECT 1996.100000 0.000000 1996.240000 0.485000 ;
    END
  END la_oenb[78]
  PIN la_oenb[77]
    DIRECTION INPUT ;
    USE SIGNAL ;
    PORT
      LAYER met2 ;
        RECT 1978.620000 0.000000 1978.760000 0.485000 ;
    END
  END la_oenb[77]
  PIN la_oenb[76]
    DIRECTION INPUT ;
    USE SIGNAL ;
    PORT
      LAYER met2 ;
        RECT 1961.140000 0.000000 1961.280000 0.485000 ;
    END
  END la_oenb[76]
  PIN la_oenb[75]
    DIRECTION INPUT ;
    USE SIGNAL ;
    PORT
      LAYER met2 ;
        RECT 1943.660000 0.000000 1943.800000 0.485000 ;
    END
  END la_oenb[75]
  PIN la_oenb[74]
    DIRECTION INPUT ;
    USE SIGNAL ;
    PORT
      LAYER met2 ;
        RECT 1926.180000 0.000000 1926.320000 0.485000 ;
    END
  END la_oenb[74]
  PIN la_oenb[73]
    DIRECTION INPUT ;
    USE SIGNAL ;
    PORT
      LAYER met2 ;
        RECT 1908.700000 0.000000 1908.840000 0.485000 ;
    END
  END la_oenb[73]
  PIN la_oenb[72]
    DIRECTION INPUT ;
    USE SIGNAL ;
    PORT
      LAYER met2 ;
        RECT 1891.220000 0.000000 1891.360000 0.485000 ;
    END
  END la_oenb[72]
  PIN la_oenb[71]
    DIRECTION INPUT ;
    USE SIGNAL ;
    PORT
      LAYER met2 ;
        RECT 1873.740000 0.000000 1873.880000 0.485000 ;
    END
  END la_oenb[71]
  PIN la_oenb[70]
    DIRECTION INPUT ;
    USE SIGNAL ;
    PORT
      LAYER met2 ;
        RECT 1856.260000 0.000000 1856.400000 0.485000 ;
    END
  END la_oenb[70]
  PIN la_oenb[69]
    DIRECTION INPUT ;
    USE SIGNAL ;
    PORT
      LAYER met2 ;
        RECT 1838.320000 0.000000 1838.460000 0.485000 ;
    END
  END la_oenb[69]
  PIN la_oenb[68]
    DIRECTION INPUT ;
    USE SIGNAL ;
    PORT
      LAYER met2 ;
        RECT 1820.840000 0.000000 1820.980000 0.485000 ;
    END
  END la_oenb[68]
  PIN la_oenb[67]
    DIRECTION INPUT ;
    USE SIGNAL ;
    PORT
      LAYER met2 ;
        RECT 1803.360000 0.000000 1803.500000 0.485000 ;
    END
  END la_oenb[67]
  PIN la_oenb[66]
    DIRECTION INPUT ;
    USE SIGNAL ;
    PORT
      LAYER met2 ;
        RECT 1785.880000 0.000000 1786.020000 0.485000 ;
    END
  END la_oenb[66]
  PIN la_oenb[65]
    DIRECTION INPUT ;
    USE SIGNAL ;
    PORT
      LAYER met2 ;
        RECT 1768.400000 0.000000 1768.540000 0.485000 ;
    END
  END la_oenb[65]
  PIN la_oenb[64]
    DIRECTION INPUT ;
    USE SIGNAL ;
    PORT
      LAYER met2 ;
        RECT 1750.920000 0.000000 1751.060000 0.485000 ;
    END
  END la_oenb[64]
  PIN la_oenb[63]
    DIRECTION INPUT ;
    USE SIGNAL ;
    PORT
      LAYER met2 ;
        RECT 1733.440000 0.000000 1733.580000 0.485000 ;
    END
  END la_oenb[63]
  PIN la_oenb[62]
    DIRECTION INPUT ;
    USE SIGNAL ;
    PORT
      LAYER met2 ;
        RECT 1715.960000 0.000000 1716.100000 0.485000 ;
    END
  END la_oenb[62]
  PIN la_oenb[61]
    DIRECTION INPUT ;
    USE SIGNAL ;
    PORT
      LAYER met2 ;
        RECT 1698.480000 0.000000 1698.620000 0.485000 ;
    END
  END la_oenb[61]
  PIN la_oenb[60]
    DIRECTION INPUT ;
    USE SIGNAL ;
    PORT
      LAYER met2 ;
        RECT 1681.000000 0.000000 1681.140000 0.485000 ;
    END
  END la_oenb[60]
  PIN la_oenb[59]
    DIRECTION INPUT ;
    USE SIGNAL ;
    PORT
      LAYER met2 ;
        RECT 1663.520000 0.000000 1663.660000 0.485000 ;
    END
  END la_oenb[59]
  PIN la_oenb[58]
    DIRECTION INPUT ;
    USE SIGNAL ;
    PORT
      LAYER met2 ;
        RECT 1646.040000 0.000000 1646.180000 0.485000 ;
    END
  END la_oenb[58]
  PIN la_oenb[57]
    DIRECTION INPUT ;
    USE SIGNAL ;
    PORT
      LAYER met2 ;
        RECT 1628.560000 0.000000 1628.700000 0.485000 ;
    END
  END la_oenb[57]
  PIN la_oenb[56]
    DIRECTION INPUT ;
    USE SIGNAL ;
    PORT
      LAYER met2 ;
        RECT 1611.080000 0.000000 1611.220000 0.485000 ;
    END
  END la_oenb[56]
  PIN la_oenb[55]
    DIRECTION INPUT ;
    USE SIGNAL ;
    PORT
      LAYER met2 ;
        RECT 1593.600000 0.000000 1593.740000 0.485000 ;
    END
  END la_oenb[55]
  PIN la_oenb[54]
    DIRECTION INPUT ;
    USE SIGNAL ;
    PORT
      LAYER met2 ;
        RECT 1576.120000 0.000000 1576.260000 0.485000 ;
    END
  END la_oenb[54]
  PIN la_oenb[53]
    DIRECTION INPUT ;
    USE SIGNAL ;
    PORT
      LAYER met2 ;
        RECT 1558.640000 0.000000 1558.780000 0.485000 ;
    END
  END la_oenb[53]
  PIN la_oenb[52]
    DIRECTION INPUT ;
    USE SIGNAL ;
    PORT
      LAYER met2 ;
        RECT 1541.160000 0.000000 1541.300000 0.485000 ;
    END
  END la_oenb[52]
  PIN la_oenb[51]
    DIRECTION INPUT ;
    USE SIGNAL ;
    PORT
      LAYER met2 ;
        RECT 1523.220000 0.000000 1523.360000 0.485000 ;
    END
  END la_oenb[51]
  PIN la_oenb[50]
    DIRECTION INPUT ;
    USE SIGNAL ;
    PORT
      LAYER met2 ;
        RECT 1505.740000 0.000000 1505.880000 0.485000 ;
    END
  END la_oenb[50]
  PIN la_oenb[49]
    DIRECTION INPUT ;
    USE SIGNAL ;
    PORT
      LAYER met2 ;
        RECT 1488.260000 0.000000 1488.400000 0.485000 ;
    END
  END la_oenb[49]
  PIN la_oenb[48]
    DIRECTION INPUT ;
    USE SIGNAL ;
    PORT
      LAYER met2 ;
        RECT 1470.780000 0.000000 1470.920000 0.485000 ;
    END
  END la_oenb[48]
  PIN la_oenb[47]
    DIRECTION INPUT ;
    USE SIGNAL ;
    PORT
      LAYER met2 ;
        RECT 1453.300000 0.000000 1453.440000 0.485000 ;
    END
  END la_oenb[47]
  PIN la_oenb[46]
    DIRECTION INPUT ;
    USE SIGNAL ;
    PORT
      LAYER met2 ;
        RECT 1435.820000 0.000000 1435.960000 0.485000 ;
    END
  END la_oenb[46]
  PIN la_oenb[45]
    DIRECTION INPUT ;
    USE SIGNAL ;
    PORT
      LAYER met2 ;
        RECT 1418.340000 0.000000 1418.480000 0.485000 ;
    END
  END la_oenb[45]
  PIN la_oenb[44]
    DIRECTION INPUT ;
    USE SIGNAL ;
    PORT
      LAYER met2 ;
        RECT 1400.860000 0.000000 1401.000000 0.485000 ;
    END
  END la_oenb[44]
  PIN la_oenb[43]
    DIRECTION INPUT ;
    USE SIGNAL ;
    PORT
      LAYER met2 ;
        RECT 1383.380000 0.000000 1383.520000 0.485000 ;
    END
  END la_oenb[43]
  PIN la_oenb[42]
    DIRECTION INPUT ;
    USE SIGNAL ;
    PORT
      LAYER met2 ;
        RECT 1365.900000 0.000000 1366.040000 0.485000 ;
    END
  END la_oenb[42]
  PIN la_oenb[41]
    DIRECTION INPUT ;
    USE SIGNAL ;
    PORT
      LAYER met2 ;
        RECT 1348.420000 0.000000 1348.560000 0.485000 ;
    END
  END la_oenb[41]
  PIN la_oenb[40]
    DIRECTION INPUT ;
    USE SIGNAL ;
    PORT
      LAYER met2 ;
        RECT 1330.940000 0.000000 1331.080000 0.485000 ;
    END
  END la_oenb[40]
  PIN la_oenb[39]
    DIRECTION INPUT ;
    USE SIGNAL ;
    PORT
      LAYER met2 ;
        RECT 1313.460000 0.000000 1313.600000 0.485000 ;
    END
  END la_oenb[39]
  PIN la_oenb[38]
    DIRECTION INPUT ;
    USE SIGNAL ;
    PORT
      LAYER met2 ;
        RECT 1295.980000 0.000000 1296.120000 0.485000 ;
    END
  END la_oenb[38]
  PIN la_oenb[37]
    DIRECTION INPUT ;
    USE SIGNAL ;
    PORT
      LAYER met2 ;
        RECT 1278.500000 0.000000 1278.640000 0.485000 ;
    END
  END la_oenb[37]
  PIN la_oenb[36]
    DIRECTION INPUT ;
    USE SIGNAL ;
    PORT
      LAYER met2 ;
        RECT 1261.020000 0.000000 1261.160000 0.485000 ;
    END
  END la_oenb[36]
  PIN la_oenb[35]
    DIRECTION INPUT ;
    USE SIGNAL ;
    PORT
      LAYER met2 ;
        RECT 1243.540000 0.000000 1243.680000 0.485000 ;
    END
  END la_oenb[35]
  PIN la_oenb[34]
    DIRECTION INPUT ;
    USE SIGNAL ;
    PORT
      LAYER met2 ;
        RECT 1225.600000 0.000000 1225.740000 0.485000 ;
    END
  END la_oenb[34]
  PIN la_oenb[33]
    DIRECTION INPUT ;
    USE SIGNAL ;
    PORT
      LAYER met2 ;
        RECT 1208.120000 0.000000 1208.260000 0.485000 ;
    END
  END la_oenb[33]
  PIN la_oenb[32]
    DIRECTION INPUT ;
    USE SIGNAL ;
    PORT
      LAYER met2 ;
        RECT 1190.640000 0.000000 1190.780000 0.485000 ;
    END
  END la_oenb[32]
  PIN la_oenb[31]
    DIRECTION INPUT ;
    USE SIGNAL ;
    PORT
      LAYER met2 ;
        RECT 1173.160000 0.000000 1173.300000 0.485000 ;
    END
  END la_oenb[31]
  PIN la_oenb[30]
    DIRECTION INPUT ;
    USE SIGNAL ;
    PORT
      LAYER met2 ;
        RECT 1155.680000 0.000000 1155.820000 0.485000 ;
    END
  END la_oenb[30]
  PIN la_oenb[29]
    DIRECTION INPUT ;
    USE SIGNAL ;
    PORT
      LAYER met2 ;
        RECT 1138.200000 0.000000 1138.340000 0.485000 ;
    END
  END la_oenb[29]
  PIN la_oenb[28]
    DIRECTION INPUT ;
    USE SIGNAL ;
    PORT
      LAYER met2 ;
        RECT 1120.720000 0.000000 1120.860000 0.485000 ;
    END
  END la_oenb[28]
  PIN la_oenb[27]
    DIRECTION INPUT ;
    USE SIGNAL ;
    PORT
      LAYER met2 ;
        RECT 1103.240000 0.000000 1103.380000 0.485000 ;
    END
  END la_oenb[27]
  PIN la_oenb[26]
    DIRECTION INPUT ;
    USE SIGNAL ;
    PORT
      LAYER met2 ;
        RECT 1085.760000 0.000000 1085.900000 0.485000 ;
    END
  END la_oenb[26]
  PIN la_oenb[25]
    DIRECTION INPUT ;
    USE SIGNAL ;
    PORT
      LAYER met2 ;
        RECT 1068.280000 0.000000 1068.420000 0.485000 ;
    END
  END la_oenb[25]
  PIN la_oenb[24]
    DIRECTION INPUT ;
    USE SIGNAL ;
    PORT
      LAYER met2 ;
        RECT 1050.800000 0.000000 1050.940000 0.485000 ;
    END
  END la_oenb[24]
  PIN la_oenb[23]
    DIRECTION INPUT ;
    USE SIGNAL ;
    PORT
      LAYER met2 ;
        RECT 1033.320000 0.000000 1033.460000 0.485000 ;
    END
  END la_oenb[23]
  PIN la_oenb[22]
    DIRECTION INPUT ;
    USE SIGNAL ;
    PORT
      LAYER met2 ;
        RECT 1015.840000 0.000000 1015.980000 0.485000 ;
    END
  END la_oenb[22]
  PIN la_oenb[21]
    DIRECTION INPUT ;
    USE SIGNAL ;
    PORT
      LAYER met2 ;
        RECT 998.360000 0.000000 998.500000 0.485000 ;
    END
  END la_oenb[21]
  PIN la_oenb[20]
    DIRECTION INPUT ;
    USE SIGNAL ;
    PORT
      LAYER met2 ;
        RECT 980.880000 0.000000 981.020000 0.485000 ;
    END
  END la_oenb[20]
  PIN la_oenb[19]
    DIRECTION INPUT ;
    USE SIGNAL ;
    PORT
      LAYER met2 ;
        RECT 963.400000 0.000000 963.540000 0.485000 ;
    END
  END la_oenb[19]
  PIN la_oenb[18]
    DIRECTION INPUT ;
    USE SIGNAL ;
    PORT
      LAYER met2 ;
        RECT 945.920000 0.000000 946.060000 0.485000 ;
    END
  END la_oenb[18]
  PIN la_oenb[17]
    DIRECTION INPUT ;
    USE SIGNAL ;
    PORT
      LAYER met2 ;
        RECT 928.440000 0.000000 928.580000 0.485000 ;
    END
  END la_oenb[17]
  PIN la_oenb[16]
    DIRECTION INPUT ;
    USE SIGNAL ;
    PORT
      LAYER met2 ;
        RECT 910.500000 0.000000 910.640000 0.485000 ;
    END
  END la_oenb[16]
  PIN la_oenb[15]
    DIRECTION INPUT ;
    USE SIGNAL ;
    PORT
      LAYER met2 ;
        RECT 893.020000 0.000000 893.160000 0.485000 ;
    END
  END la_oenb[15]
  PIN la_oenb[14]
    DIRECTION INPUT ;
    USE SIGNAL ;
    PORT
      LAYER met2 ;
        RECT 875.540000 0.000000 875.680000 0.485000 ;
    END
  END la_oenb[14]
  PIN la_oenb[13]
    DIRECTION INPUT ;
    USE SIGNAL ;
    PORT
      LAYER met2 ;
        RECT 858.060000 0.000000 858.200000 0.485000 ;
    END
  END la_oenb[13]
  PIN la_oenb[12]
    DIRECTION INPUT ;
    USE SIGNAL ;
    PORT
      LAYER met2 ;
        RECT 840.580000 0.000000 840.720000 0.485000 ;
    END
  END la_oenb[12]
  PIN la_oenb[11]
    DIRECTION INPUT ;
    USE SIGNAL ;
    PORT
      LAYER met2 ;
        RECT 823.100000 0.000000 823.240000 0.485000 ;
    END
  END la_oenb[11]
  PIN la_oenb[10]
    DIRECTION INPUT ;
    USE SIGNAL ;
    PORT
      LAYER met2 ;
        RECT 805.620000 0.000000 805.760000 0.485000 ;
    END
  END la_oenb[10]
  PIN la_oenb[9]
    DIRECTION INPUT ;
    USE SIGNAL ;
    PORT
      LAYER met2 ;
        RECT 788.140000 0.000000 788.280000 0.485000 ;
    END
  END la_oenb[9]
  PIN la_oenb[8]
    DIRECTION INPUT ;
    USE SIGNAL ;
    PORT
      LAYER met2 ;
        RECT 770.660000 0.000000 770.800000 0.485000 ;
    END
  END la_oenb[8]
  PIN la_oenb[7]
    DIRECTION INPUT ;
    USE SIGNAL ;
    PORT
      LAYER met2 ;
        RECT 753.180000 0.000000 753.320000 0.485000 ;
    END
  END la_oenb[7]
  PIN la_oenb[6]
    DIRECTION INPUT ;
    USE SIGNAL ;
    PORT
      LAYER met2 ;
        RECT 735.700000 0.000000 735.840000 0.485000 ;
    END
  END la_oenb[6]
  PIN la_oenb[5]
    DIRECTION INPUT ;
    USE SIGNAL ;
    PORT
      LAYER met2 ;
        RECT 718.220000 0.000000 718.360000 0.485000 ;
    END
  END la_oenb[5]
  PIN la_oenb[4]
    DIRECTION INPUT ;
    USE SIGNAL ;
    PORT
      LAYER met2 ;
        RECT 700.740000 0.000000 700.880000 0.485000 ;
    END
  END la_oenb[4]
  PIN la_oenb[3]
    DIRECTION INPUT ;
    USE SIGNAL ;
    PORT
      LAYER met2 ;
        RECT 683.260000 0.000000 683.400000 0.485000 ;
    END
  END la_oenb[3]
  PIN la_oenb[2]
    DIRECTION INPUT ;
    USE SIGNAL ;
    PORT
      LAYER met2 ;
        RECT 665.780000 0.000000 665.920000 0.485000 ;
    END
  END la_oenb[2]
  PIN la_oenb[1]
    DIRECTION INPUT ;
    USE SIGNAL ;
    PORT
      LAYER met2 ;
        RECT 648.300000 0.000000 648.440000 0.485000 ;
    END
  END la_oenb[1]
  PIN la_oenb[0]
    DIRECTION INPUT ;
    USE SIGNAL ;
    PORT
      LAYER met2 ;
        RECT 630.820000 0.000000 630.960000 0.485000 ;
    END
  END la_oenb[0]
  PIN io_in[37]
    DIRECTION INPUT ;
    USE SIGNAL ;
    PORT
      LAYER met3 ;
        RECT 0.000000 131.060000 0.800000 131.360000 ;
    END
  END io_in[37]
  PIN io_in[36]
    DIRECTION INPUT ;
    USE SIGNAL ;
    PORT
      LAYER met3 ;
        RECT 0.000000 327.480000 0.800000 327.780000 ;
    END
  END io_in[36]
  PIN io_in[35]
    DIRECTION INPUT ;
    USE SIGNAL ;
    PORT
      LAYER met3 ;
        RECT 0.000000 523.900000 0.800000 524.200000 ;
    END
  END io_in[35]
  PIN io_in[34]
    DIRECTION INPUT ;
    USE SIGNAL ;
    PORT
      LAYER met3 ;
        RECT 0.000000 785.590000 0.800000 785.890000 ;
    END
  END io_in[34]
  PIN io_in[33]
    DIRECTION INPUT ;
    USE SIGNAL ;
    PORT
      LAYER met3 ;
        RECT 0.000000 1047.280000 0.800000 1047.580000 ;
    END
  END io_in[33]
  PIN io_in[32]
    DIRECTION INPUT ;
    USE SIGNAL ;
    PORT
      LAYER met3 ;
        RECT 0.000000 1309.580000 0.800000 1309.880000 ;
    END
  END io_in[32]
  PIN io_in[31]
    DIRECTION INPUT ;
    USE SIGNAL ;
    PORT
      LAYER met3 ;
        RECT 0.000000 1571.270000 0.800000 1571.570000 ;
    END
  END io_in[31]
  PIN io_in[30]
    DIRECTION INPUT ;
    USE SIGNAL ;
    PORT
      LAYER met3 ;
        RECT 0.000000 1832.960000 0.800000 1833.260000 ;
    END
  END io_in[30]
  PIN io_in[29]
    DIRECTION INPUT ;
    USE SIGNAL ;
    PORT
      LAYER met3 ;
        RECT 0.000000 2094.650000 0.800000 2094.950000 ;
    END
  END io_in[29]
  PIN io_in[28]
    DIRECTION INPUT ;
    USE SIGNAL ;
    PORT
      LAYER met3 ;
        RECT 0.000000 2356.340000 0.800000 2356.640000 ;
    END
  END io_in[28]
  PIN io_in[27]
    DIRECTION INPUT ;
    USE SIGNAL ;
    PORT
      LAYER met3 ;
        RECT 0.000000 2618.640000 0.800000 2618.940000 ;
    END
  END io_in[27]
  PIN io_in[26]
    DIRECTION INPUT ;
    USE SIGNAL ;
    PORT
      LAYER met3 ;
        RECT 0.000000 2880.330000 0.800000 2880.630000 ;
    END
  END io_in[26]
  PIN io_in[25]
    DIRECTION INPUT ;
    USE SIGNAL ;
    PORT
      LAYER met3 ;
        RECT 0.000000 3142.020000 0.800000 3142.320000 ;
    END
  END io_in[25]
  PIN io_in[24]
    DIRECTION INPUT ;
    USE SIGNAL ;
    PORT
      LAYER met3 ;
        RECT 0.000000 3403.710000 0.800000 3404.010000 ;
    END
  END io_in[24]
  PIN io_in[23]
    DIRECTION INPUT ;
    USE SIGNAL ;
    PORT
      LAYER met2 ;
        RECT 163.460000 3469.555000 163.600000 3470.040000 ;
    END
  END io_in[23]
  PIN io_in[22]
    DIRECTION INPUT ;
    USE SIGNAL ;
    PORT
      LAYER met2 ;
        RECT 490.060000 3469.555000 490.200000 3470.040000 ;
    END
  END io_in[22]
  PIN io_in[21]
    DIRECTION INPUT ;
    USE SIGNAL ;
    PORT
      LAYER met2 ;
        RECT 816.660000 3469.555000 816.800000 3470.040000 ;
    END
  END io_in[21]
  PIN io_in[20]
    DIRECTION INPUT ;
    USE SIGNAL ;
    PORT
      LAYER met2 ;
        RECT 1143.720000 3469.555000 1143.860000 3470.040000 ;
    END
  END io_in[20]
  PIN io_in[19]
    DIRECTION INPUT ;
    USE SIGNAL ;
    ANTENNAPARTIALMETALAREA 5.1758 LAYER met2  ;
    ANTENNAPARTIALMETALSIDEAREA 25.718 LAYER met2  ;
    ANTENNAPARTIALCUTAREA 0.04 LAYER via2  ;
    ANTENNAPARTIALMETALAREA 1.9128 LAYER met3  ;
    ANTENNAPARTIALMETALSIDEAREA 10.672 LAYER met3  ;
    ANTENNAMODEL OXIDE1 ;
    ANTENNAGATEAREA 0.576 LAYER met3  ;
    ANTENNAMAXAREACAR 4.32622 LAYER met3  ;
    ANTENNAMAXSIDEAREACAR 21.2292 LAYER met3  ;
    ANTENNAMAXCUTCAR 0.158681 LAYER via3  ;
    PORT
      LAYER met2 ;
        RECT 1470.320000 3469.555000 1470.460000 3470.040000 ;
    END
  END io_in[19]
  PIN io_in[18]
    DIRECTION INPUT ;
    USE SIGNAL ;
    ANTENNAPARTIALMETALAREA 5.9008 LAYER met2  ;
    ANTENNAPARTIALMETALSIDEAREA 29.225 LAYER met2  ;
    ANTENNAPARTIALCUTAREA 0.04 LAYER via2  ;
    ANTENNAPARTIALMETALAREA 4.126 LAYER met3  ;
    ANTENNAPARTIALMETALSIDEAREA 22.472 LAYER met3  ;
    ANTENNAPARTIALCUTAREA 0.04 LAYER via3  ;
    ANTENNADIFFAREA 0.4347 LAYER met4  ;
    ANTENNAPARTIALMETALAREA 38.9478 LAYER met4  ;
    ANTENNAPARTIALMETALSIDEAREA 208.192 LAYER met4  ;
    ANTENNAMODEL OXIDE1 ;
    ANTENNAGATEAREA 0.159 LAYER met4  ;
    ANTENNAMAXAREACAR 299.745 LAYER met4  ;
    ANTENNAMAXSIDEAREACAR 1543.14 LAYER met4  ;
    ANTENNAMAXCUTCAR 0.826415 LAYER via4  ;
    PORT
      LAYER met2 ;
        RECT 1797.380000 3469.555000 1797.520000 3470.040000 ;
    END
  END io_in[18]
  PIN io_in[17]
    DIRECTION INPUT ;
    USE SIGNAL ;
    ANTENNAPARTIALMETALAREA 4.5213 LAYER met2  ;
    ANTENNAPARTIALMETALSIDEAREA 22.4455 LAYER met2  ;
    ANTENNAPARTIALCUTAREA 0.04 LAYER via2  ;
    ANTENNAPARTIALMETALAREA 0.883 LAYER met3  ;
    ANTENNAPARTIALMETALSIDEAREA 5.176 LAYER met3  ;
    ANTENNAPARTIALCUTAREA 0.04 LAYER via3  ;
    ANTENNADIFFAREA 1.3041 LAYER met4  ;
    ANTENNAPARTIALMETALAREA 124.367 LAYER met4  ;
    ANTENNAPARTIALMETALSIDEAREA 664.704 LAYER met4  ;
    ANTENNAMODEL OXIDE1 ;
    ANTENNAGATEAREA 0.213 LAYER met4  ;
    ANTENNAMAXAREACAR 641.553 LAYER met4  ;
    ANTENNAMAXSIDEAREACAR 3425.44 LAYER met4  ;
    ANTENNAMAXCUTCAR 0.804695 LAYER via4  ;
    PORT
      LAYER met2 ;
        RECT 2123.980000 3469.555000 2124.120000 3470.040000 ;
    END
  END io_in[17]
  PIN io_in[16]
    DIRECTION INPUT ;
    USE SIGNAL ;
    ANTENNAPARTIALMETALAREA 0.5703 LAYER met2  ;
    ANTENNAPARTIALMETALSIDEAREA 2.5725 LAYER met2  ;
    ANTENNAPARTIALCUTAREA 0.04 LAYER via2  ;
    ANTENNAPARTIALMETALAREA 0.745 LAYER met3  ;
    ANTENNAPARTIALMETALSIDEAREA 4.44 LAYER met3  ;
    ANTENNAPARTIALCUTAREA 0.04 LAYER via3  ;
    ANTENNAPARTIALMETALAREA 3.0406 LAYER met4  ;
    ANTENNAPARTIALMETALSIDEAREA 13.032 LAYER met4  ;
    ANTENNAPARTIALCUTAREA 0.64 LAYER via4  ;
    ANTENNAPARTIALMETALAREA 5.872 LAYER met5  ;
    ANTENNAPARTIALMETALSIDEAREA 12.648 LAYER met5  ;
    ANTENNAMODEL OXIDE1 ;
    ANTENNAGATEAREA 0.159 LAYER met5  ;
    ANTENNAMAXAREACAR 157.907 LAYER met5  ;
    ANTENNAMAXSIDEAREACAR 686.981 LAYER met5  ;
    PORT
      LAYER met2 ;
        RECT 2451.040000 3469.555000 2451.180000 3470.040000 ;
    END
  END io_in[16]
  PIN io_in[15]
    DIRECTION INPUT ;
    USE SIGNAL ;
    ANTENNAPARTIALMETALAREA 69.0674 LAYER met2  ;
    ANTENNAPARTIALMETALSIDEAREA 345.058 LAYER met2  ;
    ANTENNAPARTIALCUTAREA 0.04 LAYER via2  ;
    ANTENNAPARTIALMETALAREA 19.1628 LAYER met3  ;
    ANTENNAPARTIALMETALSIDEAREA 102.672 LAYER met3  ;
    ANTENNAMODEL OXIDE1 ;
    ANTENNAGATEAREA 0.315 LAYER met3  ;
    ANTENNAMAXAREACAR 65.3025 LAYER met3  ;
    ANTENNAMAXSIDEAREACAR 344.632 LAYER met3  ;
    ANTENNAMAXCUTCAR 0.290159 LAYER via3  ;
    PORT
      LAYER met2 ;
        RECT 2777.640000 3469.555000 2777.780000 3470.040000 ;
    END
  END io_in[15]
  PIN io_in[14]
    DIRECTION INPUT ;
    USE SIGNAL ;
    ANTENNADIFFAREA 0.8694 LAYER met3  ;
    ANTENNAPARTIALMETALAREA 0.1644 LAYER met3  ;
    ANTENNAPARTIALMETALSIDEAREA 0.872 LAYER met3  ;
    ANTENNAMODEL OXIDE1 ;
    ANTENNAGATEAREA 0.159 LAYER met3  ;
    ANTENNAMAXAREACAR 626.451 LAYER met3  ;
    ANTENNAMAXSIDEAREACAR 3078.06 LAYER met3  ;
    ANTENNAMAXCUTCAR 0.574843 LAYER via3  ;
    PORT
      LAYER met3 ;
        RECT 2859.020000 3336.610000 2859.820000 3336.910000 ;
    END
  END io_in[14]
  PIN io_in[13]
    DIRECTION INPUT ;
    USE SIGNAL ;
    ANTENNAPARTIALMETALAREA 1.0573 LAYER met3  ;
    ANTENNAPARTIALMETALSIDEAREA 6.104 LAYER met3  ;
    ANTENNAPARTIALCUTAREA 0.04 LAYER via3  ;
    ANTENNAPARTIALMETALAREA 3.0468 LAYER met4  ;
    ANTENNAPARTIALMETALSIDEAREA 16.72 LAYER met4  ;
    ANTENNAMODEL OXIDE1 ;
    ANTENNAGATEAREA 0.159 LAYER met4  ;
    ANTENNAMAXAREACAR 50.5582 LAYER met4  ;
    ANTENNAMAXSIDEAREACAR 256.421 LAYER met4  ;
    ANTENNAMAXCUTCAR 0.826415 LAYER via4  ;
    PORT
      LAYER met3 ;
        RECT 2859.020000 3069.430000 2859.820000 3069.730000 ;
    END
  END io_in[13]
  PIN io_in[12]
    DIRECTION INPUT ;
    USE SIGNAL ;
    ANTENNAPARTIALMETALAREA 10.2174 LAYER met3  ;
    ANTENNAPARTIALMETALSIDEAREA 54.936 LAYER met3  ;
    ANTENNAPARTIALCUTAREA 0.04 LAYER via3  ;
    ANTENNAPARTIALMETALAREA 8.1708 LAYER met4  ;
    ANTENNAPARTIALMETALSIDEAREA 44.048 LAYER met4  ;
    ANTENNAMODEL OXIDE1 ;
    ANTENNAGATEAREA 0.495 LAYER met4  ;
    ANTENNAMAXAREACAR 24.7707 LAYER met4  ;
    ANTENNAMAXSIDEAREACAR 130.418 LAYER met4  ;
    ANTENNAMAXCUTCAR 0.265455 LAYER via4  ;
    PORT
      LAYER met3 ;
        RECT 2859.020000 2802.860000 2859.820000 2803.160000 ;
    END
  END io_in[12]
  PIN io_in[11]
    DIRECTION INPUT ;
    USE SIGNAL ;
    ANTENNADIFFAREA 0.4347 LAYER met3  ;
    ANTENNAPARTIALMETALAREA 8.4444 LAYER met3  ;
    ANTENNAPARTIALMETALSIDEAREA 45.032 LAYER met3  ;
    ANTENNAMODEL OXIDE1 ;
    ANTENNAGATEAREA 0.159 LAYER met3  ;
    ANTENNAMAXAREACAR 379.712 LAYER met3  ;
    ANTENNAMAXSIDEAREACAR 1860.26 LAYER met3  ;
    ANTENNAMAXCUTCAR 0.574843 LAYER via3  ;
    PORT
      LAYER met3 ;
        RECT 2859.020000 2535.680000 2859.820000 2535.980000 ;
    END
  END io_in[11]
  PIN io_in[10]
    DIRECTION INPUT ;
    USE SIGNAL ;
    ANTENNAPARTIALMETALAREA 9.1134 LAYER met3  ;
    ANTENNAPARTIALMETALSIDEAREA 49.048 LAYER met3  ;
    ANTENNAPARTIALCUTAREA 0.04 LAYER via3  ;
    ANTENNAPARTIALMETALAREA 3.9618 LAYER met4  ;
    ANTENNAPARTIALMETALSIDEAREA 21.6 LAYER met4  ;
    ANTENNAMODEL OXIDE1 ;
    ANTENNAGATEAREA 0.1965 LAYER met4  ;
    ANTENNAMAXAREACAR 30.2534 LAYER met4  ;
    ANTENNAMAXSIDEAREACAR 155.323 LAYER met4  ;
    ANTENNAMAXCUTCAR 0.668702 LAYER via4  ;
    PORT
      LAYER met3 ;
        RECT 2859.020000 2269.110000 2859.820000 2269.410000 ;
    END
  END io_in[10]
  PIN io_in[9]
    DIRECTION INPUT ;
    USE SIGNAL ;
    ANTENNAPARTIALMETALAREA 15.2064 LAYER met3  ;
    ANTENNAPARTIALMETALSIDEAREA 81.096 LAYER met3  ;
    ANTENNAMODEL OXIDE1 ;
    ANTENNAGATEAREA 0.498 LAYER met3  ;
    ANTENNAMAXAREACAR 70.6588 LAYER met3  ;
    ANTENNAMAXSIDEAREACAR 352.994 LAYER met3  ;
    ANTENNAMAXCUTCAR 0.488258 LAYER via3  ;
    PORT
      LAYER met3 ;
        RECT 2859.020000 2001.930000 2859.820000 2002.230000 ;
    END
  END io_in[9]
  PIN io_in[8]
    DIRECTION INPUT ;
    USE SIGNAL ;
    ANTENNAPARTIALMETALAREA 42.2596 LAYER met3  ;
    ANTENNAPARTIALMETALSIDEAREA 225.376 LAYER met3  ;
    ANTENNAPARTIALCUTAREA 0.04 LAYER via3  ;
    ANTENNAPARTIALMETALAREA 0.6516 LAYER met4  ;
    ANTENNAPARTIALMETALSIDEAREA 4.416 LAYER met4  ;
    ANTENNAMODEL OXIDE1 ;
    ANTENNAGATEAREA 0.498 LAYER met4  ;
    ANTENNAMAXAREACAR 59.69 LAYER met4  ;
    ANTENNAMAXSIDEAREACAR 291.419 LAYER met4  ;
    ANTENNAMAXCUTCAR 0.74715 LAYER via4  ;
    PORT
      LAYER met3 ;
        RECT 2859.020000 1735.360000 2859.820000 1735.660000 ;
    END
  END io_in[8]
  PIN io_in[7]
    DIRECTION INPUT ;
    USE SIGNAL ;
    ANTENNAPARTIALMETALAREA 0.5533 LAYER met3  ;
    ANTENNAPARTIALMETALSIDEAREA 3.416 LAYER met3  ;
    ANTENNAPARTIALCUTAREA 0.04 LAYER via3  ;
    ANTENNAPARTIALMETALAREA 3.9618 LAYER met4  ;
    ANTENNAPARTIALMETALSIDEAREA 21.6 LAYER met4  ;
    ANTENNAMODEL OXIDE1 ;
    ANTENNAGATEAREA 0.159 LAYER met4  ;
    ANTENNAMAXAREACAR 59.9569 LAYER met4  ;
    ANTENNAMAXSIDEAREACAR 309.748 LAYER met4  ;
    ANTENNAMAXCUTCAR 0.826415 LAYER via4  ;
    PORT
      LAYER met3 ;
        RECT 2859.020000 1468.790000 2859.820000 1469.090000 ;
    END
  END io_in[7]
  PIN io_in[6]
    DIRECTION INPUT ;
    USE SIGNAL ;
    ANTENNAPARTIALMETALAREA 2.155 LAYER met3  ;
    ANTENNAPARTIALMETALSIDEAREA 12.896 LAYER met3  ;
    ANTENNAPARTIALCUTAREA 0.04 LAYER via3  ;
    ANTENNAPARTIALMETALAREA 6.1578 LAYER met4  ;
    ANTENNAPARTIALMETALSIDEAREA 33.312 LAYER met4  ;
    ANTENNAMODEL OXIDE1 ;
    ANTENNAGATEAREA 0.315 LAYER met4  ;
    ANTENNAMAXAREACAR 76.0651 LAYER met4  ;
    ANTENNAMAXSIDEAREACAR 386.879 LAYER met4  ;
    ANTENNAMAXCUTCAR 0.417143 LAYER via4  ;
    PORT
      LAYER met3 ;
        RECT 2859.020000 1201.610000 2859.820000 1201.910000 ;
    END
  END io_in[6]
  PIN io_in[5]
    DIRECTION INPUT ;
    USE SIGNAL ;
    ANTENNAPARTIALMETALAREA 0.4153 LAYER met3  ;
    ANTENNAPARTIALMETALSIDEAREA 2.68 LAYER met3  ;
    ANTENNAPARTIALCUTAREA 0.04 LAYER via3  ;
    ANTENNAPARTIALMETALAREA 4.1448 LAYER met4  ;
    ANTENNAPARTIALMETALSIDEAREA 22.576 LAYER met4  ;
    ANTENNAMODEL OXIDE1 ;
    ANTENNAGATEAREA 0.576 LAYER met4  ;
    ANTENNAMAXAREACAR 18.1224 LAYER met4  ;
    ANTENNAMAXSIDEAREACAR 91.7535 LAYER met4  ;
    ANTENNAMAXCUTCAR 0.228125 LAYER via4  ;
    PORT
      LAYER met3 ;
        RECT 2859.020000 1001.530000 2859.820000 1001.830000 ;
    END
  END io_in[5]
  PIN io_in[4]
    DIRECTION INPUT ;
    USE SIGNAL ;
    ANTENNAPARTIALMETALAREA 1.2474 LAYER met3  ;
    ANTENNAPARTIALMETALSIDEAREA 7.096 LAYER met3  ;
    ANTENNAPARTIALCUTAREA 0.04 LAYER via3  ;
    ANTENNAPARTIALMETALAREA 4.1448 LAYER met4  ;
    ANTENNAPARTIALMETALSIDEAREA 22.576 LAYER met4  ;
    ANTENNAMODEL OXIDE1 ;
    ANTENNAGATEAREA 0.159 LAYER met4  ;
    ANTENNAMAXAREACAR 61.7852 LAYER met4  ;
    ANTENNAMAXSIDEAREACAR 319.145 LAYER met4  ;
    ANTENNAMAXCUTCAR 0.826415 LAYER via4  ;
    PORT
      LAYER met3 ;
        RECT 2859.020000 801.450000 2859.820000 801.750000 ;
    END
  END io_in[4]
  PIN io_in[3]
    DIRECTION INPUT ;
    USE SIGNAL ;
    ANTENNAPARTIALMETALAREA 0.7714 LAYER met3  ;
    ANTENNAPARTIALMETALSIDEAREA 4.576 LAYER met3  ;
    ANTENNAPARTIALCUTAREA 0.04 LAYER via3  ;
    ANTENNAPARTIALMETALAREA 4.3518 LAYER met4  ;
    ANTENNAPARTIALMETALSIDEAREA 23.68 LAYER met4  ;
    ANTENNAMODEL OXIDE1 ;
    ANTENNAGATEAREA 0.576 LAYER met4  ;
    ANTENNAMAXAREACAR 17.7628 LAYER met4  ;
    ANTENNAMAXSIDEAREACAR 90.1163 LAYER met4  ;
    ANTENNAMAXCUTCAR 0.228125 LAYER via4  ;
    PORT
      LAYER met3 ;
        RECT 2859.020000 601.370000 2859.820000 601.670000 ;
    END
  END io_in[3]
  PIN io_in[2]
    DIRECTION INPUT ;
    USE SIGNAL ;
    ANTENNAPARTIALMETALAREA 0.9784 LAYER met3  ;
    ANTENNAPARTIALMETALSIDEAREA 5.68 LAYER met3  ;
    ANTENNAPARTIALCUTAREA 0.04 LAYER via3  ;
    ANTENNADIFFAREA 0.4347 LAYER met4  ;
    ANTENNAPARTIALMETALAREA 5.9748 LAYER met4  ;
    ANTENNAPARTIALMETALSIDEAREA 32.336 LAYER met4  ;
    ANTENNAMODEL OXIDE1 ;
    ANTENNAGATEAREA 0.213 LAYER met4  ;
    ANTENNAMAXAREACAR 165.425 LAYER met4  ;
    ANTENNAMAXSIDEAREACAR 836.629 LAYER met4  ;
    ANTENNAMAXCUTCAR 0.616901 LAYER via4  ;
    PORT
      LAYER met3 ;
        RECT 2859.020000 401.290000 2859.820000 401.590000 ;
    END
  END io_in[2]
  PIN io_in[1]
    DIRECTION INPUT ;
    USE SIGNAL ;
    ANTENNAPARTIALMETALAREA 1.6134 LAYER met3  ;
    ANTENNAPARTIALMETALSIDEAREA 9.048 LAYER met3  ;
    ANTENNAPARTIALCUTAREA 0.04 LAYER via3  ;
    ANTENNAPARTIALMETALAREA 9.4456 LAYER met4  ;
    ANTENNAPARTIALMETALSIDEAREA 47.192 LAYER met4  ;
    ANTENNAPARTIALCUTAREA 0.64 LAYER via4  ;
    ANTENNADIFFAREA 0.4347 LAYER met5  ;
    ANTENNAPARTIALMETALAREA 7.44 LAYER met5  ;
    ANTENNAPARTIALMETALSIDEAREA 15 LAYER met5  ;
    ANTENNAMODEL OXIDE1 ;
    ANTENNAGATEAREA 0.159 LAYER met5  ;
    ANTENNAMAXAREACAR 262.296 LAYER met5  ;
    ANTENNAMAXSIDEAREACAR 1106.94 LAYER met5  ;
    PORT
      LAYER met3 ;
        RECT 2859.020000 201.210000 2859.820000 201.510000 ;
    END
  END io_in[1]
  PIN io_in[0]
    DIRECTION INPUT ;
    USE SIGNAL ;
    ANTENNAPARTIALMETALAREA 0.1644 LAYER met3  ;
    ANTENNAPARTIALMETALSIDEAREA 0.872 LAYER met3  ;
    ANTENNAMODEL OXIDE1 ;
    ANTENNAGATEAREA 0.315 LAYER met3  ;
    ANTENNAMAXAREACAR 15.1517 LAYER met3  ;
    ANTENNAMAXSIDEAREACAR 72.1905 LAYER met3  ;
    ANTENNAMAXCUTCAR 0.290159 LAYER via3  ;
    PORT
      LAYER met3 ;
        RECT 2859.020000 0.520000 2859.820000 0.820000 ;
    END
  END io_in[0]
  PIN io_out[37]
    DIRECTION OUTPUT ;
    USE SIGNAL ;
    ANTENNADIFFAREA 0.336 LAYER met3  ;
    ANTENNAPARTIALMETALAREA 8.8584 LAYER met3  ;
    ANTENNAPARTIALMETALSIDEAREA 47.24 LAYER met3  ;
    PORT
      LAYER met3 ;
        RECT 0.000000 65.790000 0.800000 66.090000 ;
    END
  END io_out[37]
  PIN io_out[36]
    DIRECTION OUTPUT ;
    USE SIGNAL ;
    ANTENNADIFFAREA 0.336 LAYER met3  ;
    ANTENNAPARTIALMETALAREA 0.1644 LAYER met3  ;
    ANTENNAPARTIALMETALSIDEAREA 0.872 LAYER met3  ;
    PORT
      LAYER met3 ;
        RECT 0.000000 262.210000 0.800000 262.510000 ;
    END
  END io_out[36]
  PIN io_out[35]
    DIRECTION OUTPUT ;
    USE SIGNAL ;
    ANTENNADIFFAREA 0.336 LAYER met3  ;
    ANTENNAPARTIALMETALAREA 7.0644 LAYER met3  ;
    ANTENNAPARTIALMETALSIDEAREA 37.672 LAYER met3  ;
    PORT
      LAYER met3 ;
        RECT 0.000000 458.630000 0.800000 458.930000 ;
    END
  END io_out[35]
  PIN io_out[34]
    DIRECTION OUTPUT ;
    USE SIGNAL ;
    ANTENNADIFFAREA 0.336 LAYER met3  ;
    ANTENNAPARTIALMETALAREA 0.1644 LAYER met3  ;
    ANTENNAPARTIALMETALSIDEAREA 0.872 LAYER met3  ;
    PORT
      LAYER met3 ;
        RECT 0.000000 720.320000 0.800000 720.620000 ;
    END
  END io_out[34]
  PIN io_out[33]
    DIRECTION OUTPUT ;
    USE SIGNAL ;
    ANTENNADIFFAREA 0.336 LAYER met3  ;
    ANTENNAPARTIALMETALAREA 0.1644 LAYER met3  ;
    ANTENNAPARTIALMETALSIDEAREA 0.872 LAYER met3  ;
    PORT
      LAYER met3 ;
        RECT 0.000000 982.010000 0.800000 982.310000 ;
    END
  END io_out[33]
  PIN io_out[32]
    DIRECTION OUTPUT ;
    USE SIGNAL ;
    ANTENNADIFFAREA 0.336 LAYER met3  ;
    ANTENNAPARTIALMETALAREA 4.4424 LAYER met3  ;
    ANTENNAPARTIALMETALSIDEAREA 23.688 LAYER met3  ;
    PORT
      LAYER met3 ;
        RECT 0.000000 1243.700000 0.800000 1244.000000 ;
    END
  END io_out[32]
  PIN io_out[31]
    DIRECTION OUTPUT ;
    USE SIGNAL ;
    ANTENNADIFFAREA 0.336 LAYER met3  ;
    ANTENNAPARTIALMETALAREA 3.2004 LAYER met3  ;
    ANTENNAPARTIALMETALSIDEAREA 17.064 LAYER met3  ;
    PORT
      LAYER met3 ;
        RECT 0.000000 1505.390000 0.800000 1505.690000 ;
    END
  END io_out[31]
  PIN io_out[30]
    DIRECTION OUTPUT ;
    USE SIGNAL ;
    ANTENNADIFFAREA 0.336 LAYER met3  ;
    ANTENNAPARTIALMETALAREA 0.1644 LAYER met3  ;
    ANTENNAPARTIALMETALSIDEAREA 0.872 LAYER met3  ;
    PORT
      LAYER met3 ;
        RECT 0.000000 1767.690000 0.800000 1767.990000 ;
    END
  END io_out[30]
  PIN io_out[29]
    DIRECTION OUTPUT ;
    USE SIGNAL ;
    ANTENNAPARTIALMETALAREA 9.4366 LAYER met3  ;
    ANTENNAPARTIALMETALSIDEAREA 50.32 LAYER met3  ;
    ANTENNAPARTIALCUTAREA 0.04 LAYER via3  ;
    ANTENNADIFFAREA 0.4455 LAYER met4  ;
    ANTENNAPARTIALMETALAREA 36.1134 LAYER met4  ;
    ANTENNAPARTIALMETALSIDEAREA 194.016 LAYER met4  ;
    PORT
      LAYER met3 ;
        RECT 0.000000 2029.380000 0.800000 2029.680000 ;
    END
  END io_out[29]
  PIN io_out[28]
    DIRECTION OUTPUT ;
    USE SIGNAL ;
    ANTENNADIFFAREA 0.4455 LAYER met3  ;
    ANTENNAPARTIALMETALAREA 0.3804 LAYER met3  ;
    ANTENNAPARTIALMETALSIDEAREA 2.024 LAYER met3  ;
    PORT
      LAYER met3 ;
        RECT 0.000000 2291.070000 0.800000 2291.370000 ;
    END
  END io_out[28]
  PIN io_out[27]
    DIRECTION OUTPUT ;
    USE SIGNAL ;
    ANTENNAPARTIALMETALAREA 38.4634 LAYER met3  ;
    ANTENNAPARTIALMETALSIDEAREA 205.6 LAYER met3  ;
    ANTENNAPARTIALCUTAREA 0.04 LAYER via3  ;
    ANTENNADIFFAREA 0.4455 LAYER met4  ;
    ANTENNAPARTIALMETALAREA 12.6828 LAYER met4  ;
    ANTENNAPARTIALMETALSIDEAREA 68.112 LAYER met4  ;
    PORT
      LAYER met3 ;
        RECT 0.000000 2552.760000 0.800000 2553.060000 ;
    END
  END io_out[27]
  PIN io_out[26]
    DIRECTION OUTPUT ;
    USE SIGNAL ;
    ANTENNAPARTIALMETALAREA 74.4334 LAYER met3  ;
    ANTENNAPARTIALMETALSIDEAREA 397.44 LAYER met3  ;
    ANTENNAPARTIALCUTAREA 0.04 LAYER via3  ;
    ANTENNADIFFAREA 0.336 LAYER met4  ;
    ANTENNAPARTIALMETALAREA 48.2622 LAYER met4  ;
    ANTENNAPARTIALMETALSIDEAREA 259.28 LAYER met4  ;
    PORT
      LAYER met3 ;
        RECT 0.000000 2814.450000 0.800000 2814.750000 ;
    END
  END io_out[26]
  PIN io_out[25]
    DIRECTION OUTPUT ;
    USE SIGNAL ;
    ANTENNADIFFAREA 0.336 LAYER met3  ;
    ANTENNAPARTIALMETALAREA 38.0352 LAYER met3  ;
    ANTENNAPARTIALMETALSIDEAREA 203.32 LAYER met3  ;
    PORT
      LAYER met3 ;
        RECT 0.000000 3076.750000 0.800000 3077.050000 ;
    END
  END io_out[25]
  PIN io_out[24]
    DIRECTION OUTPUT ;
    USE SIGNAL ;
    ANTENNADIFFAREA 0.4455 LAYER met3  ;
    ANTENNAPARTIALMETALAREA 40.5312 LAYER met3  ;
    ANTENNAPARTIALMETALSIDEAREA 216.632 LAYER met3  ;
    PORT
      LAYER met3 ;
        RECT 0.000000 3338.440000 0.800000 3338.740000 ;
    END
  END io_out[24]
  PIN io_out[23]
    DIRECTION OUTPUT ;
    USE SIGNAL ;
    ANTENNAPARTIALMETALAREA 27.9776 LAYER met2  ;
    ANTENNAPARTIALMETALSIDEAREA 139.727 LAYER met2  ;
    ANTENNAPARTIALCUTAREA 0.04 LAYER via2  ;
    ANTENNAPARTIALMETALAREA 0.4 LAYER met3  ;
    ANTENNAPARTIALMETALSIDEAREA 2.6 LAYER met3  ;
    ANTENNAPARTIALCUTAREA 0.04 LAYER via3  ;
    ANTENNADIFFAREA 0.4455 LAYER met4  ;
    ANTENNAPARTIALMETALAREA 110.572 LAYER met4  ;
    ANTENNAPARTIALMETALSIDEAREA 590.656 LAYER met4  ;
    PORT
      LAYER met2 ;
        RECT 81.580000 3469.555000 81.720000 3470.040000 ;
    END
  END io_out[23]
  PIN io_out[22]
    DIRECTION OUTPUT ;
    USE SIGNAL ;
    ANTENNADIFFAREA 0.336 LAYER met2  ;
    ANTENNAPARTIALMETALAREA 6.0617 LAYER met2  ;
    ANTENNAPARTIALMETALSIDEAREA 30.0825 LAYER met2  ;
    PORT
      LAYER met2 ;
        RECT 408.640000 3469.555000 408.780000 3470.040000 ;
    END
  END io_out[22]
  PIN io_out[21]
    DIRECTION OUTPUT ;
    USE SIGNAL ;
    ANTENNADIFFAREA 0.336 LAYER met2  ;
    ANTENNAPARTIALMETALAREA 0.9209 LAYER met2  ;
    ANTENNAPARTIALMETALSIDEAREA 4.3785 LAYER met2  ;
    PORT
      LAYER met2 ;
        RECT 735.240000 3469.555000 735.380000 3470.040000 ;
    END
  END io_out[21]
  PIN io_out[20]
    DIRECTION OUTPUT ;
    USE SIGNAL ;
    ANTENNADIFFAREA 0.3406 LAYER met2  ;
    ANTENNAPARTIALMETALAREA 4.4909 LAYER met2  ;
    ANTENNAPARTIALMETALSIDEAREA 22.2285 LAYER met2  ;
    PORT
      LAYER met2 ;
        RECT 1061.840000 3469.555000 1061.980000 3470.040000 ;
    END
  END io_out[20]
  PIN io_out[19]
    DIRECTION OUTPUT ;
    USE SIGNAL ;
    ANTENNADIFFAREA 0.336 LAYER met2  ;
    ANTENNAPARTIALMETALAREA 4.3483 LAYER met2  ;
    ANTENNAPARTIALMETALSIDEAREA 21.6335 LAYER met2  ;
    PORT
      LAYER met2 ;
        RECT 1388.900000 3469.555000 1389.040000 3470.040000 ;
    END
  END io_out[19]
  PIN io_out[18]
    DIRECTION OUTPUT ;
    USE SIGNAL ;
    ANTENNADIFFAREA 0.336 LAYER met2  ;
    ANTENNAPARTIALMETALAREA 4.4771 LAYER met2  ;
    ANTENNAPARTIALMETALSIDEAREA 22.2775 LAYER met2  ;
    PORT
      LAYER met2 ;
        RECT 1715.500000 3469.555000 1715.640000 3470.040000 ;
    END
  END io_out[18]
  PIN io_out[17]
    DIRECTION OUTPUT ;
    USE SIGNAL ;
    ANTENNADIFFAREA 0.336 LAYER met2  ;
    ANTENNAPARTIALMETALAREA 4.4911 LAYER met2  ;
    ANTENNAPARTIALMETALSIDEAREA 22.3475 LAYER met2  ;
    PORT
      LAYER met2 ;
        RECT 2042.100000 3469.555000 2042.240000 3470.040000 ;
    END
  END io_out[17]
  PIN io_out[16]
    DIRECTION OUTPUT ;
    USE SIGNAL ;
    ANTENNADIFFAREA 0.336 LAYER met2  ;
    ANTENNAPARTIALMETALAREA 4.8579 LAYER met2  ;
    ANTENNAPARTIALMETALSIDEAREA 24.1815 LAYER met2  ;
    PORT
      LAYER met2 ;
        RECT 2369.160000 3469.555000 2369.300000 3470.040000 ;
    END
  END io_out[16]
  PIN io_out[15]
    DIRECTION OUTPUT ;
    USE SIGNAL ;
    ANTENNADIFFAREA 0.336 LAYER met2  ;
    ANTENNAPARTIALMETALAREA 4.3483 LAYER met2  ;
    ANTENNAPARTIALMETALSIDEAREA 21.6335 LAYER met2  ;
    PORT
      LAYER met2 ;
        RECT 2695.760000 3469.555000 2695.900000 3470.040000 ;
    END
  END io_out[15]
  PIN io_out[14]
    DIRECTION OUTPUT ;
    USE SIGNAL ;
    ANTENNADIFFAREA 0.336 LAYER met3  ;
    ANTENNAPARTIALMETALAREA 0.1644 LAYER met3  ;
    ANTENNAPARTIALMETALSIDEAREA 0.872 LAYER met3  ;
    PORT
      LAYER met3 ;
        RECT 2859.020000 3403.100000 2859.820000 3403.400000 ;
    END
  END io_out[14]
  PIN io_out[13]
    DIRECTION OUTPUT ;
    USE SIGNAL ;
    ANTENNADIFFAREA 0.336 LAYER met3  ;
    ANTENNAPARTIALMETALAREA 0.1644 LAYER met3  ;
    ANTENNAPARTIALMETALSIDEAREA 0.872 LAYER met3  ;
    PORT
      LAYER met3 ;
        RECT 2859.020000 3136.530000 2859.820000 3136.830000 ;
    END
  END io_out[13]
  PIN io_out[12]
    DIRECTION OUTPUT ;
    USE SIGNAL ;
    ANTENNADIFFAREA 0.336 LAYER met3  ;
    ANTENNAPARTIALMETALAREA 0.1644 LAYER met3  ;
    ANTENNAPARTIALMETALSIDEAREA 0.872 LAYER met3  ;
    PORT
      LAYER met3 ;
        RECT 2859.020000 2869.350000 2859.820000 2869.650000 ;
    END
  END io_out[12]
  PIN io_out[11]
    DIRECTION OUTPUT ;
    USE SIGNAL ;
    ANTENNADIFFAREA 0.336 LAYER met3  ;
    ANTENNAPARTIALMETALAREA 0.1644 LAYER met3  ;
    ANTENNAPARTIALMETALSIDEAREA 0.872 LAYER met3  ;
    PORT
      LAYER met3 ;
        RECT 2859.020000 2602.780000 2859.820000 2603.080000 ;
    END
  END io_out[11]
  PIN io_out[10]
    DIRECTION OUTPUT ;
    USE SIGNAL ;
    ANTENNADIFFAREA 0.336 LAYER met3  ;
    ANTENNAPARTIALMETALAREA 0.1644 LAYER met3  ;
    ANTENNAPARTIALMETALSIDEAREA 0.872 LAYER met3  ;
    PORT
      LAYER met3 ;
        RECT 2859.020000 2335.600000 2859.820000 2335.900000 ;
    END
  END io_out[10]
  PIN io_out[9]
    DIRECTION OUTPUT ;
    USE SIGNAL ;
    ANTENNADIFFAREA 0.336 LAYER met3  ;
    ANTENNAPARTIALMETALAREA 0.1644 LAYER met3  ;
    ANTENNAPARTIALMETALSIDEAREA 0.872 LAYER met3  ;
    PORT
      LAYER met3 ;
        RECT 2859.020000 2069.030000 2859.820000 2069.330000 ;
    END
  END io_out[9]
  PIN io_out[8]
    DIRECTION OUTPUT ;
    USE SIGNAL ;
    ANTENNADIFFAREA 0.336 LAYER met3  ;
    ANTENNAPARTIALMETALAREA 0.1644 LAYER met3  ;
    ANTENNAPARTIALMETALSIDEAREA 0.872 LAYER met3  ;
    PORT
      LAYER met3 ;
        RECT 2859.020000 1801.850000 2859.820000 1802.150000 ;
    END
  END io_out[8]
  PIN io_out[7]
    DIRECTION OUTPUT ;
    USE SIGNAL ;
    ANTENNADIFFAREA 0.336 LAYER met3  ;
    ANTENNAPARTIALMETALAREA 0.1644 LAYER met3  ;
    ANTENNAPARTIALMETALSIDEAREA 0.872 LAYER met3  ;
    PORT
      LAYER met3 ;
        RECT 2859.020000 1535.280000 2859.820000 1535.580000 ;
    END
  END io_out[7]
  PIN io_out[6]
    DIRECTION OUTPUT ;
    USE SIGNAL ;
    ANTENNADIFFAREA 0.336 LAYER met3  ;
    ANTENNAPARTIALMETALAREA 0.3024 LAYER met3  ;
    ANTENNAPARTIALMETALSIDEAREA 1.608 LAYER met3  ;
    PORT
      LAYER met3 ;
        RECT 2859.020000 1268.100000 2859.820000 1268.400000 ;
    END
  END io_out[6]
  PIN io_out[5]
    DIRECTION OUTPUT ;
    USE SIGNAL ;
    ANTENNADIFFAREA 0.336 LAYER met3  ;
    ANTENNAPARTIALMETALAREA 6.5124 LAYER met3  ;
    ANTENNAPARTIALMETALSIDEAREA 34.728 LAYER met3  ;
    PORT
      LAYER met3 ;
        RECT 2859.020000 1068.020000 2859.820000 1068.320000 ;
    END
  END io_out[5]
  PIN io_out[4]
    DIRECTION OUTPUT ;
    USE SIGNAL ;
    ANTENNADIFFAREA 0.336 LAYER met3  ;
    ANTENNAPARTIALMETALAREA 0.1644 LAYER met3  ;
    ANTENNAPARTIALMETALSIDEAREA 0.872 LAYER met3  ;
    PORT
      LAYER met3 ;
        RECT 2859.020000 867.940000 2859.820000 868.240000 ;
    END
  END io_out[4]
  PIN io_out[3]
    DIRECTION OUTPUT ;
    USE SIGNAL ;
    ANTENNADIFFAREA 0.336 LAYER met3  ;
    ANTENNAPARTIALMETALAREA 0.1644 LAYER met3  ;
    ANTENNAPARTIALMETALSIDEAREA 0.872 LAYER met3  ;
    PORT
      LAYER met3 ;
        RECT 2859.020000 667.860000 2859.820000 668.160000 ;
    END
  END io_out[3]
  PIN io_out[2]
    DIRECTION OUTPUT ;
    USE SIGNAL ;
    ANTENNADIFFAREA 0.336 LAYER met3  ;
    ANTENNAPARTIALMETALAREA 4.5804 LAYER met3  ;
    ANTENNAPARTIALMETALSIDEAREA 24.424 LAYER met3  ;
    PORT
      LAYER met3 ;
        RECT 2859.020000 467.780000 2859.820000 468.080000 ;
    END
  END io_out[2]
  PIN io_out[1]
    DIRECTION OUTPUT ;
    USE SIGNAL ;
    ANTENNADIFFAREA 0.336 LAYER met3  ;
    ANTENNAPARTIALMETALAREA 0.1644 LAYER met3  ;
    ANTENNAPARTIALMETALSIDEAREA 0.872 LAYER met3  ;
    PORT
      LAYER met3 ;
        RECT 2859.020000 267.700000 2859.820000 268.000000 ;
    END
  END io_out[1]
  PIN io_out[0]
    DIRECTION OUTPUT ;
    USE SIGNAL ;
    ANTENNADIFFAREA 0.336 LAYER met3  ;
    ANTENNAPARTIALMETALAREA 0.1644 LAYER met3  ;
    ANTENNAPARTIALMETALSIDEAREA 0.872 LAYER met3  ;
    PORT
      LAYER met3 ;
        RECT 2859.020000 67.620000 2859.820000 67.920000 ;
    END
  END io_out[0]
  PIN io_oeb[37]
    DIRECTION OUTPUT ;
    USE SIGNAL ;
    ANTENNADIFFAREA 0.336 LAYER met3  ;
    ANTENNAPARTIALMETALAREA 11.0664 LAYER met3  ;
    ANTENNAPARTIALMETALSIDEAREA 59.016 LAYER met3  ;
    PORT
      LAYER met3 ;
        RECT 0.000000 0.520000 0.800000 0.820000 ;
    END
  END io_oeb[37]
  PIN io_oeb[36]
    DIRECTION OUTPUT ;
    USE SIGNAL ;
    ANTENNADIFFAREA 0.336 LAYER met3  ;
    ANTENNAPARTIALMETALAREA 8.8584 LAYER met3  ;
    ANTENNAPARTIALMETALSIDEAREA 47.24 LAYER met3  ;
    PORT
      LAYER met3 ;
        RECT 0.000000 196.330000 0.800000 196.630000 ;
    END
  END io_oeb[36]
  PIN io_oeb[35]
    DIRECTION OUTPUT ;
    USE SIGNAL ;
    ANTENNADIFFAREA 0.336 LAYER met3  ;
    ANTENNAPARTIALMETALAREA 0.3024 LAYER met3  ;
    ANTENNAPARTIALMETALSIDEAREA 1.608 LAYER met3  ;
    PORT
      LAYER met3 ;
        RECT 0.000000 392.750000 0.800000 393.050000 ;
    END
  END io_oeb[35]
  PIN io_oeb[34]
    DIRECTION OUTPUT ;
    USE SIGNAL ;
    ANTENNADIFFAREA 0.336 LAYER met3  ;
    ANTENNAPARTIALMETALAREA 9.0864 LAYER met3  ;
    ANTENNAPARTIALMETALSIDEAREA 48.456 LAYER met3  ;
    PORT
      LAYER met3 ;
        RECT 0.000000 655.050000 0.800000 655.350000 ;
    END
  END io_oeb[34]
  PIN io_oeb[33]
    DIRECTION OUTPUT ;
    USE SIGNAL ;
    ANTENNADIFFAREA 0.336 LAYER met3  ;
    ANTENNAPARTIALMETALAREA 0.1644 LAYER met3  ;
    ANTENNAPARTIALMETALSIDEAREA 0.872 LAYER met3  ;
    PORT
      LAYER met3 ;
        RECT 0.000000 916.740000 0.800000 917.040000 ;
    END
  END io_oeb[33]
  PIN io_oeb[32]
    DIRECTION OUTPUT ;
    USE SIGNAL ;
    ANTENNADIFFAREA 0.336 LAYER met3  ;
    ANTENNAPARTIALMETALAREA 4.0284 LAYER met3  ;
    ANTENNAPARTIALMETALSIDEAREA 21.48 LAYER met3  ;
    PORT
      LAYER met3 ;
        RECT 0.000000 1178.430000 0.800000 1178.730000 ;
    END
  END io_oeb[32]
  PIN io_oeb[31]
    DIRECTION OUTPUT ;
    USE SIGNAL ;
    ANTENNADIFFAREA 0.336 LAYER met3  ;
    ANTENNAPARTIALMETALAREA 4.3044 LAYER met3  ;
    ANTENNAPARTIALMETALSIDEAREA 22.952 LAYER met3  ;
    PORT
      LAYER met3 ;
        RECT 0.000000 1440.120000 0.800000 1440.420000 ;
    END
  END io_oeb[31]
  PIN io_oeb[30]
    DIRECTION OUTPUT ;
    USE SIGNAL ;
    ANTENNADIFFAREA 0.336 LAYER met3  ;
    ANTENNAPARTIALMETALAREA 6.2364 LAYER met3  ;
    ANTENNAPARTIALMETALSIDEAREA 33.256 LAYER met3  ;
    PORT
      LAYER met3 ;
        RECT 0.000000 1701.810000 0.800000 1702.110000 ;
    END
  END io_oeb[30]
  PIN io_oeb[29]
    DIRECTION OUTPUT ;
    USE SIGNAL ;
    ANTENNADIFFAREA 0.336 LAYER met3  ;
    ANTENNAPARTIALMETALAREA 8.7204 LAYER met3  ;
    ANTENNAPARTIALMETALSIDEAREA 46.504 LAYER met3  ;
    PORT
      LAYER met3 ;
        RECT 0.000000 1964.110000 0.800000 1964.410000 ;
    END
  END io_oeb[29]
  PIN io_oeb[28]
    DIRECTION OUTPUT ;
    USE SIGNAL ;
    ANTENNADIFFAREA 0.336 LAYER met3  ;
    ANTENNAPARTIALMETALAREA 8.7204 LAYER met3  ;
    ANTENNAPARTIALMETALSIDEAREA 46.504 LAYER met3  ;
    PORT
      LAYER met3 ;
        RECT 0.000000 2225.800000 0.800000 2226.100000 ;
    END
  END io_oeb[28]
  PIN io_oeb[27]
    DIRECTION OUTPUT ;
    USE SIGNAL ;
    ANTENNADIFFAREA 0.336 LAYER met3  ;
    ANTENNAPARTIALMETALAREA 0.5784 LAYER met3  ;
    ANTENNAPARTIALMETALSIDEAREA 3.08 LAYER met3  ;
    PORT
      LAYER met3 ;
        RECT 0.000000 2487.490000 0.800000 2487.790000 ;
    END
  END io_oeb[27]
  PIN io_oeb[26]
    DIRECTION OUTPUT ;
    USE SIGNAL ;
    ANTENNADIFFAREA 0.336 LAYER met3  ;
    ANTENNAPARTIALMETALAREA 0.1644 LAYER met3  ;
    ANTENNAPARTIALMETALSIDEAREA 0.872 LAYER met3  ;
    PORT
      LAYER met3 ;
        RECT 0.000000 2749.180000 0.800000 2749.480000 ;
    END
  END io_oeb[26]
  PIN io_oeb[25]
    DIRECTION OUTPUT ;
    USE SIGNAL ;
    ANTENNADIFFAREA 0.336 LAYER met3  ;
    ANTENNAPARTIALMETALAREA 8.4444 LAYER met3  ;
    ANTENNAPARTIALMETALSIDEAREA 45.032 LAYER met3  ;
    PORT
      LAYER met3 ;
        RECT 0.000000 3010.870000 0.800000 3011.170000 ;
    END
  END io_oeb[25]
  PIN io_oeb[24]
    DIRECTION OUTPUT ;
    USE SIGNAL ;
    ANTENNADIFFAREA 0.336 LAYER met3  ;
    ANTENNAPARTIALMETALAREA 8.5824 LAYER met3  ;
    ANTENNAPARTIALMETALSIDEAREA 45.768 LAYER met3  ;
    PORT
      LAYER met3 ;
        RECT 0.000000 3273.170000 0.800000 3273.470000 ;
    END
  END io_oeb[24]
  PIN io_oeb[23]
    DIRECTION OUTPUT ;
    USE SIGNAL ;
    ANTENNADIFFAREA 0.336 LAYER met2  ;
    ANTENNAPARTIALMETALAREA 4.3483 LAYER met2  ;
    ANTENNAPARTIALMETALSIDEAREA 21.6335 LAYER met2  ;
    PORT
      LAYER met2 ;
        RECT 0.160000 3469.555000 0.300000 3470.040000 ;
    END
  END io_oeb[23]
  PIN io_oeb[22]
    DIRECTION OUTPUT ;
    USE SIGNAL ;
    ANTENNADIFFAREA 0.336 LAYER met2  ;
    ANTENNAPARTIALMETALAREA 4.7291 LAYER met2  ;
    ANTENNAPARTIALMETALSIDEAREA 23.5375 LAYER met2  ;
    PORT
      LAYER met2 ;
        RECT 326.760000 3469.555000 326.900000 3470.040000 ;
    END
  END io_oeb[22]
  PIN io_oeb[21]
    DIRECTION OUTPUT ;
    USE SIGNAL ;
    ANTENNADIFFAREA 0.336 LAYER met2  ;
    ANTENNAPARTIALMETALAREA 4.7291 LAYER met2  ;
    ANTENNAPARTIALMETALSIDEAREA 23.5375 LAYER met2  ;
    PORT
      LAYER met2 ;
        RECT 653.360000 3469.555000 653.500000 3470.040000 ;
    END
  END io_oeb[21]
  PIN io_oeb[20]
    DIRECTION OUTPUT ;
    USE SIGNAL ;
    ANTENNADIFFAREA 0.336 LAYER met2  ;
    ANTENNAPARTIALMETALAREA 4.4771 LAYER met2  ;
    ANTENNAPARTIALMETALSIDEAREA 22.2775 LAYER met2  ;
    PORT
      LAYER met2 ;
        RECT 980.420000 3469.555000 980.560000 3470.040000 ;
    END
  END io_oeb[20]
  PIN io_oeb[19]
    DIRECTION OUTPUT ;
    USE SIGNAL ;
    ANTENNADIFFAREA 0.336 LAYER met2  ;
    ANTENNAPARTIALMETALAREA 4.3483 LAYER met2  ;
    ANTENNAPARTIALMETALSIDEAREA 21.6335 LAYER met2  ;
    PORT
      LAYER met2 ;
        RECT 1307.020000 3469.555000 1307.160000 3470.040000 ;
    END
  END io_oeb[19]
  PIN io_oeb[18]
    DIRECTION OUTPUT ;
    USE SIGNAL ;
    ANTENNADIFFAREA 0.336 LAYER met2  ;
    ANTENNAPARTIALMETALAREA 4.3483 LAYER met2  ;
    ANTENNAPARTIALMETALSIDEAREA 21.6335 LAYER met2  ;
    PORT
      LAYER met2 ;
        RECT 1633.620000 3469.555000 1633.760000 3470.040000 ;
    END
  END io_oeb[18]
  PIN io_oeb[17]
    DIRECTION OUTPUT ;
    USE SIGNAL ;
    ANTENNADIFFAREA 0.336 LAYER met2  ;
    ANTENNAPARTIALMETALAREA 4.3483 LAYER met2  ;
    ANTENNAPARTIALMETALSIDEAREA 21.6335 LAYER met2  ;
    PORT
      LAYER met2 ;
        RECT 1960.680000 3469.555000 1960.820000 3470.040000 ;
    END
  END io_oeb[17]
  PIN io_oeb[16]
    DIRECTION OUTPUT ;
    USE SIGNAL ;
    ANTENNADIFFAREA 0.336 LAYER met2  ;
    ANTENNAPARTIALMETALAREA 4.4127 LAYER met2  ;
    ANTENNAPARTIALMETALSIDEAREA 21.9555 LAYER met2  ;
    PORT
      LAYER met2 ;
        RECT 2287.280000 3469.555000 2287.420000 3470.040000 ;
    END
  END io_oeb[16]
  PIN io_oeb[15]
    DIRECTION OUTPUT ;
    USE SIGNAL ;
    ANTENNADIFFAREA 0.336 LAYER met2  ;
    ANTENNAPARTIALMETALAREA 4.3483 LAYER met2  ;
    ANTENNAPARTIALMETALSIDEAREA 21.6335 LAYER met2  ;
    PORT
      LAYER met2 ;
        RECT 2614.340000 3469.555000 2614.480000 3470.040000 ;
    END
  END io_oeb[15]
  PIN io_oeb[14]
    DIRECTION OUTPUT ;
    USE SIGNAL ;
    ANTENNADIFFAREA 0.336 LAYER met3  ;
    ANTENNAPARTIALMETALAREA 8.8584 LAYER met3  ;
    ANTENNAPARTIALMETALSIDEAREA 47.24 LAYER met3  ;
    PORT
      LAYER met3 ;
        RECT 2859.020000 3469.590000 2859.820000 3469.890000 ;
    END
  END io_oeb[14]
  PIN io_oeb[13]
    DIRECTION OUTPUT ;
    USE SIGNAL ;
    ANTENNADIFFAREA 0.336 LAYER met3  ;
    ANTENNAPARTIALMETALAREA 3.0624 LAYER met3  ;
    ANTENNAPARTIALMETALSIDEAREA 16.328 LAYER met3  ;
    PORT
      LAYER met3 ;
        RECT 2859.020000 3203.020000 2859.820000 3203.320000 ;
    END
  END io_oeb[13]
  PIN io_oeb[12]
    DIRECTION OUTPUT ;
    USE SIGNAL ;
    ANTENNADIFFAREA 0.336 LAYER met3  ;
    ANTENNAPARTIALMETALAREA 8.8584 LAYER met3  ;
    ANTENNAPARTIALMETALSIDEAREA 47.24 LAYER met3  ;
    PORT
      LAYER met3 ;
        RECT 2859.020000 2936.450000 2859.820000 2936.750000 ;
    END
  END io_oeb[12]
  PIN io_oeb[11]
    DIRECTION OUTPUT ;
    USE SIGNAL ;
    ANTENNADIFFAREA 0.336 LAYER met3  ;
    ANTENNAPARTIALMETALAREA 0.1644 LAYER met3  ;
    ANTENNAPARTIALMETALSIDEAREA 0.872 LAYER met3  ;
    PORT
      LAYER met3 ;
        RECT 2859.020000 2669.270000 2859.820000 2669.570000 ;
    END
  END io_oeb[11]
  PIN io_oeb[10]
    DIRECTION OUTPUT ;
    USE SIGNAL ;
    ANTENNADIFFAREA 0.336 LAYER met3  ;
    ANTENNAPARTIALMETALAREA 0.1644 LAYER met3  ;
    ANTENNAPARTIALMETALSIDEAREA 0.872 LAYER met3  ;
    PORT
      LAYER met3 ;
        RECT 2859.020000 2402.700000 2859.820000 2403.000000 ;
    END
  END io_oeb[10]
  PIN io_oeb[9]
    DIRECTION OUTPUT ;
    USE SIGNAL ;
    ANTENNADIFFAREA 0.336 LAYER met3  ;
    ANTENNAPARTIALMETALAREA 0.1644 LAYER met3  ;
    ANTENNAPARTIALMETALSIDEAREA 0.872 LAYER met3  ;
    PORT
      LAYER met3 ;
        RECT 2859.020000 2135.520000 2859.820000 2135.820000 ;
    END
  END io_oeb[9]
  PIN io_oeb[8]
    DIRECTION OUTPUT ;
    USE SIGNAL ;
    ANTENNADIFFAREA 0.336 LAYER met3  ;
    ANTENNAPARTIALMETALAREA 8.9964 LAYER met3  ;
    ANTENNAPARTIALMETALSIDEAREA 47.976 LAYER met3  ;
    PORT
      LAYER met3 ;
        RECT 2859.020000 1868.950000 2859.820000 1869.250000 ;
    END
  END io_oeb[8]
  PIN io_oeb[7]
    DIRECTION OUTPUT ;
    USE SIGNAL ;
    ANTENNADIFFAREA 0.336 LAYER met3  ;
    ANTENNAPARTIALMETALAREA 9.1344 LAYER met3  ;
    ANTENNAPARTIALMETALSIDEAREA 48.712 LAYER met3  ;
    PORT
      LAYER met3 ;
        RECT 2859.020000 1601.770000 2859.820000 1602.070000 ;
    END
  END io_oeb[7]
  PIN io_oeb[6]
    DIRECTION OUTPUT ;
    USE SIGNAL ;
    ANTENNADIFFAREA 0.336 LAYER met3  ;
    ANTENNAPARTIALMETALAREA 4.0284 LAYER met3  ;
    ANTENNAPARTIALMETALSIDEAREA 21.48 LAYER met3  ;
    PORT
      LAYER met3 ;
        RECT 2859.020000 1335.200000 2859.820000 1335.500000 ;
    END
  END io_oeb[6]
  PIN io_oeb[5]
    DIRECTION OUTPUT ;
    USE SIGNAL ;
    ANTENNADIFFAREA 0.336 LAYER met3  ;
    ANTENNAPARTIALMETALAREA 2.7864 LAYER met3  ;
    ANTENNAPARTIALMETALSIDEAREA 14.856 LAYER met3  ;
    PORT
      LAYER met3 ;
        RECT 2859.020000 1135.120000 2859.820000 1135.420000 ;
    END
  END io_oeb[5]
  PIN io_oeb[4]
    DIRECTION OUTPUT ;
    USE SIGNAL ;
    ANTENNADIFFAREA 0.336 LAYER met3  ;
    ANTENNAPARTIALMETALAREA 8.8584 LAYER met3  ;
    ANTENNAPARTIALMETALSIDEAREA 47.24 LAYER met3  ;
    PORT
      LAYER met3 ;
        RECT 2859.020000 935.040000 2859.820000 935.340000 ;
    END
  END io_oeb[4]
  PIN io_oeb[3]
    DIRECTION OUTPUT ;
    USE SIGNAL ;
    ANTENNADIFFAREA 0.336 LAYER met3  ;
    ANTENNAPARTIALMETALAREA 0.1644 LAYER met3  ;
    ANTENNAPARTIALMETALSIDEAREA 0.872 LAYER met3  ;
    PORT
      LAYER met3 ;
        RECT 2859.020000 734.960000 2859.820000 735.260000 ;
    END
  END io_oeb[3]
  PIN io_oeb[2]
    DIRECTION OUTPUT ;
    USE SIGNAL ;
    ANTENNADIFFAREA 0.336 LAYER met3  ;
    ANTENNAPARTIALMETALAREA 7.3404 LAYER met3  ;
    ANTENNAPARTIALMETALSIDEAREA 39.144 LAYER met3  ;
    PORT
      LAYER met3 ;
        RECT 2859.020000 534.270000 2859.820000 534.570000 ;
    END
  END io_oeb[2]
  PIN io_oeb[1]
    DIRECTION OUTPUT ;
    USE SIGNAL ;
    ANTENNADIFFAREA 0.336 LAYER met3  ;
    ANTENNAPARTIALMETALAREA 9.5004 LAYER met3  ;
    ANTENNAPARTIALMETALSIDEAREA 50.664 LAYER met3  ;
    PORT
      LAYER met3 ;
        RECT 2859.020000 334.190000 2859.820000 334.490000 ;
    END
  END io_oeb[1]
  PIN io_oeb[0]
    DIRECTION OUTPUT ;
    USE SIGNAL ;
    ANTENNADIFFAREA 0.336 LAYER met3  ;
    ANTENNAPARTIALMETALAREA 5.4084 LAYER met3  ;
    ANTENNAPARTIALMETALSIDEAREA 28.84 LAYER met3  ;
    PORT
      LAYER met3 ;
        RECT 2859.020000 134.110000 2859.820000 134.410000 ;
    END
  END io_oeb[0]
  PIN analog_io[28]
    DIRECTION INOUT ;
    USE SIGNAL ;
    PORT
      LAYER met3 ;
        RECT 0.000000 589.170000 0.800000 589.470000 ;
    END
  END analog_io[28]
  PIN analog_io[27]
    DIRECTION INOUT ;
    USE SIGNAL ;
    PORT
      LAYER met3 ;
        RECT 0.000000 850.860000 0.800000 851.160000 ;
    END
  END analog_io[27]
  PIN analog_io[26]
    DIRECTION INOUT ;
    USE SIGNAL ;
    PORT
      LAYER met3 ;
        RECT 0.000000 1113.160000 0.800000 1113.460000 ;
    END
  END analog_io[26]
  PIN analog_io[25]
    DIRECTION INOUT ;
    USE SIGNAL ;
    PORT
      LAYER met3 ;
        RECT 0.000000 1374.850000 0.800000 1375.150000 ;
    END
  END analog_io[25]
  PIN analog_io[24]
    DIRECTION INOUT ;
    USE SIGNAL ;
    PORT
      LAYER met3 ;
        RECT 0.000000 1636.540000 0.800000 1636.840000 ;
    END
  END analog_io[24]
  PIN analog_io[23]
    DIRECTION INOUT ;
    USE SIGNAL ;
    PORT
      LAYER met3 ;
        RECT 0.000000 1898.230000 0.800000 1898.530000 ;
    END
  END analog_io[23]
  PIN analog_io[22]
    DIRECTION INOUT ;
    USE SIGNAL ;
    PORT
      LAYER met3 ;
        RECT 0.000000 2159.920000 0.800000 2160.220000 ;
    END
  END analog_io[22]
  PIN analog_io[21]
    DIRECTION INOUT ;
    USE SIGNAL ;
    PORT
      LAYER met3 ;
        RECT 0.000000 2422.220000 0.800000 2422.520000 ;
    END
  END analog_io[21]
  PIN analog_io[20]
    DIRECTION INOUT ;
    USE SIGNAL ;
    PORT
      LAYER met3 ;
        RECT 0.000000 2683.910000 0.800000 2684.210000 ;
    END
  END analog_io[20]
  PIN analog_io[19]
    DIRECTION INOUT ;
    USE SIGNAL ;
    PORT
      LAYER met3 ;
        RECT 0.000000 2945.600000 0.800000 2945.900000 ;
    END
  END analog_io[19]
  PIN analog_io[18]
    DIRECTION INOUT ;
    USE SIGNAL ;
    PORT
      LAYER met3 ;
        RECT 0.000000 3207.290000 0.800000 3207.590000 ;
    END
  END analog_io[18]
  PIN analog_io[17]
    DIRECTION INOUT ;
    USE SIGNAL ;
    PORT
      LAYER met3 ;
        RECT 0.000000 3469.590000 0.800000 3469.890000 ;
    END
  END analog_io[17]
  PIN analog_io[16]
    DIRECTION INOUT ;
    USE SIGNAL ;
    PORT
      LAYER met2 ;
        RECT 244.880000 3469.555000 245.020000 3470.040000 ;
    END
  END analog_io[16]
  PIN analog_io[15]
    DIRECTION INOUT ;
    USE SIGNAL ;
    PORT
      LAYER met2 ;
        RECT 571.940000 3469.555000 572.080000 3470.040000 ;
    END
  END analog_io[15]
  PIN analog_io[14]
    DIRECTION INOUT ;
    USE SIGNAL ;
    PORT
      LAYER met2 ;
        RECT 898.540000 3469.555000 898.680000 3470.040000 ;
    END
  END analog_io[14]
  PIN analog_io[13]
    DIRECTION INOUT ;
    USE SIGNAL ;
    PORT
      LAYER met2 ;
        RECT 1225.140000 3469.555000 1225.280000 3470.040000 ;
    END
  END analog_io[13]
  PIN analog_io[12]
    DIRECTION INOUT ;
    USE SIGNAL ;
    PORT
      LAYER met2 ;
        RECT 1552.200000 3469.555000 1552.340000 3470.040000 ;
    END
  END analog_io[12]
  PIN analog_io[11]
    DIRECTION INOUT ;
    USE SIGNAL ;
    PORT
      LAYER met2 ;
        RECT 1878.800000 3469.555000 1878.940000 3470.040000 ;
    END
  END analog_io[11]
  PIN analog_io[10]
    DIRECTION INOUT ;
    USE SIGNAL ;
    PORT
      LAYER met2 ;
        RECT 2205.860000 3469.555000 2206.000000 3470.040000 ;
    END
  END analog_io[10]
  PIN analog_io[9]
    DIRECTION INOUT ;
    USE SIGNAL ;
    PORT
      LAYER met2 ;
        RECT 2532.460000 3469.555000 2532.600000 3470.040000 ;
    END
  END analog_io[9]
  PIN analog_io[8]
    DIRECTION INOUT ;
    USE SIGNAL ;
    PORT
      LAYER met2 ;
        RECT 2859.520000 3469.555000 2859.660000 3470.040000 ;
    END
  END analog_io[8]
  PIN analog_io[7]
    DIRECTION INOUT ;
    USE SIGNAL ;
    PORT
      LAYER met3 ;
        RECT 2859.020000 3269.510000 2859.820000 3269.810000 ;
    END
  END analog_io[7]
  PIN analog_io[6]
    DIRECTION INOUT ;
    USE SIGNAL ;
    PORT
      LAYER met3 ;
        RECT 2859.020000 3002.940000 2859.820000 3003.240000 ;
    END
  END analog_io[6]
  PIN analog_io[5]
    DIRECTION INOUT ;
    USE SIGNAL ;
    PORT
      LAYER met3 ;
        RECT 2859.020000 2735.760000 2859.820000 2736.060000 ;
    END
  END analog_io[5]
  PIN analog_io[4]
    DIRECTION INOUT ;
    USE SIGNAL ;
    PORT
      LAYER met3 ;
        RECT 2859.020000 2469.190000 2859.820000 2469.490000 ;
    END
  END analog_io[4]
  PIN analog_io[3]
    DIRECTION INOUT ;
    USE SIGNAL ;
    PORT
      LAYER met3 ;
        RECT 2859.020000 2202.620000 2859.820000 2202.920000 ;
    END
  END analog_io[3]
  PIN analog_io[2]
    DIRECTION INOUT ;
    USE SIGNAL ;
    PORT
      LAYER met3 ;
        RECT 2859.020000 1935.440000 2859.820000 1935.740000 ;
    END
  END analog_io[2]
  PIN analog_io[1]
    DIRECTION INOUT ;
    USE SIGNAL ;
    PORT
      LAYER met3 ;
        RECT 2859.020000 1668.870000 2859.820000 1669.170000 ;
    END
  END analog_io[1]
  PIN analog_io[0]
    DIRECTION INOUT ;
    USE SIGNAL ;
    PORT
      LAYER met3 ;
        RECT 2859.020000 1401.690000 2859.820000 1401.990000 ;
    END
  END analog_io[0]
  PIN user_clock2
    DIRECTION INPUT ;
    USE SIGNAL ;
    PORT
      LAYER met2 ;
        RECT 2859.520000 0.000000 2859.660000 0.485000 ;
    END
  END user_clock2
  PIN irq[2]
    DIRECTION OUTPUT ;
    USE SIGNAL ;
  END irq[2]
  PIN irq[1]
    DIRECTION OUTPUT ;
    USE SIGNAL ;
  END irq[1]
  PIN irq[0]
    DIRECTION OUTPUT ;
    USE SIGNAL ;
  END irq[0]
  PIN vssd1
    DIRECTION INOUT ;
    USE GROUND ;
    PORT
      LAYER met5 ;
        RECT 2856.720000 3445.640000 2859.820000 3448.740000 ;
    END
    PORT
      LAYER met5 ;
        RECT 0.000000 3445.640000 3.100000 3448.740000 ;
    END
    PORT
      LAYER met5 ;
        RECT 2856.720000 19.260000 2859.820000 22.360000 ;
    END
    PORT
      LAYER met5 ;
        RECT 0.000000 19.260000 3.100000 22.360000 ;
    END
    PORT
      LAYER met4 ;
        RECT 2837.500000 3466.940000 2840.600000 3470.040000 ;
    END
    PORT
      LAYER met4 ;
        RECT 2837.500000 0.000000 2840.600000 3.100000 ;
    END
    PORT
      LAYER met4 ;
        RECT 19.220000 3466.940000 22.320000 3470.040000 ;
    END
    PORT
      LAYER met4 ;
        RECT 19.220000 0.000000 22.320000 3.100000 ;
    END

# P/G power stripe data as pin
    PORT
      LAYER met4 ;
        RECT 1428.000000 19.260000 1431.360000 2938.175000 ;
        RECT 19.220000 0.000000 22.320000 3470.040000 ;
        RECT 476.000000 19.260000 479.360000 2938.175000 ;
        RECT 612.000000 19.260000 615.360000 2938.175000 ;
        RECT 748.000000 19.260000 751.360000 2938.175000 ;
        RECT 1020.000000 19.260000 1023.360000 2938.175000 ;
        RECT 1156.000000 19.260000 1159.360000 2938.175000 ;
        RECT 1292.000000 19.260000 1295.360000 2938.175000 ;
        RECT 68.000000 19.260000 71.360000 3448.740000 ;
        RECT 204.000000 19.260000 207.360000 3448.740000 ;
        RECT 340.000000 19.260000 343.360000 3448.740000 ;
        RECT 884.000000 19.260000 887.360000 3448.740000 ;
        RECT 2837.500000 0.000000 2840.600000 3470.040000 ;
        RECT 1564.000000 19.260000 1567.360000 3448.740000 ;
        RECT 2108.000000 19.260000 2111.360000 3448.740000 ;
        RECT 2788.000000 19.260000 2791.360000 3448.740000 ;
        RECT 1591.465000 1443.875000 1593.265000 1855.775000 ;
        RECT 2083.845000 1443.875000 2085.645000 1855.775000 ;
        RECT 2201.245000 1443.875000 2203.045000 1855.775000 ;
        RECT 2693.625000 1443.875000 2695.425000 1855.775000 ;
        RECT 1700.000000 19.260000 1703.360000 1445.675000 ;
        RECT 1836.000000 19.260000 1839.360000 1445.675000 ;
        RECT 1972.000000 19.260000 1975.360000 1445.675000 ;
        RECT 2244.000000 19.260000 2247.360000 1445.675000 ;
        RECT 2380.000000 19.260000 2383.360000 1445.675000 ;
        RECT 2516.000000 19.260000 2519.360000 1445.675000 ;
        RECT 2652.000000 19.260000 2655.360000 1445.675000 ;
        RECT 1428.000000 3346.475000 1431.360000 3448.740000 ;
        RECT 361.905000 2936.375000 363.705000 3348.275000 ;
        RECT 476.000000 3346.475000 479.360000 3448.740000 ;
        RECT 981.685000 2936.375000 983.485000 3348.275000 ;
        RECT 854.285000 2936.375000 856.085000 3348.275000 ;
        RECT 748.000000 3346.475000 751.360000 3448.740000 ;
        RECT 612.000000 3346.475000 615.360000 3448.740000 ;
        RECT 1156.000000 3346.475000 1159.360000 3448.740000 ;
        RECT 1020.000000 3346.475000 1023.360000 3448.740000 ;
        RECT 1292.000000 3346.475000 1295.360000 3448.740000 ;
        RECT 2693.625000 2438.875000 2695.425000 2850.775000 ;
        RECT 2201.245000 2438.875000 2203.045000 2850.775000 ;
        RECT 2083.845000 2438.875000 2085.645000 2850.775000 ;
        RECT 1591.465000 2438.875000 1593.265000 2850.775000 ;
        RECT 2201.245000 1941.375000 2203.045000 2353.275000 ;
        RECT 2083.845000 1941.375000 2085.645000 2353.275000 ;
        RECT 1591.465000 1941.375000 1593.265000 2353.275000 ;
        RECT 1700.000000 1853.975000 1703.360000 1943.175000 ;
        RECT 1836.000000 1853.975000 1839.360000 1943.175000 ;
        RECT 1972.000000 1853.975000 1975.360000 1943.175000 ;
        RECT 2244.000000 1853.975000 2247.360000 1943.175000 ;
        RECT 1836.000000 2351.475000 1839.360000 2440.675000 ;
        RECT 1700.000000 2351.475000 1703.360000 2440.675000 ;
        RECT 2244.000000 2351.475000 2247.360000 2440.675000 ;
        RECT 1972.000000 2351.475000 1975.360000 2440.675000 ;
        RECT 2693.625000 1941.375000 2695.425000 2353.275000 ;
        RECT 2380.000000 1853.975000 2383.360000 1943.175000 ;
        RECT 2516.000000 1853.975000 2519.360000 1943.175000 ;
        RECT 2652.000000 1853.975000 2655.360000 1943.175000 ;
        RECT 2652.000000 2351.475000 2655.360000 2440.675000 ;
        RECT 2516.000000 2351.475000 2519.360000 2440.675000 ;
        RECT 2380.000000 2351.475000 2383.360000 2440.675000 ;
        RECT 2201.245000 2936.375000 2203.045000 3348.275000 ;
        RECT 2083.845000 2936.375000 2085.645000 3348.275000 ;
        RECT 1591.465000 2936.375000 1593.265000 3348.275000 ;
        RECT 1474.065000 2936.375000 1475.865000 3348.275000 ;
        RECT 1836.000000 2848.975000 1839.360000 2938.175000 ;
        RECT 1700.000000 2848.975000 1703.360000 2938.175000 ;
        RECT 1972.000000 2848.975000 1975.360000 2938.175000 ;
        RECT 2244.000000 2848.975000 2247.360000 2938.175000 ;
        RECT 1836.000000 3346.475000 1839.360000 3448.740000 ;
        RECT 1700.000000 3346.475000 1703.360000 3448.740000 ;
        RECT 1972.000000 3346.475000 1975.360000 3448.740000 ;
        RECT 2244.000000 3346.475000 2247.360000 3448.740000 ;
        RECT 2693.625000 2936.375000 2695.425000 3348.275000 ;
        RECT 2380.000000 2848.975000 2383.360000 2938.175000 ;
        RECT 2652.000000 2848.975000 2655.360000 2938.175000 ;
        RECT 2516.000000 2848.975000 2519.360000 2938.175000 ;
        RECT 2380.000000 3346.475000 2383.360000 3448.740000 ;
        RECT 2652.000000 3346.475000 2655.360000 3448.740000 ;
        RECT 2516.000000 3346.475000 2519.360000 3448.740000 ;
      LAYER met5 ;
        RECT 0.000000 19.260000 2859.820000 22.360000 ;
        RECT 0.000000 3445.640000 2859.820000 3448.740000 ;
    END
# end of P/G power stripe data as pin

  END vssd1
  PIN vccd1
    DIRECTION INOUT ;
    USE POWER ;
    PORT
      LAYER met5 ;
        RECT 2856.720000 3439.440000 2859.820000 3442.540000 ;
    END
    PORT
      LAYER met5 ;
        RECT 0.000000 3439.440000 3.100000 3442.540000 ;
    END
    PORT
      LAYER met5 ;
        RECT 2856.720000 25.460000 2859.820000 28.560000 ;
    END
    PORT
      LAYER met5 ;
        RECT 0.000000 25.460000 3.100000 28.560000 ;
    END
    PORT
      LAYER met4 ;
        RECT 2831.300000 3466.940000 2834.400000 3470.040000 ;
    END
    PORT
      LAYER met4 ;
        RECT 2831.300000 0.000000 2834.400000 3.100000 ;
    END
    PORT
      LAYER met4 ;
        RECT 25.420000 3466.940000 28.520000 3470.040000 ;
    END
    PORT
      LAYER met4 ;
        RECT 25.420000 0.000000 28.520000 3.100000 ;
    END

# P/G power stripe data as pin
    PORT
      LAYER met4 ;
        RECT 952.000000 25.460000 955.360000 3442.540000 ;
        RECT 272.000000 25.460000 275.360000 3442.540000 ;
        RECT 25.420000 0.000000 28.520000 3470.040000 ;
        RECT 408.000000 25.460000 411.360000 2941.775000 ;
        RECT 544.000000 25.460000 547.360000 2941.775000 ;
        RECT 680.000000 25.460000 683.360000 2941.775000 ;
        RECT 816.000000 25.460000 819.360000 2941.775000 ;
        RECT 1088.000000 25.460000 1091.360000 2941.775000 ;
        RECT 1224.000000 25.460000 1227.360000 2941.775000 ;
        RECT 1360.000000 25.460000 1363.360000 2941.775000 ;
        RECT 136.000000 25.460000 139.360000 3442.540000 ;
        RECT 2690.025000 1447.475000 2691.825000 1852.175000 ;
        RECT 2204.845000 1447.475000 2206.645000 1852.175000 ;
        RECT 2080.245000 1447.475000 2082.045000 1852.175000 ;
        RECT 1595.065000 1447.475000 1596.865000 1852.175000 ;
        RECT 2720.000000 25.460000 2723.360000 3442.540000 ;
        RECT 2176.000000 25.460000 2179.360000 3442.540000 ;
        RECT 1496.000000 25.460000 1499.360000 3442.540000 ;
        RECT 2831.300000 0.000000 2834.400000 3470.040000 ;
        RECT 2584.000000 25.460000 2587.360000 1449.275000 ;
        RECT 2448.000000 25.460000 2451.360000 1449.275000 ;
        RECT 2312.000000 25.460000 2315.360000 1449.275000 ;
        RECT 2040.000000 25.460000 2043.360000 1449.275000 ;
        RECT 1904.000000 25.460000 1907.360000 1449.275000 ;
        RECT 1768.000000 25.460000 1771.360000 1449.275000 ;
        RECT 1632.000000 25.460000 1635.360000 1449.275000 ;
        RECT 365.505000 2939.975000 367.305000 3344.675000 ;
        RECT 544.000000 3342.875000 547.360000 3442.540000 ;
        RECT 408.000000 3342.875000 411.360000 3442.540000 ;
        RECT 985.285000 2939.975000 987.085000 3344.675000 ;
        RECT 850.685000 2939.975000 852.485000 3344.675000 ;
        RECT 680.000000 3342.875000 683.360000 3442.540000 ;
        RECT 816.000000 3342.875000 819.360000 3442.540000 ;
        RECT 1088.000000 3342.875000 1091.360000 3442.540000 ;
        RECT 1360.000000 3342.875000 1363.360000 3442.540000 ;
        RECT 1224.000000 3342.875000 1227.360000 3442.540000 ;
        RECT 2690.025000 2442.475000 2691.825000 2847.175000 ;
        RECT 2204.845000 2442.475000 2206.645000 2847.175000 ;
        RECT 2080.245000 2442.475000 2082.045000 2847.175000 ;
        RECT 1595.065000 2442.475000 1596.865000 2847.175000 ;
        RECT 2204.845000 1944.975000 2206.645000 2349.675000 ;
        RECT 2080.245000 1944.975000 2082.045000 2349.675000 ;
        RECT 1595.065000 1944.975000 1596.865000 2349.675000 ;
        RECT 1632.000000 1850.375000 1635.360000 1946.775000 ;
        RECT 1768.000000 1850.375000 1771.360000 1946.775000 ;
        RECT 1904.000000 1850.375000 1907.360000 1946.775000 ;
        RECT 2040.000000 1850.375000 2043.360000 1946.775000 ;
        RECT 1768.000000 2347.875000 1771.360000 2444.275000 ;
        RECT 1632.000000 2347.875000 1635.360000 2444.275000 ;
        RECT 2040.000000 2347.875000 2043.360000 2444.275000 ;
        RECT 1904.000000 2347.875000 1907.360000 2444.275000 ;
        RECT 2690.025000 1944.975000 2691.825000 2349.675000 ;
        RECT 2312.000000 1850.375000 2315.360000 1946.775000 ;
        RECT 2448.000000 1850.375000 2451.360000 1946.775000 ;
        RECT 2584.000000 1850.375000 2587.360000 1946.775000 ;
        RECT 2584.000000 2347.875000 2587.360000 2444.275000 ;
        RECT 2448.000000 2347.875000 2451.360000 2444.275000 ;
        RECT 2312.000000 2347.875000 2315.360000 2444.275000 ;
        RECT 2204.845000 2939.975000 2206.645000 3344.675000 ;
        RECT 2080.245000 2939.975000 2082.045000 3344.675000 ;
        RECT 1595.065000 2939.975000 1596.865000 3344.675000 ;
        RECT 1470.465000 2939.975000 1472.265000 3344.675000 ;
        RECT 1632.000000 2845.375000 1635.360000 2941.775000 ;
        RECT 1768.000000 2845.375000 1771.360000 2941.775000 ;
        RECT 2040.000000 2845.375000 2043.360000 2941.775000 ;
        RECT 1904.000000 2845.375000 1907.360000 2941.775000 ;
        RECT 1632.000000 3342.875000 1635.360000 3442.540000 ;
        RECT 1768.000000 3342.875000 1771.360000 3442.540000 ;
        RECT 2040.000000 3342.875000 2043.360000 3442.540000 ;
        RECT 1904.000000 3342.875000 1907.360000 3442.540000 ;
        RECT 2690.025000 2939.975000 2691.825000 3344.675000 ;
        RECT 2448.000000 2845.375000 2451.360000 2941.775000 ;
        RECT 2312.000000 2845.375000 2315.360000 2941.775000 ;
        RECT 2584.000000 2845.375000 2587.360000 2941.775000 ;
        RECT 2448.000000 3342.875000 2451.360000 3442.540000 ;
        RECT 2312.000000 3342.875000 2315.360000 3442.540000 ;
        RECT 2584.000000 3342.875000 2587.360000 3442.540000 ;
      LAYER met5 ;
        RECT 0.000000 25.460000 2859.820000 28.560000 ;
        RECT 0.000000 3439.440000 2859.820000 3442.540000 ;
    END
# end of P/G power stripe data as pin

  END vccd1
  OBS
    LAYER li1 ;
      RECT 0.000000 0.000000 2859.820000 3470.040000 ;
    LAYER met1 ;
      RECT 0.000000 0.000000 2859.820000 3470.040000 ;
    LAYER met2 ;
      RECT 2778.060000 3469.275000 2859.240000 3470.040000 ;
      RECT 2696.180000 3469.275000 2777.360000 3470.040000 ;
      RECT 2614.760000 3469.275000 2695.480000 3470.040000 ;
      RECT 2532.880000 3469.275000 2614.060000 3470.040000 ;
      RECT 2451.460000 3469.275000 2532.180000 3470.040000 ;
      RECT 2369.580000 3469.275000 2450.760000 3470.040000 ;
      RECT 2287.700000 3469.275000 2368.880000 3470.040000 ;
      RECT 2206.280000 3469.275000 2287.000000 3470.040000 ;
      RECT 2124.400000 3469.275000 2205.580000 3470.040000 ;
      RECT 2042.520000 3469.275000 2123.700000 3470.040000 ;
      RECT 1961.100000 3469.275000 2041.820000 3470.040000 ;
      RECT 1879.220000 3469.275000 1960.400000 3470.040000 ;
      RECT 1797.800000 3469.275000 1878.520000 3470.040000 ;
      RECT 1715.920000 3469.275000 1797.100000 3470.040000 ;
      RECT 1634.040000 3469.275000 1715.220000 3470.040000 ;
      RECT 1552.620000 3469.275000 1633.340000 3470.040000 ;
      RECT 1470.740000 3469.275000 1551.920000 3470.040000 ;
      RECT 1389.320000 3469.275000 1470.040000 3470.040000 ;
      RECT 1307.440000 3469.275000 1388.620000 3470.040000 ;
      RECT 1225.560000 3469.275000 1306.740000 3470.040000 ;
      RECT 1144.140000 3469.275000 1224.860000 3470.040000 ;
      RECT 1062.260000 3469.275000 1143.440000 3470.040000 ;
      RECT 980.840000 3469.275000 1061.560000 3470.040000 ;
      RECT 898.960000 3469.275000 980.140000 3470.040000 ;
      RECT 817.080000 3469.275000 898.260000 3470.040000 ;
      RECT 735.660000 3469.275000 816.380000 3470.040000 ;
      RECT 653.780000 3469.275000 734.960000 3470.040000 ;
      RECT 572.360000 3469.275000 653.080000 3470.040000 ;
      RECT 490.480000 3469.275000 571.660000 3470.040000 ;
      RECT 409.060000 3469.275000 489.780000 3470.040000 ;
      RECT 327.180000 3469.275000 408.360000 3470.040000 ;
      RECT 245.300000 3469.275000 326.480000 3470.040000 ;
      RECT 163.880000 3469.275000 244.600000 3470.040000 ;
      RECT 82.000000 3469.275000 163.180000 3470.040000 ;
      RECT 0.580000 3469.275000 81.300000 3470.040000 ;
      RECT 0.000000 0.765000 2859.820000 3469.275000 ;
      RECT 2854.420000 0.000000 2859.240000 0.765000 ;
      RECT 2848.440000 0.000000 2853.720000 0.765000 ;
      RECT 2842.460000 0.000000 2847.740000 0.765000 ;
      RECT 2836.940000 0.000000 2841.760000 0.765000 ;
      RECT 2830.960000 0.000000 2836.240000 0.765000 ;
      RECT 2824.980000 0.000000 2830.260000 0.765000 ;
      RECT 2819.460000 0.000000 2824.280000 0.765000 ;
      RECT 2813.480000 0.000000 2818.760000 0.765000 ;
      RECT 2807.500000 0.000000 2812.780000 0.765000 ;
      RECT 2801.980000 0.000000 2806.800000 0.765000 ;
      RECT 2796.000000 0.000000 2801.280000 0.765000 ;
      RECT 2790.020000 0.000000 2795.300000 0.765000 ;
      RECT 2784.500000 0.000000 2789.320000 0.765000 ;
      RECT 2778.520000 0.000000 2783.800000 0.765000 ;
      RECT 2772.540000 0.000000 2777.820000 0.765000 ;
      RECT 2767.020000 0.000000 2771.840000 0.765000 ;
      RECT 2761.040000 0.000000 2766.320000 0.765000 ;
      RECT 2755.060000 0.000000 2760.340000 0.765000 ;
      RECT 2749.080000 0.000000 2754.360000 0.765000 ;
      RECT 2743.560000 0.000000 2748.380000 0.765000 ;
      RECT 2737.580000 0.000000 2742.860000 0.765000 ;
      RECT 2731.600000 0.000000 2736.880000 0.765000 ;
      RECT 2726.080000 0.000000 2730.900000 0.765000 ;
      RECT 2720.100000 0.000000 2725.380000 0.765000 ;
      RECT 2714.120000 0.000000 2719.400000 0.765000 ;
      RECT 2708.600000 0.000000 2713.420000 0.765000 ;
      RECT 2702.620000 0.000000 2707.900000 0.765000 ;
      RECT 2696.640000 0.000000 2701.920000 0.765000 ;
      RECT 2691.120000 0.000000 2695.940000 0.765000 ;
      RECT 2685.140000 0.000000 2690.420000 0.765000 ;
      RECT 2679.160000 0.000000 2684.440000 0.765000 ;
      RECT 2673.640000 0.000000 2678.460000 0.765000 ;
      RECT 2667.660000 0.000000 2672.940000 0.765000 ;
      RECT 2661.680000 0.000000 2666.960000 0.765000 ;
      RECT 2655.700000 0.000000 2660.980000 0.765000 ;
      RECT 2650.180000 0.000000 2655.000000 0.765000 ;
      RECT 2644.200000 0.000000 2649.480000 0.765000 ;
      RECT 2638.220000 0.000000 2643.500000 0.765000 ;
      RECT 2632.700000 0.000000 2637.520000 0.765000 ;
      RECT 2626.720000 0.000000 2632.000000 0.765000 ;
      RECT 2620.740000 0.000000 2626.020000 0.765000 ;
      RECT 2615.220000 0.000000 2620.040000 0.765000 ;
      RECT 2609.240000 0.000000 2614.520000 0.765000 ;
      RECT 2603.260000 0.000000 2608.540000 0.765000 ;
      RECT 2597.740000 0.000000 2602.560000 0.765000 ;
      RECT 2591.760000 0.000000 2597.040000 0.765000 ;
      RECT 2585.780000 0.000000 2591.060000 0.765000 ;
      RECT 2580.260000 0.000000 2585.080000 0.765000 ;
      RECT 2574.280000 0.000000 2579.560000 0.765000 ;
      RECT 2568.300000 0.000000 2573.580000 0.765000 ;
      RECT 2562.780000 0.000000 2567.600000 0.765000 ;
      RECT 2556.800000 0.000000 2562.080000 0.765000 ;
      RECT 2550.820000 0.000000 2556.100000 0.765000 ;
      RECT 2544.840000 0.000000 2550.120000 0.765000 ;
      RECT 2539.320000 0.000000 2544.140000 0.765000 ;
      RECT 2533.340000 0.000000 2538.620000 0.765000 ;
      RECT 2527.360000 0.000000 2532.640000 0.765000 ;
      RECT 2521.840000 0.000000 2526.660000 0.765000 ;
      RECT 2515.860000 0.000000 2521.140000 0.765000 ;
      RECT 2509.880000 0.000000 2515.160000 0.765000 ;
      RECT 2504.360000 0.000000 2509.180000 0.765000 ;
      RECT 2498.380000 0.000000 2503.660000 0.765000 ;
      RECT 2492.400000 0.000000 2497.680000 0.765000 ;
      RECT 2486.880000 0.000000 2491.700000 0.765000 ;
      RECT 2480.900000 0.000000 2486.180000 0.765000 ;
      RECT 2474.920000 0.000000 2480.200000 0.765000 ;
      RECT 2469.400000 0.000000 2474.220000 0.765000 ;
      RECT 2463.420000 0.000000 2468.700000 0.765000 ;
      RECT 2457.440000 0.000000 2462.720000 0.765000 ;
      RECT 2451.460000 0.000000 2456.740000 0.765000 ;
      RECT 2445.940000 0.000000 2450.760000 0.765000 ;
      RECT 2439.960000 0.000000 2445.240000 0.765000 ;
      RECT 2433.980000 0.000000 2439.260000 0.765000 ;
      RECT 2428.460000 0.000000 2433.280000 0.765000 ;
      RECT 2422.480000 0.000000 2427.760000 0.765000 ;
      RECT 2416.500000 0.000000 2421.780000 0.765000 ;
      RECT 2410.980000 0.000000 2415.800000 0.765000 ;
      RECT 2405.000000 0.000000 2410.280000 0.765000 ;
      RECT 2399.020000 0.000000 2404.300000 0.765000 ;
      RECT 2393.500000 0.000000 2398.320000 0.765000 ;
      RECT 2387.520000 0.000000 2392.800000 0.765000 ;
      RECT 2381.540000 0.000000 2386.820000 0.765000 ;
      RECT 2376.020000 0.000000 2380.840000 0.765000 ;
      RECT 2370.040000 0.000000 2375.320000 0.765000 ;
      RECT 2364.060000 0.000000 2369.340000 0.765000 ;
      RECT 2358.540000 0.000000 2363.360000 0.765000 ;
      RECT 2352.560000 0.000000 2357.840000 0.765000 ;
      RECT 2346.580000 0.000000 2351.860000 0.765000 ;
      RECT 2340.600000 0.000000 2345.880000 0.765000 ;
      RECT 2335.080000 0.000000 2339.900000 0.765000 ;
      RECT 2329.100000 0.000000 2334.380000 0.765000 ;
      RECT 2323.120000 0.000000 2328.400000 0.765000 ;
      RECT 2317.600000 0.000000 2322.420000 0.765000 ;
      RECT 2311.620000 0.000000 2316.900000 0.765000 ;
      RECT 2305.640000 0.000000 2310.920000 0.765000 ;
      RECT 2300.120000 0.000000 2304.940000 0.765000 ;
      RECT 2294.140000 0.000000 2299.420000 0.765000 ;
      RECT 2288.160000 0.000000 2293.440000 0.765000 ;
      RECT 2282.640000 0.000000 2287.460000 0.765000 ;
      RECT 2276.660000 0.000000 2281.940000 0.765000 ;
      RECT 2270.680000 0.000000 2275.960000 0.765000 ;
      RECT 2265.160000 0.000000 2269.980000 0.765000 ;
      RECT 2259.180000 0.000000 2264.460000 0.765000 ;
      RECT 2253.200000 0.000000 2258.480000 0.765000 ;
      RECT 2247.220000 0.000000 2252.500000 0.765000 ;
      RECT 2241.700000 0.000000 2246.520000 0.765000 ;
      RECT 2235.720000 0.000000 2241.000000 0.765000 ;
      RECT 2229.740000 0.000000 2235.020000 0.765000 ;
      RECT 2224.220000 0.000000 2229.040000 0.765000 ;
      RECT 2218.240000 0.000000 2223.520000 0.765000 ;
      RECT 2212.260000 0.000000 2217.540000 0.765000 ;
      RECT 2206.740000 0.000000 2211.560000 0.765000 ;
      RECT 2200.760000 0.000000 2206.040000 0.765000 ;
      RECT 2194.780000 0.000000 2200.060000 0.765000 ;
      RECT 2189.260000 0.000000 2194.080000 0.765000 ;
      RECT 2183.280000 0.000000 2188.560000 0.765000 ;
      RECT 2177.300000 0.000000 2182.580000 0.765000 ;
      RECT 2171.780000 0.000000 2176.600000 0.765000 ;
      RECT 2165.800000 0.000000 2171.080000 0.765000 ;
      RECT 2159.820000 0.000000 2165.100000 0.765000 ;
      RECT 2154.300000 0.000000 2159.120000 0.765000 ;
      RECT 2148.320000 0.000000 2153.600000 0.765000 ;
      RECT 2142.340000 0.000000 2147.620000 0.765000 ;
      RECT 2136.360000 0.000000 2141.640000 0.765000 ;
      RECT 2130.840000 0.000000 2135.660000 0.765000 ;
      RECT 2124.860000 0.000000 2130.140000 0.765000 ;
      RECT 2118.880000 0.000000 2124.160000 0.765000 ;
      RECT 2113.360000 0.000000 2118.180000 0.765000 ;
      RECT 2107.380000 0.000000 2112.660000 0.765000 ;
      RECT 2101.400000 0.000000 2106.680000 0.765000 ;
      RECT 2095.880000 0.000000 2100.700000 0.765000 ;
      RECT 2089.900000 0.000000 2095.180000 0.765000 ;
      RECT 2083.920000 0.000000 2089.200000 0.765000 ;
      RECT 2078.400000 0.000000 2083.220000 0.765000 ;
      RECT 2072.420000 0.000000 2077.700000 0.765000 ;
      RECT 2066.440000 0.000000 2071.720000 0.765000 ;
      RECT 2060.920000 0.000000 2065.740000 0.765000 ;
      RECT 2054.940000 0.000000 2060.220000 0.765000 ;
      RECT 2048.960000 0.000000 2054.240000 0.765000 ;
      RECT 2042.980000 0.000000 2048.260000 0.765000 ;
      RECT 2037.460000 0.000000 2042.280000 0.765000 ;
      RECT 2031.480000 0.000000 2036.760000 0.765000 ;
      RECT 2025.500000 0.000000 2030.780000 0.765000 ;
      RECT 2019.980000 0.000000 2024.800000 0.765000 ;
      RECT 2014.000000 0.000000 2019.280000 0.765000 ;
      RECT 2008.020000 0.000000 2013.300000 0.765000 ;
      RECT 2002.500000 0.000000 2007.320000 0.765000 ;
      RECT 1996.520000 0.000000 2001.800000 0.765000 ;
      RECT 1990.540000 0.000000 1995.820000 0.765000 ;
      RECT 1985.020000 0.000000 1989.840000 0.765000 ;
      RECT 1979.040000 0.000000 1984.320000 0.765000 ;
      RECT 1973.060000 0.000000 1978.340000 0.765000 ;
      RECT 1967.540000 0.000000 1972.360000 0.765000 ;
      RECT 1961.560000 0.000000 1966.840000 0.765000 ;
      RECT 1955.580000 0.000000 1960.860000 0.765000 ;
      RECT 1950.060000 0.000000 1954.880000 0.765000 ;
      RECT 1944.080000 0.000000 1949.360000 0.765000 ;
      RECT 1938.100000 0.000000 1943.380000 0.765000 ;
      RECT 1932.120000 0.000000 1937.400000 0.765000 ;
      RECT 1926.600000 0.000000 1931.420000 0.765000 ;
      RECT 1920.620000 0.000000 1925.900000 0.765000 ;
      RECT 1914.640000 0.000000 1919.920000 0.765000 ;
      RECT 1909.120000 0.000000 1913.940000 0.765000 ;
      RECT 1903.140000 0.000000 1908.420000 0.765000 ;
      RECT 1897.160000 0.000000 1902.440000 0.765000 ;
      RECT 1891.640000 0.000000 1896.460000 0.765000 ;
      RECT 1885.660000 0.000000 1890.940000 0.765000 ;
      RECT 1879.680000 0.000000 1884.960000 0.765000 ;
      RECT 1874.160000 0.000000 1878.980000 0.765000 ;
      RECT 1868.180000 0.000000 1873.460000 0.765000 ;
      RECT 1862.200000 0.000000 1867.480000 0.765000 ;
      RECT 1856.680000 0.000000 1861.500000 0.765000 ;
      RECT 1850.700000 0.000000 1855.980000 0.765000 ;
      RECT 1844.720000 0.000000 1850.000000 0.765000 ;
      RECT 1838.740000 0.000000 1844.020000 0.765000 ;
      RECT 1833.220000 0.000000 1838.040000 0.765000 ;
      RECT 1827.240000 0.000000 1832.520000 0.765000 ;
      RECT 1821.260000 0.000000 1826.540000 0.765000 ;
      RECT 1815.740000 0.000000 1820.560000 0.765000 ;
      RECT 1809.760000 0.000000 1815.040000 0.765000 ;
      RECT 1803.780000 0.000000 1809.060000 0.765000 ;
      RECT 1798.260000 0.000000 1803.080000 0.765000 ;
      RECT 1792.280000 0.000000 1797.560000 0.765000 ;
      RECT 1786.300000 0.000000 1791.580000 0.765000 ;
      RECT 1780.780000 0.000000 1785.600000 0.765000 ;
      RECT 1774.800000 0.000000 1780.080000 0.765000 ;
      RECT 1768.820000 0.000000 1774.100000 0.765000 ;
      RECT 1763.300000 0.000000 1768.120000 0.765000 ;
      RECT 1757.320000 0.000000 1762.600000 0.765000 ;
      RECT 1751.340000 0.000000 1756.620000 0.765000 ;
      RECT 1745.820000 0.000000 1750.640000 0.765000 ;
      RECT 1739.840000 0.000000 1745.120000 0.765000 ;
      RECT 1733.860000 0.000000 1739.140000 0.765000 ;
      RECT 1727.880000 0.000000 1733.160000 0.765000 ;
      RECT 1722.360000 0.000000 1727.180000 0.765000 ;
      RECT 1716.380000 0.000000 1721.660000 0.765000 ;
      RECT 1710.400000 0.000000 1715.680000 0.765000 ;
      RECT 1704.880000 0.000000 1709.700000 0.765000 ;
      RECT 1698.900000 0.000000 1704.180000 0.765000 ;
      RECT 1692.920000 0.000000 1698.200000 0.765000 ;
      RECT 1687.400000 0.000000 1692.220000 0.765000 ;
      RECT 1681.420000 0.000000 1686.700000 0.765000 ;
      RECT 1675.440000 0.000000 1680.720000 0.765000 ;
      RECT 1669.920000 0.000000 1674.740000 0.765000 ;
      RECT 1663.940000 0.000000 1669.220000 0.765000 ;
      RECT 1657.960000 0.000000 1663.240000 0.765000 ;
      RECT 1652.440000 0.000000 1657.260000 0.765000 ;
      RECT 1646.460000 0.000000 1651.740000 0.765000 ;
      RECT 1640.480000 0.000000 1645.760000 0.765000 ;
      RECT 1634.500000 0.000000 1639.780000 0.765000 ;
      RECT 1628.980000 0.000000 1633.800000 0.765000 ;
      RECT 1623.000000 0.000000 1628.280000 0.765000 ;
      RECT 1617.020000 0.000000 1622.300000 0.765000 ;
      RECT 1611.500000 0.000000 1616.320000 0.765000 ;
      RECT 1605.520000 0.000000 1610.800000 0.765000 ;
      RECT 1599.540000 0.000000 1604.820000 0.765000 ;
      RECT 1594.020000 0.000000 1598.840000 0.765000 ;
      RECT 1588.040000 0.000000 1593.320000 0.765000 ;
      RECT 1582.060000 0.000000 1587.340000 0.765000 ;
      RECT 1576.540000 0.000000 1581.360000 0.765000 ;
      RECT 1570.560000 0.000000 1575.840000 0.765000 ;
      RECT 1564.580000 0.000000 1569.860000 0.765000 ;
      RECT 1559.060000 0.000000 1563.880000 0.765000 ;
      RECT 1553.080000 0.000000 1558.360000 0.765000 ;
      RECT 1547.100000 0.000000 1552.380000 0.765000 ;
      RECT 1541.580000 0.000000 1546.400000 0.765000 ;
      RECT 1535.600000 0.000000 1540.880000 0.765000 ;
      RECT 1529.620000 0.000000 1534.900000 0.765000 ;
      RECT 1523.640000 0.000000 1528.920000 0.765000 ;
      RECT 1518.120000 0.000000 1522.940000 0.765000 ;
      RECT 1512.140000 0.000000 1517.420000 0.765000 ;
      RECT 1506.160000 0.000000 1511.440000 0.765000 ;
      RECT 1500.640000 0.000000 1505.460000 0.765000 ;
      RECT 1494.660000 0.000000 1499.940000 0.765000 ;
      RECT 1488.680000 0.000000 1493.960000 0.765000 ;
      RECT 1483.160000 0.000000 1487.980000 0.765000 ;
      RECT 1477.180000 0.000000 1482.460000 0.765000 ;
      RECT 1471.200000 0.000000 1476.480000 0.765000 ;
      RECT 1465.680000 0.000000 1470.500000 0.765000 ;
      RECT 1459.700000 0.000000 1464.980000 0.765000 ;
      RECT 1453.720000 0.000000 1459.000000 0.765000 ;
      RECT 1448.200000 0.000000 1453.020000 0.765000 ;
      RECT 1442.220000 0.000000 1447.500000 0.765000 ;
      RECT 1436.240000 0.000000 1441.520000 0.765000 ;
      RECT 1430.260000 0.000000 1435.540000 0.765000 ;
      RECT 1424.740000 0.000000 1429.560000 0.765000 ;
      RECT 1418.760000 0.000000 1424.040000 0.765000 ;
      RECT 1412.780000 0.000000 1418.060000 0.765000 ;
      RECT 1407.260000 0.000000 1412.080000 0.765000 ;
      RECT 1401.280000 0.000000 1406.560000 0.765000 ;
      RECT 1395.300000 0.000000 1400.580000 0.765000 ;
      RECT 1389.780000 0.000000 1394.600000 0.765000 ;
      RECT 1383.800000 0.000000 1389.080000 0.765000 ;
      RECT 1377.820000 0.000000 1383.100000 0.765000 ;
      RECT 1372.300000 0.000000 1377.120000 0.765000 ;
      RECT 1366.320000 0.000000 1371.600000 0.765000 ;
      RECT 1360.340000 0.000000 1365.620000 0.765000 ;
      RECT 1354.820000 0.000000 1359.640000 0.765000 ;
      RECT 1348.840000 0.000000 1354.120000 0.765000 ;
      RECT 1342.860000 0.000000 1348.140000 0.765000 ;
      RECT 1337.340000 0.000000 1342.160000 0.765000 ;
      RECT 1331.360000 0.000000 1336.640000 0.765000 ;
      RECT 1325.380000 0.000000 1330.660000 0.765000 ;
      RECT 1319.400000 0.000000 1324.680000 0.765000 ;
      RECT 1313.880000 0.000000 1318.700000 0.765000 ;
      RECT 1307.900000 0.000000 1313.180000 0.765000 ;
      RECT 1301.920000 0.000000 1307.200000 0.765000 ;
      RECT 1296.400000 0.000000 1301.220000 0.765000 ;
      RECT 1290.420000 0.000000 1295.700000 0.765000 ;
      RECT 1284.440000 0.000000 1289.720000 0.765000 ;
      RECT 1278.920000 0.000000 1283.740000 0.765000 ;
      RECT 1272.940000 0.000000 1278.220000 0.765000 ;
      RECT 1266.960000 0.000000 1272.240000 0.765000 ;
      RECT 1261.440000 0.000000 1266.260000 0.765000 ;
      RECT 1255.460000 0.000000 1260.740000 0.765000 ;
      RECT 1249.480000 0.000000 1254.760000 0.765000 ;
      RECT 1243.960000 0.000000 1248.780000 0.765000 ;
      RECT 1237.980000 0.000000 1243.260000 0.765000 ;
      RECT 1232.000000 0.000000 1237.280000 0.765000 ;
      RECT 1226.020000 0.000000 1231.300000 0.765000 ;
      RECT 1220.500000 0.000000 1225.320000 0.765000 ;
      RECT 1214.520000 0.000000 1219.800000 0.765000 ;
      RECT 1208.540000 0.000000 1213.820000 0.765000 ;
      RECT 1203.020000 0.000000 1207.840000 0.765000 ;
      RECT 1197.040000 0.000000 1202.320000 0.765000 ;
      RECT 1191.060000 0.000000 1196.340000 0.765000 ;
      RECT 1185.540000 0.000000 1190.360000 0.765000 ;
      RECT 1179.560000 0.000000 1184.840000 0.765000 ;
      RECT 1173.580000 0.000000 1178.860000 0.765000 ;
      RECT 1168.060000 0.000000 1172.880000 0.765000 ;
      RECT 1162.080000 0.000000 1167.360000 0.765000 ;
      RECT 1156.100000 0.000000 1161.380000 0.765000 ;
      RECT 1150.580000 0.000000 1155.400000 0.765000 ;
      RECT 1144.600000 0.000000 1149.880000 0.765000 ;
      RECT 1138.620000 0.000000 1143.900000 0.765000 ;
      RECT 1133.100000 0.000000 1137.920000 0.765000 ;
      RECT 1127.120000 0.000000 1132.400000 0.765000 ;
      RECT 1121.140000 0.000000 1126.420000 0.765000 ;
      RECT 1115.160000 0.000000 1120.440000 0.765000 ;
      RECT 1109.640000 0.000000 1114.460000 0.765000 ;
      RECT 1103.660000 0.000000 1108.940000 0.765000 ;
      RECT 1097.680000 0.000000 1102.960000 0.765000 ;
      RECT 1092.160000 0.000000 1096.980000 0.765000 ;
      RECT 1086.180000 0.000000 1091.460000 0.765000 ;
      RECT 1080.200000 0.000000 1085.480000 0.765000 ;
      RECT 1074.680000 0.000000 1079.500000 0.765000 ;
      RECT 1068.700000 0.000000 1073.980000 0.765000 ;
      RECT 1062.720000 0.000000 1068.000000 0.765000 ;
      RECT 1057.200000 0.000000 1062.020000 0.765000 ;
      RECT 1051.220000 0.000000 1056.500000 0.765000 ;
      RECT 1045.240000 0.000000 1050.520000 0.765000 ;
      RECT 1039.720000 0.000000 1044.540000 0.765000 ;
      RECT 1033.740000 0.000000 1039.020000 0.765000 ;
      RECT 1027.760000 0.000000 1033.040000 0.765000 ;
      RECT 1021.780000 0.000000 1027.060000 0.765000 ;
      RECT 1016.260000 0.000000 1021.080000 0.765000 ;
      RECT 1010.280000 0.000000 1015.560000 0.765000 ;
      RECT 1004.300000 0.000000 1009.580000 0.765000 ;
      RECT 998.780000 0.000000 1003.600000 0.765000 ;
      RECT 992.800000 0.000000 998.080000 0.765000 ;
      RECT 986.820000 0.000000 992.100000 0.765000 ;
      RECT 981.300000 0.000000 986.120000 0.765000 ;
      RECT 975.320000 0.000000 980.600000 0.765000 ;
      RECT 969.340000 0.000000 974.620000 0.765000 ;
      RECT 963.820000 0.000000 968.640000 0.765000 ;
      RECT 957.840000 0.000000 963.120000 0.765000 ;
      RECT 951.860000 0.000000 957.140000 0.765000 ;
      RECT 946.340000 0.000000 951.160000 0.765000 ;
      RECT 940.360000 0.000000 945.640000 0.765000 ;
      RECT 934.380000 0.000000 939.660000 0.765000 ;
      RECT 928.860000 0.000000 933.680000 0.765000 ;
      RECT 922.880000 0.000000 928.160000 0.765000 ;
      RECT 916.900000 0.000000 922.180000 0.765000 ;
      RECT 910.920000 0.000000 916.200000 0.765000 ;
      RECT 905.400000 0.000000 910.220000 0.765000 ;
      RECT 899.420000 0.000000 904.700000 0.765000 ;
      RECT 893.440000 0.000000 898.720000 0.765000 ;
      RECT 887.920000 0.000000 892.740000 0.765000 ;
      RECT 881.940000 0.000000 887.220000 0.765000 ;
      RECT 875.960000 0.000000 881.240000 0.765000 ;
      RECT 870.440000 0.000000 875.260000 0.765000 ;
      RECT 864.460000 0.000000 869.740000 0.765000 ;
      RECT 858.480000 0.000000 863.760000 0.765000 ;
      RECT 852.960000 0.000000 857.780000 0.765000 ;
      RECT 846.980000 0.000000 852.260000 0.765000 ;
      RECT 841.000000 0.000000 846.280000 0.765000 ;
      RECT 835.480000 0.000000 840.300000 0.765000 ;
      RECT 829.500000 0.000000 834.780000 0.765000 ;
      RECT 823.520000 0.000000 828.800000 0.765000 ;
      RECT 817.540000 0.000000 822.820000 0.765000 ;
      RECT 812.020000 0.000000 816.840000 0.765000 ;
      RECT 806.040000 0.000000 811.320000 0.765000 ;
      RECT 800.060000 0.000000 805.340000 0.765000 ;
      RECT 794.540000 0.000000 799.360000 0.765000 ;
      RECT 788.560000 0.000000 793.840000 0.765000 ;
      RECT 782.580000 0.000000 787.860000 0.765000 ;
      RECT 777.060000 0.000000 781.880000 0.765000 ;
      RECT 771.080000 0.000000 776.360000 0.765000 ;
      RECT 765.100000 0.000000 770.380000 0.765000 ;
      RECT 759.580000 0.000000 764.400000 0.765000 ;
      RECT 753.600000 0.000000 758.880000 0.765000 ;
      RECT 747.620000 0.000000 752.900000 0.765000 ;
      RECT 742.100000 0.000000 746.920000 0.765000 ;
      RECT 736.120000 0.000000 741.400000 0.765000 ;
      RECT 730.140000 0.000000 735.420000 0.765000 ;
      RECT 724.620000 0.000000 729.440000 0.765000 ;
      RECT 718.640000 0.000000 723.920000 0.765000 ;
      RECT 712.660000 0.000000 717.940000 0.765000 ;
      RECT 706.680000 0.000000 711.960000 0.765000 ;
      RECT 701.160000 0.000000 705.980000 0.765000 ;
      RECT 695.180000 0.000000 700.460000 0.765000 ;
      RECT 689.200000 0.000000 694.480000 0.765000 ;
      RECT 683.680000 0.000000 688.500000 0.765000 ;
      RECT 677.700000 0.000000 682.980000 0.765000 ;
      RECT 671.720000 0.000000 677.000000 0.765000 ;
      RECT 666.200000 0.000000 671.020000 0.765000 ;
      RECT 660.220000 0.000000 665.500000 0.765000 ;
      RECT 654.240000 0.000000 659.520000 0.765000 ;
      RECT 648.720000 0.000000 653.540000 0.765000 ;
      RECT 642.740000 0.000000 648.020000 0.765000 ;
      RECT 636.760000 0.000000 642.040000 0.765000 ;
      RECT 631.240000 0.000000 636.060000 0.765000 ;
      RECT 625.260000 0.000000 630.540000 0.765000 ;
      RECT 619.280000 0.000000 624.560000 0.765000 ;
      RECT 613.300000 0.000000 618.580000 0.765000 ;
      RECT 607.780000 0.000000 612.600000 0.765000 ;
      RECT 601.800000 0.000000 607.080000 0.765000 ;
      RECT 595.820000 0.000000 601.100000 0.765000 ;
      RECT 590.300000 0.000000 595.120000 0.765000 ;
      RECT 584.320000 0.000000 589.600000 0.765000 ;
      RECT 578.340000 0.000000 583.620000 0.765000 ;
      RECT 572.820000 0.000000 577.640000 0.765000 ;
      RECT 566.840000 0.000000 572.120000 0.765000 ;
      RECT 560.860000 0.000000 566.140000 0.765000 ;
      RECT 555.340000 0.000000 560.160000 0.765000 ;
      RECT 549.360000 0.000000 554.640000 0.765000 ;
      RECT 543.380000 0.000000 548.660000 0.765000 ;
      RECT 537.860000 0.000000 542.680000 0.765000 ;
      RECT 531.880000 0.000000 537.160000 0.765000 ;
      RECT 525.900000 0.000000 531.180000 0.765000 ;
      RECT 520.380000 0.000000 525.200000 0.765000 ;
      RECT 514.400000 0.000000 519.680000 0.765000 ;
      RECT 508.420000 0.000000 513.700000 0.765000 ;
      RECT 502.440000 0.000000 507.720000 0.765000 ;
      RECT 496.920000 0.000000 501.740000 0.765000 ;
      RECT 490.940000 0.000000 496.220000 0.765000 ;
      RECT 484.960000 0.000000 490.240000 0.765000 ;
      RECT 479.440000 0.000000 484.260000 0.765000 ;
      RECT 473.460000 0.000000 478.740000 0.765000 ;
      RECT 467.480000 0.000000 472.760000 0.765000 ;
      RECT 461.960000 0.000000 466.780000 0.765000 ;
      RECT 455.980000 0.000000 461.260000 0.765000 ;
      RECT 450.000000 0.000000 455.280000 0.765000 ;
      RECT 444.480000 0.000000 449.300000 0.765000 ;
      RECT 438.500000 0.000000 443.780000 0.765000 ;
      RECT 432.520000 0.000000 437.800000 0.765000 ;
      RECT 427.000000 0.000000 431.820000 0.765000 ;
      RECT 421.020000 0.000000 426.300000 0.765000 ;
      RECT 415.040000 0.000000 420.320000 0.765000 ;
      RECT 409.060000 0.000000 414.340000 0.765000 ;
      RECT 403.540000 0.000000 408.360000 0.765000 ;
      RECT 397.560000 0.000000 402.840000 0.765000 ;
      RECT 391.580000 0.000000 396.860000 0.765000 ;
      RECT 386.060000 0.000000 390.880000 0.765000 ;
      RECT 380.080000 0.000000 385.360000 0.765000 ;
      RECT 374.100000 0.000000 379.380000 0.765000 ;
      RECT 368.580000 0.000000 373.400000 0.765000 ;
      RECT 362.600000 0.000000 367.880000 0.765000 ;
      RECT 356.620000 0.000000 361.900000 0.765000 ;
      RECT 351.100000 0.000000 355.920000 0.765000 ;
      RECT 345.120000 0.000000 350.400000 0.765000 ;
      RECT 339.140000 0.000000 344.420000 0.765000 ;
      RECT 333.620000 0.000000 338.440000 0.765000 ;
      RECT 327.640000 0.000000 332.920000 0.765000 ;
      RECT 321.660000 0.000000 326.940000 0.765000 ;
      RECT 316.140000 0.000000 320.960000 0.765000 ;
      RECT 310.160000 0.000000 315.440000 0.765000 ;
      RECT 304.180000 0.000000 309.460000 0.765000 ;
      RECT 298.200000 0.000000 303.480000 0.765000 ;
      RECT 292.680000 0.000000 297.500000 0.765000 ;
      RECT 286.700000 0.000000 291.980000 0.765000 ;
      RECT 280.720000 0.000000 286.000000 0.765000 ;
      RECT 275.200000 0.000000 280.020000 0.765000 ;
      RECT 269.220000 0.000000 274.500000 0.765000 ;
      RECT 263.240000 0.000000 268.520000 0.765000 ;
      RECT 257.720000 0.000000 262.540000 0.765000 ;
      RECT 251.740000 0.000000 257.020000 0.765000 ;
      RECT 245.760000 0.000000 251.040000 0.765000 ;
      RECT 240.240000 0.000000 245.060000 0.765000 ;
      RECT 234.260000 0.000000 239.540000 0.765000 ;
      RECT 228.280000 0.000000 233.560000 0.765000 ;
      RECT 222.760000 0.000000 227.580000 0.765000 ;
      RECT 216.780000 0.000000 222.060000 0.765000 ;
      RECT 210.800000 0.000000 216.080000 0.765000 ;
      RECT 204.820000 0.000000 210.100000 0.765000 ;
      RECT 199.300000 0.000000 204.120000 0.765000 ;
      RECT 193.320000 0.000000 198.600000 0.765000 ;
      RECT 187.340000 0.000000 192.620000 0.765000 ;
      RECT 181.820000 0.000000 186.640000 0.765000 ;
      RECT 175.840000 0.000000 181.120000 0.765000 ;
      RECT 169.860000 0.000000 175.140000 0.765000 ;
      RECT 164.340000 0.000000 169.160000 0.765000 ;
      RECT 158.360000 0.000000 163.640000 0.765000 ;
      RECT 152.380000 0.000000 157.660000 0.765000 ;
      RECT 146.860000 0.000000 151.680000 0.765000 ;
      RECT 140.880000 0.000000 146.160000 0.765000 ;
      RECT 134.900000 0.000000 140.180000 0.765000 ;
      RECT 129.380000 0.000000 134.200000 0.765000 ;
      RECT 123.400000 0.000000 128.680000 0.765000 ;
      RECT 117.420000 0.000000 122.700000 0.765000 ;
      RECT 111.900000 0.000000 116.720000 0.765000 ;
      RECT 105.920000 0.000000 111.200000 0.765000 ;
      RECT 99.940000 0.000000 105.220000 0.765000 ;
      RECT 93.960000 0.000000 99.240000 0.765000 ;
      RECT 88.440000 0.000000 93.260000 0.765000 ;
      RECT 82.460000 0.000000 87.740000 0.765000 ;
      RECT 76.480000 0.000000 81.760000 0.765000 ;
      RECT 70.960000 0.000000 75.780000 0.765000 ;
      RECT 64.980000 0.000000 70.260000 0.765000 ;
      RECT 59.000000 0.000000 64.280000 0.765000 ;
      RECT 53.480000 0.000000 58.300000 0.765000 ;
      RECT 47.500000 0.000000 52.780000 0.765000 ;
      RECT 41.520000 0.000000 46.800000 0.765000 ;
      RECT 36.000000 0.000000 40.820000 0.765000 ;
      RECT 30.020000 0.000000 35.300000 0.765000 ;
      RECT 24.040000 0.000000 29.320000 0.765000 ;
      RECT 18.520000 0.000000 23.340000 0.765000 ;
      RECT 12.540000 0.000000 17.820000 0.765000 ;
      RECT 6.560000 0.000000 11.840000 0.765000 ;
      RECT 0.580000 0.000000 5.860000 0.765000 ;
    LAYER met3 ;
      RECT 1.200000 3469.190000 2858.620000 3470.040000 ;
      RECT 0.000000 3404.410000 2859.820000 3469.190000 ;
      RECT 1.200000 3403.800000 2859.820000 3404.410000 ;
      RECT 1.200000 3403.310000 2858.620000 3403.800000 ;
      RECT 0.000000 3402.700000 2858.620000 3403.310000 ;
      RECT 0.000000 3339.140000 2859.820000 3402.700000 ;
      RECT 1.200000 3338.040000 2859.820000 3339.140000 ;
      RECT 0.000000 3337.310000 2859.820000 3338.040000 ;
      RECT 0.000000 3336.210000 2858.620000 3337.310000 ;
      RECT 0.000000 3273.870000 2859.820000 3336.210000 ;
      RECT 1.200000 3272.770000 2859.820000 3273.870000 ;
      RECT 0.000000 3270.210000 2859.820000 3272.770000 ;
      RECT 0.000000 3269.110000 2858.620000 3270.210000 ;
      RECT 0.000000 3207.990000 2859.820000 3269.110000 ;
      RECT 1.200000 3206.890000 2859.820000 3207.990000 ;
      RECT 0.000000 3203.720000 2859.820000 3206.890000 ;
      RECT 0.000000 3202.620000 2858.620000 3203.720000 ;
      RECT 0.000000 3142.720000 2859.820000 3202.620000 ;
      RECT 1.200000 3141.620000 2859.820000 3142.720000 ;
      RECT 0.000000 3137.230000 2859.820000 3141.620000 ;
      RECT 0.000000 3136.130000 2858.620000 3137.230000 ;
      RECT 0.000000 3077.450000 2859.820000 3136.130000 ;
      RECT 1.200000 3076.350000 2859.820000 3077.450000 ;
      RECT 0.000000 3070.130000 2859.820000 3076.350000 ;
      RECT 0.000000 3069.030000 2858.620000 3070.130000 ;
      RECT 0.000000 3011.570000 2859.820000 3069.030000 ;
      RECT 1.200000 3010.470000 2859.820000 3011.570000 ;
      RECT 0.000000 3003.640000 2859.820000 3010.470000 ;
      RECT 0.000000 3002.540000 2858.620000 3003.640000 ;
      RECT 0.000000 2946.300000 2859.820000 3002.540000 ;
      RECT 1.200000 2945.200000 2859.820000 2946.300000 ;
      RECT 0.000000 2937.150000 2859.820000 2945.200000 ;
      RECT 0.000000 2936.050000 2858.620000 2937.150000 ;
      RECT 0.000000 2881.030000 2859.820000 2936.050000 ;
      RECT 1.200000 2879.930000 2859.820000 2881.030000 ;
      RECT 0.000000 2870.050000 2859.820000 2879.930000 ;
      RECT 0.000000 2868.950000 2858.620000 2870.050000 ;
      RECT 0.000000 2815.150000 2859.820000 2868.950000 ;
      RECT 1.200000 2814.050000 2859.820000 2815.150000 ;
      RECT 0.000000 2803.560000 2859.820000 2814.050000 ;
      RECT 0.000000 2802.460000 2858.620000 2803.560000 ;
      RECT 0.000000 2749.880000 2859.820000 2802.460000 ;
      RECT 1.200000 2748.780000 2859.820000 2749.880000 ;
      RECT 0.000000 2736.460000 2859.820000 2748.780000 ;
      RECT 0.000000 2735.360000 2858.620000 2736.460000 ;
      RECT 0.000000 2684.610000 2859.820000 2735.360000 ;
      RECT 1.200000 2683.510000 2859.820000 2684.610000 ;
      RECT 0.000000 2669.970000 2859.820000 2683.510000 ;
      RECT 0.000000 2668.870000 2858.620000 2669.970000 ;
      RECT 0.000000 2619.340000 2859.820000 2668.870000 ;
      RECT 1.200000 2618.240000 2859.820000 2619.340000 ;
      RECT 0.000000 2603.480000 2859.820000 2618.240000 ;
      RECT 0.000000 2602.380000 2858.620000 2603.480000 ;
      RECT 0.000000 2553.460000 2859.820000 2602.380000 ;
      RECT 1.200000 2552.360000 2859.820000 2553.460000 ;
      RECT 0.000000 2536.380000 2859.820000 2552.360000 ;
      RECT 0.000000 2535.280000 2858.620000 2536.380000 ;
      RECT 0.000000 2488.190000 2859.820000 2535.280000 ;
      RECT 1.200000 2487.090000 2859.820000 2488.190000 ;
      RECT 0.000000 2469.890000 2859.820000 2487.090000 ;
      RECT 0.000000 2468.790000 2858.620000 2469.890000 ;
      RECT 0.000000 2422.920000 2859.820000 2468.790000 ;
      RECT 1.200000 2421.820000 2859.820000 2422.920000 ;
      RECT 0.000000 2403.400000 2859.820000 2421.820000 ;
      RECT 0.000000 2402.300000 2858.620000 2403.400000 ;
      RECT 0.000000 2357.040000 2859.820000 2402.300000 ;
      RECT 1.200000 2355.940000 2859.820000 2357.040000 ;
      RECT 0.000000 2336.300000 2859.820000 2355.940000 ;
      RECT 0.000000 2335.200000 2858.620000 2336.300000 ;
      RECT 0.000000 2291.770000 2859.820000 2335.200000 ;
      RECT 1.200000 2290.670000 2859.820000 2291.770000 ;
      RECT 0.000000 2269.810000 2859.820000 2290.670000 ;
      RECT 0.000000 2268.710000 2858.620000 2269.810000 ;
      RECT 0.000000 2226.500000 2859.820000 2268.710000 ;
      RECT 1.200000 2225.400000 2859.820000 2226.500000 ;
      RECT 0.000000 2203.320000 2859.820000 2225.400000 ;
      RECT 0.000000 2202.220000 2858.620000 2203.320000 ;
      RECT 0.000000 2160.620000 2859.820000 2202.220000 ;
      RECT 1.200000 2159.520000 2859.820000 2160.620000 ;
      RECT 0.000000 2136.220000 2859.820000 2159.520000 ;
      RECT 0.000000 2135.120000 2858.620000 2136.220000 ;
      RECT 0.000000 2095.350000 2859.820000 2135.120000 ;
      RECT 1.200000 2094.250000 2859.820000 2095.350000 ;
      RECT 0.000000 2069.730000 2859.820000 2094.250000 ;
      RECT 0.000000 2068.630000 2858.620000 2069.730000 ;
      RECT 0.000000 2030.080000 2859.820000 2068.630000 ;
      RECT 1.200000 2028.980000 2859.820000 2030.080000 ;
      RECT 0.000000 2002.630000 2859.820000 2028.980000 ;
      RECT 0.000000 2001.530000 2858.620000 2002.630000 ;
      RECT 0.000000 1964.810000 2859.820000 2001.530000 ;
      RECT 1.200000 1963.710000 2859.820000 1964.810000 ;
      RECT 0.000000 1936.140000 2859.820000 1963.710000 ;
      RECT 0.000000 1935.040000 2858.620000 1936.140000 ;
      RECT 0.000000 1898.930000 2859.820000 1935.040000 ;
      RECT 1.200000 1897.830000 2859.820000 1898.930000 ;
      RECT 0.000000 1869.650000 2859.820000 1897.830000 ;
      RECT 0.000000 1868.550000 2858.620000 1869.650000 ;
      RECT 0.000000 1833.660000 2859.820000 1868.550000 ;
      RECT 1.200000 1832.560000 2859.820000 1833.660000 ;
      RECT 0.000000 1802.550000 2859.820000 1832.560000 ;
      RECT 0.000000 1801.450000 2858.620000 1802.550000 ;
      RECT 0.000000 1768.390000 2859.820000 1801.450000 ;
      RECT 1.200000 1767.290000 2859.820000 1768.390000 ;
      RECT 0.000000 1736.060000 2859.820000 1767.290000 ;
      RECT 0.000000 1734.960000 2858.620000 1736.060000 ;
      RECT 0.000000 1702.510000 2859.820000 1734.960000 ;
      RECT 1.200000 1701.410000 2859.820000 1702.510000 ;
      RECT 0.000000 1669.570000 2859.820000 1701.410000 ;
      RECT 0.000000 1668.470000 2858.620000 1669.570000 ;
      RECT 0.000000 1637.240000 2859.820000 1668.470000 ;
      RECT 1.200000 1636.140000 2859.820000 1637.240000 ;
      RECT 0.000000 1602.470000 2859.820000 1636.140000 ;
      RECT 0.000000 1601.370000 2858.620000 1602.470000 ;
      RECT 0.000000 1571.970000 2859.820000 1601.370000 ;
      RECT 1.200000 1570.870000 2859.820000 1571.970000 ;
      RECT 0.000000 1535.980000 2859.820000 1570.870000 ;
      RECT 0.000000 1534.880000 2858.620000 1535.980000 ;
      RECT 0.000000 1506.090000 2859.820000 1534.880000 ;
      RECT 1.200000 1504.990000 2859.820000 1506.090000 ;
      RECT 0.000000 1469.490000 2859.820000 1504.990000 ;
      RECT 0.000000 1468.390000 2858.620000 1469.490000 ;
      RECT 0.000000 1440.820000 2859.820000 1468.390000 ;
      RECT 1.200000 1439.720000 2859.820000 1440.820000 ;
      RECT 0.000000 1402.390000 2859.820000 1439.720000 ;
      RECT 0.000000 1401.290000 2858.620000 1402.390000 ;
      RECT 0.000000 1375.550000 2859.820000 1401.290000 ;
      RECT 1.200000 1374.450000 2859.820000 1375.550000 ;
      RECT 0.000000 1335.900000 2859.820000 1374.450000 ;
      RECT 0.000000 1334.800000 2858.620000 1335.900000 ;
      RECT 0.000000 1310.280000 2859.820000 1334.800000 ;
      RECT 1.200000 1309.180000 2859.820000 1310.280000 ;
      RECT 0.000000 1268.800000 2859.820000 1309.180000 ;
      RECT 0.000000 1267.700000 2858.620000 1268.800000 ;
      RECT 0.000000 1244.400000 2859.820000 1267.700000 ;
      RECT 1.200000 1243.300000 2859.820000 1244.400000 ;
      RECT 0.000000 1202.310000 2859.820000 1243.300000 ;
      RECT 0.000000 1201.210000 2858.620000 1202.310000 ;
      RECT 0.000000 1179.130000 2859.820000 1201.210000 ;
      RECT 1.200000 1178.030000 2859.820000 1179.130000 ;
      RECT 0.000000 1135.820000 2859.820000 1178.030000 ;
      RECT 0.000000 1134.720000 2858.620000 1135.820000 ;
      RECT 0.000000 1113.860000 2859.820000 1134.720000 ;
      RECT 1.200000 1112.760000 2859.820000 1113.860000 ;
      RECT 0.000000 1068.720000 2859.820000 1112.760000 ;
      RECT 0.000000 1067.620000 2858.620000 1068.720000 ;
      RECT 0.000000 1047.980000 2859.820000 1067.620000 ;
      RECT 1.200000 1046.880000 2859.820000 1047.980000 ;
      RECT 0.000000 1002.230000 2859.820000 1046.880000 ;
      RECT 0.000000 1001.130000 2858.620000 1002.230000 ;
      RECT 0.000000 982.710000 2859.820000 1001.130000 ;
      RECT 1.200000 981.610000 2859.820000 982.710000 ;
      RECT 0.000000 935.740000 2859.820000 981.610000 ;
      RECT 0.000000 934.640000 2858.620000 935.740000 ;
      RECT 0.000000 917.440000 2859.820000 934.640000 ;
      RECT 1.200000 916.340000 2859.820000 917.440000 ;
      RECT 0.000000 868.640000 2859.820000 916.340000 ;
      RECT 0.000000 867.540000 2858.620000 868.640000 ;
      RECT 0.000000 851.560000 2859.820000 867.540000 ;
      RECT 1.200000 850.460000 2859.820000 851.560000 ;
      RECT 0.000000 802.150000 2859.820000 850.460000 ;
      RECT 0.000000 801.050000 2858.620000 802.150000 ;
      RECT 0.000000 786.290000 2859.820000 801.050000 ;
      RECT 1.200000 785.190000 2859.820000 786.290000 ;
      RECT 0.000000 735.660000 2859.820000 785.190000 ;
      RECT 0.000000 734.560000 2858.620000 735.660000 ;
      RECT 0.000000 721.020000 2859.820000 734.560000 ;
      RECT 1.200000 719.920000 2859.820000 721.020000 ;
      RECT 0.000000 668.560000 2859.820000 719.920000 ;
      RECT 0.000000 667.460000 2858.620000 668.560000 ;
      RECT 0.000000 655.750000 2859.820000 667.460000 ;
      RECT 1.200000 654.650000 2859.820000 655.750000 ;
      RECT 0.000000 602.070000 2859.820000 654.650000 ;
      RECT 0.000000 600.970000 2858.620000 602.070000 ;
      RECT 0.000000 589.870000 2859.820000 600.970000 ;
      RECT 1.200000 588.770000 2859.820000 589.870000 ;
      RECT 0.000000 534.970000 2859.820000 588.770000 ;
      RECT 0.000000 533.870000 2858.620000 534.970000 ;
      RECT 0.000000 524.600000 2859.820000 533.870000 ;
      RECT 1.200000 523.500000 2859.820000 524.600000 ;
      RECT 0.000000 468.480000 2859.820000 523.500000 ;
      RECT 0.000000 467.380000 2858.620000 468.480000 ;
      RECT 0.000000 459.330000 2859.820000 467.380000 ;
      RECT 1.200000 458.230000 2859.820000 459.330000 ;
      RECT 0.000000 401.990000 2859.820000 458.230000 ;
      RECT 0.000000 400.890000 2858.620000 401.990000 ;
      RECT 0.000000 393.450000 2859.820000 400.890000 ;
      RECT 1.200000 392.350000 2859.820000 393.450000 ;
      RECT 0.000000 334.890000 2859.820000 392.350000 ;
      RECT 0.000000 333.790000 2858.620000 334.890000 ;
      RECT 0.000000 328.180000 2859.820000 333.790000 ;
      RECT 1.200000 327.080000 2859.820000 328.180000 ;
      RECT 0.000000 268.400000 2859.820000 327.080000 ;
      RECT 0.000000 267.300000 2858.620000 268.400000 ;
      RECT 0.000000 262.910000 2859.820000 267.300000 ;
      RECT 1.200000 261.810000 2859.820000 262.910000 ;
      RECT 0.000000 201.910000 2859.820000 261.810000 ;
      RECT 0.000000 200.810000 2858.620000 201.910000 ;
      RECT 0.000000 197.030000 2859.820000 200.810000 ;
      RECT 1.200000 195.930000 2859.820000 197.030000 ;
      RECT 0.000000 134.810000 2859.820000 195.930000 ;
      RECT 0.000000 133.710000 2858.620000 134.810000 ;
      RECT 0.000000 131.760000 2859.820000 133.710000 ;
      RECT 1.200000 130.660000 2859.820000 131.760000 ;
      RECT 0.000000 68.320000 2859.820000 130.660000 ;
      RECT 0.000000 67.220000 2858.620000 68.320000 ;
      RECT 0.000000 66.490000 2859.820000 67.220000 ;
      RECT 1.200000 65.390000 2859.820000 66.490000 ;
      RECT 0.000000 1.220000 2859.820000 65.390000 ;
      RECT 1.200000 0.120000 2858.620000 1.220000 ;
      RECT 0.000000 0.000000 2859.820000 0.120000 ;
    LAYER met4 ;
      RECT 28.920000 3449.140000 2830.900000 3470.040000 ;
      RECT 2655.760000 3442.940000 2787.600000 3449.140000 ;
      RECT 2519.760000 3442.940000 2651.600000 3449.140000 ;
      RECT 2383.760000 3442.940000 2515.600000 3449.140000 ;
      RECT 2247.760000 3442.940000 2379.600000 3449.140000 ;
      RECT 2111.760000 3442.940000 2243.600000 3449.140000 ;
      RECT 1975.760000 3442.940000 2107.600000 3449.140000 ;
      RECT 1839.760000 3442.940000 1971.600000 3449.140000 ;
      RECT 1703.760000 3442.940000 1835.600000 3449.140000 ;
      RECT 1567.760000 3442.940000 1699.600000 3449.140000 ;
      RECT 1431.760000 3442.940000 1563.600000 3449.140000 ;
      RECT 1295.760000 3442.940000 1427.600000 3449.140000 ;
      RECT 1159.760000 3442.940000 1291.600000 3449.140000 ;
      RECT 1023.760000 3442.940000 1155.600000 3449.140000 ;
      RECT 887.760000 3442.940000 1019.600000 3449.140000 ;
      RECT 751.760000 3442.940000 883.600000 3449.140000 ;
      RECT 615.760000 3442.940000 747.600000 3449.140000 ;
      RECT 479.760000 3442.940000 611.600000 3449.140000 ;
      RECT 343.760000 3442.940000 475.600000 3449.140000 ;
      RECT 207.760000 3442.940000 339.600000 3449.140000 ;
      RECT 71.760000 3442.940000 203.600000 3449.140000 ;
      RECT 2655.760000 3348.675000 2719.600000 3442.940000 ;
      RECT 2179.760000 3348.675000 2243.600000 3442.940000 ;
      RECT 2043.760000 3348.675000 2107.600000 3442.940000 ;
      RECT 1567.760000 3348.675000 1631.600000 3442.940000 ;
      RECT 1431.760000 3348.675000 1495.600000 3442.940000 ;
      RECT 955.760000 3348.675000 1019.600000 3442.940000 ;
      RECT 819.760000 3348.675000 883.600000 3442.940000 ;
      RECT 343.760000 3348.675000 407.600000 3442.940000 ;
      RECT 2655.760000 3346.075000 2693.225000 3348.675000 ;
      RECT 2587.760000 3346.075000 2651.600000 3442.940000 ;
      RECT 2519.760000 3346.075000 2583.600000 3442.940000 ;
      RECT 2451.760000 3346.075000 2515.600000 3442.940000 ;
      RECT 2383.760000 3346.075000 2447.600000 3442.940000 ;
      RECT 2315.760000 3346.075000 2379.600000 3442.940000 ;
      RECT 2247.760000 3346.075000 2311.600000 3442.940000 ;
      RECT 2203.445000 3346.075000 2243.600000 3348.675000 ;
      RECT 1975.760000 3346.075000 2039.600000 3442.940000 ;
      RECT 1907.760000 3346.075000 1971.600000 3442.940000 ;
      RECT 1839.760000 3346.075000 1903.600000 3442.940000 ;
      RECT 1771.760000 3346.075000 1835.600000 3442.940000 ;
      RECT 1703.760000 3346.075000 1767.600000 3442.940000 ;
      RECT 1635.760000 3346.075000 1699.600000 3442.940000 ;
      RECT 1431.760000 3346.075000 1473.665000 3348.675000 ;
      RECT 1363.760000 3346.075000 1427.600000 3442.940000 ;
      RECT 1295.760000 3346.075000 1359.600000 3442.940000 ;
      RECT 1227.760000 3346.075000 1291.600000 3442.940000 ;
      RECT 1159.760000 3346.075000 1223.600000 3442.940000 ;
      RECT 1091.760000 3346.075000 1155.600000 3442.940000 ;
      RECT 1023.760000 3346.075000 1087.600000 3442.940000 ;
      RECT 983.885000 3346.075000 1019.600000 3348.675000 ;
      RECT 751.760000 3346.075000 815.600000 3442.940000 ;
      RECT 683.760000 3346.075000 747.600000 3442.940000 ;
      RECT 615.760000 3346.075000 679.600000 3442.940000 ;
      RECT 547.760000 3346.075000 611.600000 3442.940000 ;
      RECT 479.760000 3346.075000 543.600000 3442.940000 ;
      RECT 411.760000 3346.075000 475.600000 3442.940000 ;
      RECT 2587.760000 3345.075000 2693.225000 3346.075000 ;
      RECT 2203.445000 3345.075000 2311.600000 3346.075000 ;
      RECT 2043.760000 3345.075000 2083.445000 3348.675000 ;
      RECT 1593.665000 3345.075000 1631.600000 3348.675000 ;
      RECT 1363.760000 3345.075000 1473.665000 3346.075000 ;
      RECT 983.885000 3345.075000 1087.600000 3346.075000 ;
      RECT 819.760000 3345.075000 853.885000 3348.675000 ;
      RECT 364.105000 3345.075000 407.600000 3348.675000 ;
      RECT 2587.760000 3342.475000 2689.625000 3345.075000 ;
      RECT 2451.760000 3342.475000 2583.600000 3346.075000 ;
      RECT 2315.760000 3342.475000 2447.600000 3346.075000 ;
      RECT 2207.045000 3342.475000 2311.600000 3345.075000 ;
      RECT 2043.760000 3342.475000 2079.845000 3345.075000 ;
      RECT 1907.760000 3342.475000 2039.600000 3346.075000 ;
      RECT 1771.760000 3342.475000 1903.600000 3346.075000 ;
      RECT 1635.760000 3342.475000 1767.600000 3346.075000 ;
      RECT 1597.265000 3342.475000 1631.600000 3345.075000 ;
      RECT 1363.760000 3342.475000 1470.065000 3345.075000 ;
      RECT 1227.760000 3342.475000 1359.600000 3346.075000 ;
      RECT 1091.760000 3342.475000 1223.600000 3346.075000 ;
      RECT 987.485000 3342.475000 1087.600000 3345.075000 ;
      RECT 819.760000 3342.475000 850.285000 3345.075000 ;
      RECT 683.760000 3342.475000 815.600000 3346.075000 ;
      RECT 547.760000 3342.475000 679.600000 3346.075000 ;
      RECT 411.760000 3342.475000 543.600000 3346.075000 ;
      RECT 367.705000 3342.475000 407.600000 3345.075000 ;
      RECT 2207.045000 2942.175000 2689.625000 3342.475000 ;
      RECT 1597.265000 2942.175000 2079.845000 3342.475000 ;
      RECT 987.485000 2942.175000 1470.065000 3342.475000 ;
      RECT 367.705000 2942.175000 850.285000 3342.475000 ;
      RECT 2692.225000 2939.575000 2693.225000 3345.075000 ;
      RECT 2587.760000 2939.575000 2689.625000 2942.175000 ;
      RECT 2207.045000 2939.575000 2311.600000 2942.175000 ;
      RECT 2203.445000 2939.575000 2204.445000 3345.075000 ;
      RECT 2082.445000 2939.575000 2083.445000 3345.075000 ;
      RECT 2043.760000 2939.575000 2079.845000 2942.175000 ;
      RECT 1597.265000 2939.575000 1631.600000 2942.175000 ;
      RECT 1593.665000 2939.575000 1594.665000 3345.075000 ;
      RECT 1472.665000 2939.575000 1473.665000 3345.075000 ;
      RECT 1363.760000 2939.575000 1470.065000 2942.175000 ;
      RECT 987.485000 2939.575000 1087.600000 2942.175000 ;
      RECT 983.885000 2939.575000 984.885000 3345.075000 ;
      RECT 852.885000 2939.575000 853.885000 3345.075000 ;
      RECT 819.760000 2939.575000 850.285000 2942.175000 ;
      RECT 367.705000 2939.575000 407.600000 2942.175000 ;
      RECT 364.105000 2939.575000 365.105000 3345.075000 ;
      RECT 2587.760000 2938.575000 2693.225000 2939.575000 ;
      RECT 2451.760000 2938.575000 2583.600000 2942.175000 ;
      RECT 2315.760000 2938.575000 2447.600000 2942.175000 ;
      RECT 2203.445000 2938.575000 2311.600000 2939.575000 ;
      RECT 1907.760000 2938.575000 2039.600000 2942.175000 ;
      RECT 1771.760000 2938.575000 1903.600000 2942.175000 ;
      RECT 1635.760000 2938.575000 1767.600000 2942.175000 ;
      RECT 1363.760000 2938.575000 1473.665000 2939.575000 ;
      RECT 1227.760000 2938.575000 1359.600000 2942.175000 ;
      RECT 1091.760000 2938.575000 1223.600000 2942.175000 ;
      RECT 983.885000 2938.575000 1087.600000 2939.575000 ;
      RECT 683.760000 2938.575000 815.600000 2942.175000 ;
      RECT 547.760000 2938.575000 679.600000 2942.175000 ;
      RECT 411.760000 2938.575000 543.600000 2942.175000 ;
      RECT 2695.825000 2935.975000 2719.600000 3348.675000 ;
      RECT 2655.760000 2935.975000 2693.225000 2938.575000 ;
      RECT 2203.445000 2935.975000 2243.600000 2938.575000 ;
      RECT 2179.760000 2935.975000 2200.845000 3348.675000 ;
      RECT 2086.045000 2935.975000 2107.600000 3348.675000 ;
      RECT 2043.760000 2935.975000 2083.445000 2939.575000 ;
      RECT 1593.665000 2935.975000 1631.600000 2939.575000 ;
      RECT 1567.760000 2935.975000 1591.065000 3348.675000 ;
      RECT 1476.265000 2935.975000 1495.600000 3348.675000 ;
      RECT 1431.760000 2935.975000 1473.665000 2938.575000 ;
      RECT 983.885000 2935.975000 1019.600000 2938.575000 ;
      RECT 955.760000 2935.975000 981.285000 3348.675000 ;
      RECT 856.485000 2935.975000 883.600000 3348.675000 ;
      RECT 819.760000 2935.975000 853.885000 2939.575000 ;
      RECT 364.105000 2935.975000 407.600000 2939.575000 ;
      RECT 343.760000 2935.975000 361.505000 3348.675000 ;
      RECT 2655.760000 2851.175000 2719.600000 2935.975000 ;
      RECT 2179.760000 2851.175000 2243.600000 2935.975000 ;
      RECT 2043.760000 2851.175000 2107.600000 2935.975000 ;
      RECT 1567.760000 2851.175000 1631.600000 2935.975000 ;
      RECT 2655.760000 2848.575000 2693.225000 2851.175000 ;
      RECT 2587.760000 2848.575000 2651.600000 2938.575000 ;
      RECT 2519.760000 2848.575000 2583.600000 2938.575000 ;
      RECT 2451.760000 2848.575000 2515.600000 2938.575000 ;
      RECT 2383.760000 2848.575000 2447.600000 2938.575000 ;
      RECT 2315.760000 2848.575000 2379.600000 2938.575000 ;
      RECT 2247.760000 2848.575000 2311.600000 2938.575000 ;
      RECT 2203.445000 2848.575000 2243.600000 2851.175000 ;
      RECT 1975.760000 2848.575000 2039.600000 2938.575000 ;
      RECT 1907.760000 2848.575000 1971.600000 2938.575000 ;
      RECT 1839.760000 2848.575000 1903.600000 2938.575000 ;
      RECT 1771.760000 2848.575000 1835.600000 2938.575000 ;
      RECT 1703.760000 2848.575000 1767.600000 2938.575000 ;
      RECT 1635.760000 2848.575000 1699.600000 2938.575000 ;
      RECT 2587.760000 2847.575000 2693.225000 2848.575000 ;
      RECT 2203.445000 2847.575000 2311.600000 2848.575000 ;
      RECT 2043.760000 2847.575000 2083.445000 2851.175000 ;
      RECT 1593.665000 2847.575000 1631.600000 2851.175000 ;
      RECT 2587.760000 2844.975000 2689.625000 2847.575000 ;
      RECT 2451.760000 2844.975000 2583.600000 2848.575000 ;
      RECT 2315.760000 2844.975000 2447.600000 2848.575000 ;
      RECT 2207.045000 2844.975000 2311.600000 2847.575000 ;
      RECT 2043.760000 2844.975000 2079.845000 2847.575000 ;
      RECT 1907.760000 2844.975000 2039.600000 2848.575000 ;
      RECT 1771.760000 2844.975000 1903.600000 2848.575000 ;
      RECT 1635.760000 2844.975000 1767.600000 2848.575000 ;
      RECT 1597.265000 2844.975000 1631.600000 2847.575000 ;
      RECT 2207.045000 2444.675000 2689.625000 2844.975000 ;
      RECT 1597.265000 2444.675000 2079.845000 2844.975000 ;
      RECT 2692.225000 2442.075000 2693.225000 2847.575000 ;
      RECT 2587.760000 2442.075000 2689.625000 2444.675000 ;
      RECT 2207.045000 2442.075000 2311.600000 2444.675000 ;
      RECT 2203.445000 2442.075000 2204.445000 2847.575000 ;
      RECT 2082.445000 2442.075000 2083.445000 2847.575000 ;
      RECT 2043.760000 2442.075000 2079.845000 2444.675000 ;
      RECT 1597.265000 2442.075000 1631.600000 2444.675000 ;
      RECT 1593.665000 2442.075000 1594.665000 2847.575000 ;
      RECT 2587.760000 2441.075000 2693.225000 2442.075000 ;
      RECT 2451.760000 2441.075000 2583.600000 2444.675000 ;
      RECT 2315.760000 2441.075000 2447.600000 2444.675000 ;
      RECT 2203.445000 2441.075000 2311.600000 2442.075000 ;
      RECT 1907.760000 2441.075000 2039.600000 2444.675000 ;
      RECT 1771.760000 2441.075000 1903.600000 2444.675000 ;
      RECT 1635.760000 2441.075000 1767.600000 2444.675000 ;
      RECT 2695.825000 2438.475000 2719.600000 2851.175000 ;
      RECT 2655.760000 2438.475000 2693.225000 2441.075000 ;
      RECT 2203.445000 2438.475000 2243.600000 2441.075000 ;
      RECT 2179.760000 2438.475000 2200.845000 2851.175000 ;
      RECT 2086.045000 2438.475000 2107.600000 2851.175000 ;
      RECT 2043.760000 2438.475000 2083.445000 2442.075000 ;
      RECT 1593.665000 2438.475000 1631.600000 2442.075000 ;
      RECT 1567.760000 2438.475000 1591.065000 2851.175000 ;
      RECT 2655.760000 2353.675000 2719.600000 2438.475000 ;
      RECT 2179.760000 2353.675000 2243.600000 2438.475000 ;
      RECT 2043.760000 2353.675000 2107.600000 2438.475000 ;
      RECT 1567.760000 2353.675000 1631.600000 2438.475000 ;
      RECT 2655.760000 2351.075000 2693.225000 2353.675000 ;
      RECT 2587.760000 2351.075000 2651.600000 2441.075000 ;
      RECT 2519.760000 2351.075000 2583.600000 2441.075000 ;
      RECT 2451.760000 2351.075000 2515.600000 2441.075000 ;
      RECT 2383.760000 2351.075000 2447.600000 2441.075000 ;
      RECT 2315.760000 2351.075000 2379.600000 2441.075000 ;
      RECT 2247.760000 2351.075000 2311.600000 2441.075000 ;
      RECT 2203.445000 2351.075000 2243.600000 2353.675000 ;
      RECT 1975.760000 2351.075000 2039.600000 2441.075000 ;
      RECT 1907.760000 2351.075000 1971.600000 2441.075000 ;
      RECT 1839.760000 2351.075000 1903.600000 2441.075000 ;
      RECT 1771.760000 2351.075000 1835.600000 2441.075000 ;
      RECT 1703.760000 2351.075000 1767.600000 2441.075000 ;
      RECT 1635.760000 2351.075000 1699.600000 2441.075000 ;
      RECT 2587.760000 2350.075000 2693.225000 2351.075000 ;
      RECT 2203.445000 2350.075000 2311.600000 2351.075000 ;
      RECT 2043.760000 2350.075000 2083.445000 2353.675000 ;
      RECT 1593.665000 2350.075000 1631.600000 2353.675000 ;
      RECT 2587.760000 2347.475000 2689.625000 2350.075000 ;
      RECT 2451.760000 2347.475000 2583.600000 2351.075000 ;
      RECT 2315.760000 2347.475000 2447.600000 2351.075000 ;
      RECT 2207.045000 2347.475000 2311.600000 2350.075000 ;
      RECT 2043.760000 2347.475000 2079.845000 2350.075000 ;
      RECT 1907.760000 2347.475000 2039.600000 2351.075000 ;
      RECT 1771.760000 2347.475000 1903.600000 2351.075000 ;
      RECT 1635.760000 2347.475000 1767.600000 2351.075000 ;
      RECT 1597.265000 2347.475000 1631.600000 2350.075000 ;
      RECT 2207.045000 1947.175000 2689.625000 2347.475000 ;
      RECT 1597.265000 1947.175000 2079.845000 2347.475000 ;
      RECT 2692.225000 1944.575000 2693.225000 2350.075000 ;
      RECT 2587.760000 1944.575000 2689.625000 1947.175000 ;
      RECT 2207.045000 1944.575000 2311.600000 1947.175000 ;
      RECT 2203.445000 1944.575000 2204.445000 2350.075000 ;
      RECT 2082.445000 1944.575000 2083.445000 2350.075000 ;
      RECT 2043.760000 1944.575000 2079.845000 1947.175000 ;
      RECT 1597.265000 1944.575000 1631.600000 1947.175000 ;
      RECT 1593.665000 1944.575000 1594.665000 2350.075000 ;
      RECT 2587.760000 1943.575000 2693.225000 1944.575000 ;
      RECT 2451.760000 1943.575000 2583.600000 1947.175000 ;
      RECT 2315.760000 1943.575000 2447.600000 1947.175000 ;
      RECT 2203.445000 1943.575000 2311.600000 1944.575000 ;
      RECT 1907.760000 1943.575000 2039.600000 1947.175000 ;
      RECT 1771.760000 1943.575000 1903.600000 1947.175000 ;
      RECT 1635.760000 1943.575000 1767.600000 1947.175000 ;
      RECT 2695.825000 1940.975000 2719.600000 2353.675000 ;
      RECT 2655.760000 1940.975000 2693.225000 1943.575000 ;
      RECT 2203.445000 1940.975000 2243.600000 1943.575000 ;
      RECT 2179.760000 1940.975000 2200.845000 2353.675000 ;
      RECT 2086.045000 1940.975000 2107.600000 2353.675000 ;
      RECT 2043.760000 1940.975000 2083.445000 1944.575000 ;
      RECT 1593.665000 1940.975000 1631.600000 1944.575000 ;
      RECT 1567.760000 1940.975000 1591.065000 2353.675000 ;
      RECT 2655.760000 1856.175000 2719.600000 1940.975000 ;
      RECT 2179.760000 1856.175000 2243.600000 1940.975000 ;
      RECT 2043.760000 1856.175000 2107.600000 1940.975000 ;
      RECT 1567.760000 1856.175000 1631.600000 1940.975000 ;
      RECT 2655.760000 1853.575000 2693.225000 1856.175000 ;
      RECT 2587.760000 1853.575000 2651.600000 1943.575000 ;
      RECT 2519.760000 1853.575000 2583.600000 1943.575000 ;
      RECT 2451.760000 1853.575000 2515.600000 1943.575000 ;
      RECT 2383.760000 1853.575000 2447.600000 1943.575000 ;
      RECT 2315.760000 1853.575000 2379.600000 1943.575000 ;
      RECT 2247.760000 1853.575000 2311.600000 1943.575000 ;
      RECT 2203.445000 1853.575000 2243.600000 1856.175000 ;
      RECT 1975.760000 1853.575000 2039.600000 1943.575000 ;
      RECT 1907.760000 1853.575000 1971.600000 1943.575000 ;
      RECT 1839.760000 1853.575000 1903.600000 1943.575000 ;
      RECT 1771.760000 1853.575000 1835.600000 1943.575000 ;
      RECT 1703.760000 1853.575000 1767.600000 1943.575000 ;
      RECT 1635.760000 1853.575000 1699.600000 1943.575000 ;
      RECT 2587.760000 1852.575000 2693.225000 1853.575000 ;
      RECT 2203.445000 1852.575000 2311.600000 1853.575000 ;
      RECT 2043.760000 1852.575000 2083.445000 1856.175000 ;
      RECT 1593.665000 1852.575000 1631.600000 1856.175000 ;
      RECT 2587.760000 1849.975000 2689.625000 1852.575000 ;
      RECT 2451.760000 1849.975000 2583.600000 1853.575000 ;
      RECT 2315.760000 1849.975000 2447.600000 1853.575000 ;
      RECT 2207.045000 1849.975000 2311.600000 1852.575000 ;
      RECT 2043.760000 1849.975000 2079.845000 1852.575000 ;
      RECT 1907.760000 1849.975000 2039.600000 1853.575000 ;
      RECT 1771.760000 1849.975000 1903.600000 1853.575000 ;
      RECT 1635.760000 1849.975000 1767.600000 1853.575000 ;
      RECT 1597.265000 1849.975000 1631.600000 1852.575000 ;
      RECT 2207.045000 1449.675000 2689.625000 1849.975000 ;
      RECT 1597.265000 1449.675000 2079.845000 1849.975000 ;
      RECT 2692.225000 1447.075000 2693.225000 1852.575000 ;
      RECT 2587.760000 1447.075000 2689.625000 1449.675000 ;
      RECT 2207.045000 1447.075000 2311.600000 1449.675000 ;
      RECT 2203.445000 1447.075000 2204.445000 1852.575000 ;
      RECT 2082.445000 1447.075000 2083.445000 1852.575000 ;
      RECT 2043.760000 1447.075000 2079.845000 1449.675000 ;
      RECT 1597.265000 1447.075000 1631.600000 1449.675000 ;
      RECT 1593.665000 1447.075000 1594.665000 1852.575000 ;
      RECT 2587.760000 1446.075000 2693.225000 1447.075000 ;
      RECT 2451.760000 1446.075000 2583.600000 1449.675000 ;
      RECT 2315.760000 1446.075000 2447.600000 1449.675000 ;
      RECT 2203.445000 1446.075000 2311.600000 1447.075000 ;
      RECT 1907.760000 1446.075000 2039.600000 1449.675000 ;
      RECT 1771.760000 1446.075000 1903.600000 1449.675000 ;
      RECT 1635.760000 1446.075000 1767.600000 1449.675000 ;
      RECT 2695.825000 1443.475000 2719.600000 1856.175000 ;
      RECT 2655.760000 1443.475000 2693.225000 1446.075000 ;
      RECT 2203.445000 1443.475000 2243.600000 1446.075000 ;
      RECT 2179.760000 1443.475000 2200.845000 1856.175000 ;
      RECT 2086.045000 1443.475000 2107.600000 1856.175000 ;
      RECT 2043.760000 1443.475000 2083.445000 1447.075000 ;
      RECT 1593.665000 1443.475000 1631.600000 1447.075000 ;
      RECT 1567.760000 1443.475000 1591.065000 1856.175000 ;
      RECT 2723.760000 25.060000 2787.600000 3442.940000 ;
      RECT 2655.760000 25.060000 2719.600000 1443.475000 ;
      RECT 2587.760000 25.060000 2651.600000 1446.075000 ;
      RECT 2519.760000 25.060000 2583.600000 1446.075000 ;
      RECT 2451.760000 25.060000 2515.600000 1446.075000 ;
      RECT 2383.760000 25.060000 2447.600000 1446.075000 ;
      RECT 2315.760000 25.060000 2379.600000 1446.075000 ;
      RECT 2247.760000 25.060000 2311.600000 1446.075000 ;
      RECT 2179.760000 25.060000 2243.600000 1443.475000 ;
      RECT 2111.760000 25.060000 2175.600000 3442.940000 ;
      RECT 2043.760000 25.060000 2107.600000 1443.475000 ;
      RECT 1975.760000 25.060000 2039.600000 1446.075000 ;
      RECT 1907.760000 25.060000 1971.600000 1446.075000 ;
      RECT 1839.760000 25.060000 1903.600000 1446.075000 ;
      RECT 1771.760000 25.060000 1835.600000 1446.075000 ;
      RECT 1703.760000 25.060000 1767.600000 1446.075000 ;
      RECT 1635.760000 25.060000 1699.600000 1446.075000 ;
      RECT 1567.760000 25.060000 1631.600000 1443.475000 ;
      RECT 1499.760000 25.060000 1563.600000 3442.940000 ;
      RECT 1431.760000 25.060000 1495.600000 2935.975000 ;
      RECT 1363.760000 25.060000 1427.600000 2938.575000 ;
      RECT 1295.760000 25.060000 1359.600000 2938.575000 ;
      RECT 1227.760000 25.060000 1291.600000 2938.575000 ;
      RECT 1159.760000 25.060000 1223.600000 2938.575000 ;
      RECT 1091.760000 25.060000 1155.600000 2938.575000 ;
      RECT 1023.760000 25.060000 1087.600000 2938.575000 ;
      RECT 955.760000 25.060000 1019.600000 2935.975000 ;
      RECT 887.760000 25.060000 951.600000 3442.940000 ;
      RECT 819.760000 25.060000 883.600000 2935.975000 ;
      RECT 751.760000 25.060000 815.600000 2938.575000 ;
      RECT 683.760000 25.060000 747.600000 2938.575000 ;
      RECT 615.760000 25.060000 679.600000 2938.575000 ;
      RECT 547.760000 25.060000 611.600000 2938.575000 ;
      RECT 479.760000 25.060000 543.600000 2938.575000 ;
      RECT 411.760000 25.060000 475.600000 2938.575000 ;
      RECT 343.760000 25.060000 407.600000 2935.975000 ;
      RECT 275.760000 25.060000 339.600000 3442.940000 ;
      RECT 207.760000 25.060000 271.600000 3442.940000 ;
      RECT 139.760000 25.060000 203.600000 3442.940000 ;
      RECT 71.760000 25.060000 135.600000 3442.940000 ;
      RECT 2791.760000 18.860000 2830.900000 3449.140000 ;
      RECT 2655.760000 18.860000 2787.600000 25.060000 ;
      RECT 2519.760000 18.860000 2651.600000 25.060000 ;
      RECT 2383.760000 18.860000 2515.600000 25.060000 ;
      RECT 2247.760000 18.860000 2379.600000 25.060000 ;
      RECT 2111.760000 18.860000 2243.600000 25.060000 ;
      RECT 1975.760000 18.860000 2107.600000 25.060000 ;
      RECT 1839.760000 18.860000 1971.600000 25.060000 ;
      RECT 1703.760000 18.860000 1835.600000 25.060000 ;
      RECT 1567.760000 18.860000 1699.600000 25.060000 ;
      RECT 1431.760000 18.860000 1563.600000 25.060000 ;
      RECT 1295.760000 18.860000 1427.600000 25.060000 ;
      RECT 1159.760000 18.860000 1291.600000 25.060000 ;
      RECT 1023.760000 18.860000 1155.600000 25.060000 ;
      RECT 887.760000 18.860000 1019.600000 25.060000 ;
      RECT 751.760000 18.860000 883.600000 25.060000 ;
      RECT 615.760000 18.860000 747.600000 25.060000 ;
      RECT 479.760000 18.860000 611.600000 25.060000 ;
      RECT 343.760000 18.860000 475.600000 25.060000 ;
      RECT 207.760000 18.860000 339.600000 25.060000 ;
      RECT 71.760000 18.860000 203.600000 25.060000 ;
      RECT 28.920000 18.860000 67.600000 3449.140000 ;
      RECT 2841.000000 0.000000 2859.820000 3470.040000 ;
      RECT 2834.800000 0.000000 2837.100000 3470.040000 ;
      RECT 28.920000 0.000000 2830.900000 18.860000 ;
      RECT 22.720000 0.000000 25.020000 3470.040000 ;
      RECT 0.000000 0.000000 18.820000 3470.040000 ;
  END
END user_proj_example

END LIBRARY
